# Generated deterministically by seda-macro-lef-normalizer-v1; recipe orfs-ng45-fakeram-metal3-coupledl2-pg-v1.
VERSION 5.8 ;
BUSBITCHARS "[]" ;
DIVIDERCHAR "/" ;

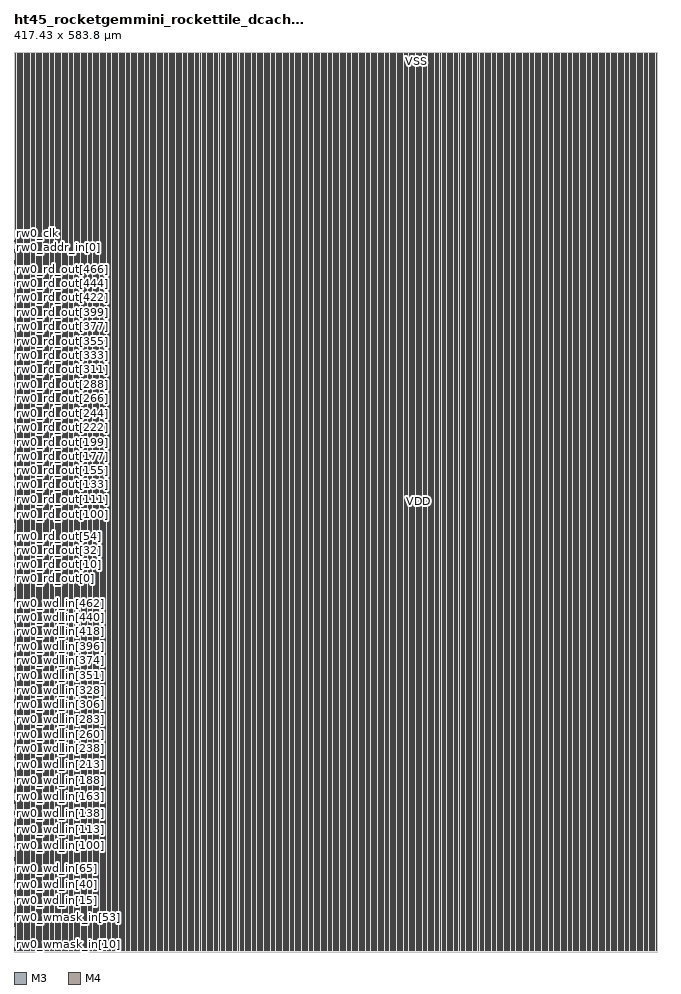
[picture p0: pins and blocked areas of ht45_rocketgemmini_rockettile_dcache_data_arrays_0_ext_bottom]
MACRO ht45_rocketgemmini_rockettile_dcache_data_arrays_0_ext_bottom
  FOREIGN ht45_rocketgemmini_rockettile_dcache_data_arrays_0_ext_bottom 0 0 ;
  CLASS COVER ;
  ORIGIN 0 0 ;
  SIZE 417.43 BY 583.8 ;
  SYMMETRY X Y R90 ;
  PIN rw0_wmask_in[0]
    DIRECTION INPUT ;
    USE SIGNAL ;
    SHAPE ABUTMENT ;
    PORT
      LAYER M3 ;
      RECT 0 0.035 0.07 0.105 ;
    END
  END rw0_wmask_in[0]
  PIN rw0_wmask_in[1]
    DIRECTION INPUT ;
    USE SIGNAL ;
    SHAPE ABUTMENT ;
    PORT
      LAYER M3 ;
      RECT 0 0.455 0.07 0.525 ;
    END
  END rw0_wmask_in[1]
  PIN rw0_wmask_in[2]
    DIRECTION INPUT ;
    USE SIGNAL ;
    SHAPE ABUTMENT ;
    PORT
      LAYER M3 ;
      RECT 0 0.875 0.07 0.945 ;
    END
  END rw0_wmask_in[2]
  PIN rw0_wmask_in[3]
    DIRECTION INPUT ;
    USE SIGNAL ;
    SHAPE ABUTMENT ;
    PORT
      LAYER M3 ;
      RECT 0 1.295 0.07 1.365 ;
    END
  END rw0_wmask_in[3]
  PIN rw0_wmask_in[4]
    DIRECTION INPUT ;
    USE SIGNAL ;
    SHAPE ABUTMENT ;
    PORT
      LAYER M3 ;
      RECT 0 1.715 0.07 1.785 ;
    END
  END rw0_wmask_in[4]
  PIN rw0_wmask_in[5]
    DIRECTION INPUT ;
    USE SIGNAL ;
    SHAPE ABUTMENT ;
    PORT
      LAYER M3 ;
      RECT 0 2.135 0.07 2.205 ;
    END
  END rw0_wmask_in[5]
  PIN rw0_wmask_in[6]
    DIRECTION INPUT ;
    USE SIGNAL ;
    SHAPE ABUTMENT ;
    PORT
      LAYER M3 ;
      RECT 0 2.555 0.07 2.625 ;
    END
  END rw0_wmask_in[6]
  PIN rw0_wmask_in[7]
    DIRECTION INPUT ;
    USE SIGNAL ;
    SHAPE ABUTMENT ;
    PORT
      LAYER M3 ;
      RECT 0 2.975 0.07 3.045 ;
    END
  END rw0_wmask_in[7]
  PIN rw0_wmask_in[8]
    DIRECTION INPUT ;
    USE SIGNAL ;
    SHAPE ABUTMENT ;
    PORT
      LAYER M3 ;
      RECT 0 3.395 0.07 3.465 ;
    END
  END rw0_wmask_in[8]
  PIN rw0_wmask_in[9]
    DIRECTION INPUT ;
    USE SIGNAL ;
    SHAPE ABUTMENT ;
    PORT
      LAYER M3 ;
      RECT 0 3.815 0.07 3.885 ;
    END
  END rw0_wmask_in[9]
  PIN rw0_wmask_in[10]
    DIRECTION INPUT ;
    USE SIGNAL ;
    SHAPE ABUTMENT ;
    PORT
      LAYER M3 ;
      RECT 0 4.235 0.07 4.305 ;
    END
  END rw0_wmask_in[10]
  PIN rw0_wmask_in[11]
    DIRECTION INPUT ;
    USE SIGNAL ;
    SHAPE ABUTMENT ;
    PORT
      LAYER M3 ;
      RECT 0 4.655 0.07 4.725 ;
    END
  END rw0_wmask_in[11]
  PIN rw0_wmask_in[12]
    DIRECTION INPUT ;
    USE SIGNAL ;
    SHAPE ABUTMENT ;
    PORT
      LAYER M3 ;
      RECT 0 5.075 0.07 5.145 ;
    END
  END rw0_wmask_in[12]
  PIN rw0_wmask_in[13]
    DIRECTION INPUT ;
    USE SIGNAL ;
    SHAPE ABUTMENT ;
    PORT
      LAYER M3 ;
      RECT 0 5.495 0.07 5.565 ;
    END
  END rw0_wmask_in[13]
  PIN rw0_wmask_in[14]
    DIRECTION INPUT ;
    USE SIGNAL ;
    SHAPE ABUTMENT ;
    PORT
      LAYER M3 ;
      RECT 0 5.915 0.07 5.985 ;
    END
  END rw0_wmask_in[14]
  PIN rw0_wmask_in[15]
    DIRECTION INPUT ;
    USE SIGNAL ;
    SHAPE ABUTMENT ;
    PORT
      LAYER M3 ;
      RECT 0 6.335 0.07 6.405 ;
    END
  END rw0_wmask_in[15]
  PIN rw0_wmask_in[16]
    DIRECTION INPUT ;
    USE SIGNAL ;
    SHAPE ABUTMENT ;
    PORT
      LAYER M3 ;
      RECT 0 6.755 0.07 6.825 ;
    END
  END rw0_wmask_in[16]
  PIN rw0_wmask_in[17]
    DIRECTION INPUT ;
    USE SIGNAL ;
    SHAPE ABUTMENT ;
    PORT
      LAYER M3 ;
      RECT 0 7.175 0.07 7.245 ;
    END
  END rw0_wmask_in[17]
  PIN rw0_wmask_in[18]
    DIRECTION INPUT ;
    USE SIGNAL ;
    SHAPE ABUTMENT ;
    PORT
      LAYER M3 ;
      RECT 0 7.595 0.07 7.665 ;
    END
  END rw0_wmask_in[18]
  PIN rw0_wmask_in[19]
    DIRECTION INPUT ;
    USE SIGNAL ;
    SHAPE ABUTMENT ;
    PORT
      LAYER M3 ;
      RECT 0 8.015 0.07 8.085 ;
    END
  END rw0_wmask_in[19]
  PIN rw0_wmask_in[20]
    DIRECTION INPUT ;
    USE SIGNAL ;
    SHAPE ABUTMENT ;
    PORT
      LAYER M3 ;
      RECT 0 8.435 0.07 8.505 ;
    END
  END rw0_wmask_in[20]
  PIN rw0_wmask_in[21]
    DIRECTION INPUT ;
    USE SIGNAL ;
    SHAPE ABUTMENT ;
    PORT
      LAYER M3 ;
      RECT 0 8.855 0.07 8.925 ;
    END
  END rw0_wmask_in[21]
  PIN rw0_wmask_in[22]
    DIRECTION INPUT ;
    USE SIGNAL ;
    SHAPE ABUTMENT ;
    PORT
      LAYER M3 ;
      RECT 0 9.275 0.07 9.345 ;
    END
  END rw0_wmask_in[22]
  PIN rw0_wmask_in[23]
    DIRECTION INPUT ;
    USE SIGNAL ;
    SHAPE ABUTMENT ;
    PORT
      LAYER M3 ;
      RECT 0 9.695 0.07 9.765 ;
    END
  END rw0_wmask_in[23]
  PIN rw0_wmask_in[24]
    DIRECTION INPUT ;
    USE SIGNAL ;
    SHAPE ABUTMENT ;
    PORT
      LAYER M3 ;
      RECT 0 10.115 0.07 10.185 ;
    END
  END rw0_wmask_in[24]
  PIN rw0_wmask_in[25]
    DIRECTION INPUT ;
    USE SIGNAL ;
    SHAPE ABUTMENT ;
    PORT
      LAYER M3 ;
      RECT 0 10.535 0.07 10.605 ;
    END
  END rw0_wmask_in[25]
  PIN rw0_wmask_in[26]
    DIRECTION INPUT ;
    USE SIGNAL ;
    SHAPE ABUTMENT ;
    PORT
      LAYER M3 ;
      RECT 0 10.955 0.07 11.025 ;
    END
  END rw0_wmask_in[26]
  PIN rw0_wmask_in[27]
    DIRECTION INPUT ;
    USE SIGNAL ;
    SHAPE ABUTMENT ;
    PORT
      LAYER M3 ;
      RECT 0 11.375 0.07 11.445 ;
    END
  END rw0_wmask_in[27]
  PIN rw0_wmask_in[28]
    DIRECTION INPUT ;
    USE SIGNAL ;
    SHAPE ABUTMENT ;
    PORT
      LAYER M3 ;
      RECT 0 11.795 0.07 11.865 ;
    END
  END rw0_wmask_in[28]
  PIN rw0_wmask_in[29]
    DIRECTION INPUT ;
    USE SIGNAL ;
    SHAPE ABUTMENT ;
    PORT
      LAYER M3 ;
      RECT 0 12.215 0.07 12.285 ;
    END
  END rw0_wmask_in[29]
  PIN rw0_wmask_in[30]
    DIRECTION INPUT ;
    USE SIGNAL ;
    SHAPE ABUTMENT ;
    PORT
      LAYER M3 ;
      RECT 0 12.635 0.07 12.705 ;
    END
  END rw0_wmask_in[30]
  PIN rw0_wmask_in[31]
    DIRECTION INPUT ;
    USE SIGNAL ;
    SHAPE ABUTMENT ;
    PORT
      LAYER M3 ;
      RECT 0 13.055 0.07 13.125 ;
    END
  END rw0_wmask_in[31]
  PIN rw0_wmask_in[32]
    DIRECTION INPUT ;
    USE SIGNAL ;
    SHAPE ABUTMENT ;
    PORT
      LAYER M3 ;
      RECT 0 13.475 0.07 13.545 ;
    END
  END rw0_wmask_in[32]
  PIN rw0_wmask_in[33]
    DIRECTION INPUT ;
    USE SIGNAL ;
    SHAPE ABUTMENT ;
    PORT
      LAYER M3 ;
      RECT 0 13.895 0.07 13.965 ;
    END
  END rw0_wmask_in[33]
  PIN rw0_wmask_in[34]
    DIRECTION INPUT ;
    USE SIGNAL ;
    SHAPE ABUTMENT ;
    PORT
      LAYER M3 ;
      RECT 0 14.315 0.07 14.385 ;
    END
  END rw0_wmask_in[34]
  PIN rw0_wmask_in[35]
    DIRECTION INPUT ;
    USE SIGNAL ;
    SHAPE ABUTMENT ;
    PORT
      LAYER M3 ;
      RECT 0 14.735 0.07 14.805 ;
    END
  END rw0_wmask_in[35]
  PIN rw0_wmask_in[36]
    DIRECTION INPUT ;
    USE SIGNAL ;
    SHAPE ABUTMENT ;
    PORT
      LAYER M3 ;
      RECT 0 15.155 0.07 15.225 ;
    END
  END rw0_wmask_in[36]
  PIN rw0_wmask_in[37]
    DIRECTION INPUT ;
    USE SIGNAL ;
    SHAPE ABUTMENT ;
    PORT
      LAYER M3 ;
      RECT 0 15.575 0.07 15.645 ;
    END
  END rw0_wmask_in[37]
  PIN rw0_wmask_in[38]
    DIRECTION INPUT ;
    USE SIGNAL ;
    SHAPE ABUTMENT ;
    PORT
      LAYER M3 ;
      RECT 0 15.995 0.07 16.065 ;
    END
  END rw0_wmask_in[38]
  PIN rw0_wmask_in[39]
    DIRECTION INPUT ;
    USE SIGNAL ;
    SHAPE ABUTMENT ;
    PORT
      LAYER M3 ;
      RECT 0 16.415 0.07 16.485 ;
    END
  END rw0_wmask_in[39]
  PIN rw0_wmask_in[40]
    DIRECTION INPUT ;
    USE SIGNAL ;
    SHAPE ABUTMENT ;
    PORT
      LAYER M3 ;
      RECT 0 16.835 0.07 16.905 ;
    END
  END rw0_wmask_in[40]
  PIN rw0_wmask_in[41]
    DIRECTION INPUT ;
    USE SIGNAL ;
    SHAPE ABUTMENT ;
    PORT
      LAYER M3 ;
      RECT 0 17.255 0.07 17.325 ;
    END
  END rw0_wmask_in[41]
  PIN rw0_wmask_in[42]
    DIRECTION INPUT ;
    USE SIGNAL ;
    SHAPE ABUTMENT ;
    PORT
      LAYER M3 ;
      RECT 0 17.675 0.07 17.745 ;
    END
  END rw0_wmask_in[42]
  PIN rw0_wmask_in[43]
    DIRECTION INPUT ;
    USE SIGNAL ;
    SHAPE ABUTMENT ;
    PORT
      LAYER M3 ;
      RECT 0 18.095 0.07 18.165 ;
    END
  END rw0_wmask_in[43]
  PIN rw0_wmask_in[44]
    DIRECTION INPUT ;
    USE SIGNAL ;
    SHAPE ABUTMENT ;
    PORT
      LAYER M3 ;
      RECT 0 18.515 0.07 18.585 ;
    END
  END rw0_wmask_in[44]
  PIN rw0_wmask_in[45]
    DIRECTION INPUT ;
    USE SIGNAL ;
    SHAPE ABUTMENT ;
    PORT
      LAYER M3 ;
      RECT 0 18.935 0.07 19.005 ;
    END
  END rw0_wmask_in[45]
  PIN rw0_wmask_in[46]
    DIRECTION INPUT ;
    USE SIGNAL ;
    SHAPE ABUTMENT ;
    PORT
      LAYER M3 ;
      RECT 0 19.355 0.07 19.425 ;
    END
  END rw0_wmask_in[46]
  PIN rw0_wmask_in[47]
    DIRECTION INPUT ;
    USE SIGNAL ;
    SHAPE ABUTMENT ;
    PORT
      LAYER M3 ;
      RECT 0 19.775 0.07 19.845 ;
    END
  END rw0_wmask_in[47]
  PIN rw0_wmask_in[48]
    DIRECTION INPUT ;
    USE SIGNAL ;
    SHAPE ABUTMENT ;
    PORT
      LAYER M3 ;
      RECT 0 20.195 0.07 20.265 ;
    END
  END rw0_wmask_in[48]
  PIN rw0_wmask_in[49]
    DIRECTION INPUT ;
    USE SIGNAL ;
    SHAPE ABUTMENT ;
    PORT
      LAYER M3 ;
      RECT 0 20.615 0.07 20.685 ;
    END
  END rw0_wmask_in[49]
  PIN rw0_wmask_in[50]
    DIRECTION INPUT ;
    USE SIGNAL ;
    SHAPE ABUTMENT ;
    PORT
      LAYER M3 ;
      RECT 0 21.035 0.07 21.105 ;
    END
  END rw0_wmask_in[50]
  PIN rw0_wmask_in[51]
    DIRECTION INPUT ;
    USE SIGNAL ;
    SHAPE ABUTMENT ;
    PORT
      LAYER M3 ;
      RECT 0 21.455 0.07 21.525 ;
    END
  END rw0_wmask_in[51]
  PIN rw0_wmask_in[52]
    DIRECTION INPUT ;
    USE SIGNAL ;
    SHAPE ABUTMENT ;
    PORT
      LAYER M3 ;
      RECT 0 21.875 0.07 21.945 ;
    END
  END rw0_wmask_in[52]
  PIN rw0_wmask_in[53]
    DIRECTION INPUT ;
    USE SIGNAL ;
    SHAPE ABUTMENT ;
    PORT
      LAYER M3 ;
      RECT 0 22.295 0.07 22.365 ;
    END
  END rw0_wmask_in[53]
  PIN rw0_wmask_in[54]
    DIRECTION INPUT ;
    USE SIGNAL ;
    SHAPE ABUTMENT ;
    PORT
      LAYER M3 ;
      RECT 0 22.715 0.07 22.785 ;
    END
  END rw0_wmask_in[54]
  PIN rw0_wmask_in[55]
    DIRECTION INPUT ;
    USE SIGNAL ;
    SHAPE ABUTMENT ;
    PORT
      LAYER M3 ;
      RECT 0 23.135 0.07 23.205 ;
    END
  END rw0_wmask_in[55]
  PIN rw0_wmask_in[56]
    DIRECTION INPUT ;
    USE SIGNAL ;
    SHAPE ABUTMENT ;
    PORT
      LAYER M3 ;
      RECT 0 23.555 0.07 23.625 ;
    END
  END rw0_wmask_in[56]
  PIN rw0_wmask_in[57]
    DIRECTION INPUT ;
    USE SIGNAL ;
    SHAPE ABUTMENT ;
    PORT
      LAYER M3 ;
      RECT 0 23.975 0.07 24.045 ;
    END
  END rw0_wmask_in[57]
  PIN rw0_wmask_in[58]
    DIRECTION INPUT ;
    USE SIGNAL ;
    SHAPE ABUTMENT ;
    PORT
      LAYER M3 ;
      RECT 0 24.395 0.07 24.465 ;
    END
  END rw0_wmask_in[58]
  PIN rw0_wmask_in[59]
    DIRECTION INPUT ;
    USE SIGNAL ;
    SHAPE ABUTMENT ;
    PORT
      LAYER M3 ;
      RECT 0 24.815 0.07 24.885 ;
    END
  END rw0_wmask_in[59]
  PIN rw0_wmask_in[60]
    DIRECTION INPUT ;
    USE SIGNAL ;
    SHAPE ABUTMENT ;
    PORT
      LAYER M3 ;
      RECT 0 25.235 0.07 25.305 ;
    END
  END rw0_wmask_in[60]
  PIN rw0_wmask_in[61]
    DIRECTION INPUT ;
    USE SIGNAL ;
    SHAPE ABUTMENT ;
    PORT
      LAYER M3 ;
      RECT 0 25.655 0.07 25.725 ;
    END
  END rw0_wmask_in[61]
  PIN rw0_wmask_in[62]
    DIRECTION INPUT ;
    USE SIGNAL ;
    SHAPE ABUTMENT ;
    PORT
      LAYER M3 ;
      RECT 0 26.075 0.07 26.145 ;
    END
  END rw0_wmask_in[62]
  PIN rw0_wmask_in[63]
    DIRECTION INPUT ;
    USE SIGNAL ;
    SHAPE ABUTMENT ;
    PORT
      LAYER M3 ;
      RECT 0 26.495 0.07 26.565 ;
    END
  END rw0_wmask_in[63]
  PIN rw0_wd_in[0]
    DIRECTION INPUT ;
    USE SIGNAL ;
    SHAPE ABUTMENT ;
    PORT
      LAYER M3 ;
      RECT 0 26.915 0.07 26.985 ;
    END
  END rw0_wd_in[0]
  PIN rw0_wd_in[1]
    DIRECTION INPUT ;
    USE SIGNAL ;
    SHAPE ABUTMENT ;
    PORT
      LAYER M3 ;
      RECT 0 27.335 0.07 27.405 ;
    END
  END rw0_wd_in[1]
  PIN rw0_wd_in[2]
    DIRECTION INPUT ;
    USE SIGNAL ;
    SHAPE ABUTMENT ;
    PORT
      LAYER M3 ;
      RECT 0 27.755 0.07 27.825 ;
    END
  END rw0_wd_in[2]
  PIN rw0_wd_in[3]
    DIRECTION INPUT ;
    USE SIGNAL ;
    SHAPE ABUTMENT ;
    PORT
      LAYER M3 ;
      RECT 0 28.175 0.07 28.245 ;
    END
  END rw0_wd_in[3]
  PIN rw0_wd_in[4]
    DIRECTION INPUT ;
    USE SIGNAL ;
    SHAPE ABUTMENT ;
    PORT
      LAYER M3 ;
      RECT 0 28.595 0.07 28.665 ;
    END
  END rw0_wd_in[4]
  PIN rw0_wd_in[5]
    DIRECTION INPUT ;
    USE SIGNAL ;
    SHAPE ABUTMENT ;
    PORT
      LAYER M3 ;
      RECT 0 29.015 0.07 29.085 ;
    END
  END rw0_wd_in[5]
  PIN rw0_wd_in[6]
    DIRECTION INPUT ;
    USE SIGNAL ;
    SHAPE ABUTMENT ;
    PORT
      LAYER M3 ;
      RECT 0 29.435 0.07 29.505 ;
    END
  END rw0_wd_in[6]
  PIN rw0_wd_in[7]
    DIRECTION INPUT ;
    USE SIGNAL ;
    SHAPE ABUTMENT ;
    PORT
      LAYER M3 ;
      RECT 0 29.855 0.07 29.925 ;
    END
  END rw0_wd_in[7]
  PIN rw0_wd_in[8]
    DIRECTION INPUT ;
    USE SIGNAL ;
    SHAPE ABUTMENT ;
    PORT
      LAYER M3 ;
      RECT 0 30.275 0.07 30.345 ;
    END
  END rw0_wd_in[8]
  PIN rw0_wd_in[9]
    DIRECTION INPUT ;
    USE SIGNAL ;
    SHAPE ABUTMENT ;
    PORT
      LAYER M3 ;
      RECT 0 30.695 0.07 30.765 ;
    END
  END rw0_wd_in[9]
  PIN rw0_wd_in[10]
    DIRECTION INPUT ;
    USE SIGNAL ;
    SHAPE ABUTMENT ;
    PORT
      LAYER M3 ;
      RECT 0 31.115 0.07 31.185 ;
    END
  END rw0_wd_in[10]
  PIN rw0_wd_in[11]
    DIRECTION INPUT ;
    USE SIGNAL ;
    SHAPE ABUTMENT ;
    PORT
      LAYER M3 ;
      RECT 0 31.535 0.07 31.605 ;
    END
  END rw0_wd_in[11]
  PIN rw0_wd_in[12]
    DIRECTION INPUT ;
    USE SIGNAL ;
    SHAPE ABUTMENT ;
    PORT
      LAYER M3 ;
      RECT 0 31.955 0.07 32.025 ;
    END
  END rw0_wd_in[12]
  PIN rw0_wd_in[13]
    DIRECTION INPUT ;
    USE SIGNAL ;
    SHAPE ABUTMENT ;
    PORT
      LAYER M3 ;
      RECT 0 32.375 0.07 32.445 ;
    END
  END rw0_wd_in[13]
  PIN rw0_wd_in[14]
    DIRECTION INPUT ;
    USE SIGNAL ;
    SHAPE ABUTMENT ;
    PORT
      LAYER M3 ;
      RECT 0 32.795 0.07 32.865 ;
    END
  END rw0_wd_in[14]
  PIN rw0_wd_in[15]
    DIRECTION INPUT ;
    USE SIGNAL ;
    SHAPE ABUTMENT ;
    PORT
      LAYER M3 ;
      RECT 0 33.215 0.07 33.285 ;
    END
  END rw0_wd_in[15]
  PIN rw0_wd_in[16]
    DIRECTION INPUT ;
    USE SIGNAL ;
    SHAPE ABUTMENT ;
    PORT
      LAYER M3 ;
      RECT 0 33.635 0.07 33.705 ;
    END
  END rw0_wd_in[16]
  PIN rw0_wd_in[17]
    DIRECTION INPUT ;
    USE SIGNAL ;
    SHAPE ABUTMENT ;
    PORT
      LAYER M3 ;
      RECT 0 34.055 0.07 34.125 ;
    END
  END rw0_wd_in[17]
  PIN rw0_wd_in[18]
    DIRECTION INPUT ;
    USE SIGNAL ;
    SHAPE ABUTMENT ;
    PORT
      LAYER M3 ;
      RECT 0 34.475 0.07 34.545 ;
    END
  END rw0_wd_in[18]
  PIN rw0_wd_in[19]
    DIRECTION INPUT ;
    USE SIGNAL ;
    SHAPE ABUTMENT ;
    PORT
      LAYER M3 ;
      RECT 0 34.895 0.07 34.965 ;
    END
  END rw0_wd_in[19]
  PIN rw0_wd_in[20]
    DIRECTION INPUT ;
    USE SIGNAL ;
    SHAPE ABUTMENT ;
    PORT
      LAYER M3 ;
      RECT 0 35.315 0.07 35.385 ;
    END
  END rw0_wd_in[20]
  PIN rw0_wd_in[21]
    DIRECTION INPUT ;
    USE SIGNAL ;
    SHAPE ABUTMENT ;
    PORT
      LAYER M3 ;
      RECT 0 35.735 0.07 35.805 ;
    END
  END rw0_wd_in[21]
  PIN rw0_wd_in[22]
    DIRECTION INPUT ;
    USE SIGNAL ;
    SHAPE ABUTMENT ;
    PORT
      LAYER M3 ;
      RECT 0 36.155 0.07 36.225 ;
    END
  END rw0_wd_in[22]
  PIN rw0_wd_in[23]
    DIRECTION INPUT ;
    USE SIGNAL ;
    SHAPE ABUTMENT ;
    PORT
      LAYER M3 ;
      RECT 0 36.575 0.07 36.645 ;
    END
  END rw0_wd_in[23]
  PIN rw0_wd_in[24]
    DIRECTION INPUT ;
    USE SIGNAL ;
    SHAPE ABUTMENT ;
    PORT
      LAYER M3 ;
      RECT 0 36.995 0.07 37.065 ;
    END
  END rw0_wd_in[24]
  PIN rw0_wd_in[25]
    DIRECTION INPUT ;
    USE SIGNAL ;
    SHAPE ABUTMENT ;
    PORT
      LAYER M3 ;
      RECT 0 37.415 0.07 37.485 ;
    END
  END rw0_wd_in[25]
  PIN rw0_wd_in[26]
    DIRECTION INPUT ;
    USE SIGNAL ;
    SHAPE ABUTMENT ;
    PORT
      LAYER M3 ;
      RECT 0 37.835 0.07 37.905 ;
    END
  END rw0_wd_in[26]
  PIN rw0_wd_in[27]
    DIRECTION INPUT ;
    USE SIGNAL ;
    SHAPE ABUTMENT ;
    PORT
      LAYER M3 ;
      RECT 0 38.255 0.07 38.325 ;
    END
  END rw0_wd_in[27]
  PIN rw0_wd_in[28]
    DIRECTION INPUT ;
    USE SIGNAL ;
    SHAPE ABUTMENT ;
    PORT
      LAYER M3 ;
      RECT 0 38.675 0.07 38.745 ;
    END
  END rw0_wd_in[28]
  PIN rw0_wd_in[29]
    DIRECTION INPUT ;
    USE SIGNAL ;
    SHAPE ABUTMENT ;
    PORT
      LAYER M3 ;
      RECT 0 39.095 0.07 39.165 ;
    END
  END rw0_wd_in[29]
  PIN rw0_wd_in[30]
    DIRECTION INPUT ;
    USE SIGNAL ;
    SHAPE ABUTMENT ;
    PORT
      LAYER M3 ;
      RECT 0 39.515 0.07 39.585 ;
    END
  END rw0_wd_in[30]
  PIN rw0_wd_in[31]
    DIRECTION INPUT ;
    USE SIGNAL ;
    SHAPE ABUTMENT ;
    PORT
      LAYER M3 ;
      RECT 0 39.935 0.07 40.005 ;
    END
  END rw0_wd_in[31]
  PIN rw0_wd_in[32]
    DIRECTION INPUT ;
    USE SIGNAL ;
    SHAPE ABUTMENT ;
    PORT
      LAYER M3 ;
      RECT 0 40.355 0.07 40.425 ;
    END
  END rw0_wd_in[32]
  PIN rw0_wd_in[33]
    DIRECTION INPUT ;
    USE SIGNAL ;
    SHAPE ABUTMENT ;
    PORT
      LAYER M3 ;
      RECT 0 40.775 0.07 40.845 ;
    END
  END rw0_wd_in[33]
  PIN rw0_wd_in[34]
    DIRECTION INPUT ;
    USE SIGNAL ;
    SHAPE ABUTMENT ;
    PORT
      LAYER M3 ;
      RECT 0 41.195 0.07 41.265 ;
    END
  END rw0_wd_in[34]
  PIN rw0_wd_in[35]
    DIRECTION INPUT ;
    USE SIGNAL ;
    SHAPE ABUTMENT ;
    PORT
      LAYER M3 ;
      RECT 0 41.615 0.07 41.685 ;
    END
  END rw0_wd_in[35]
  PIN rw0_wd_in[36]
    DIRECTION INPUT ;
    USE SIGNAL ;
    SHAPE ABUTMENT ;
    PORT
      LAYER M3 ;
      RECT 0 42.035 0.07 42.105 ;
    END
  END rw0_wd_in[36]
  PIN rw0_wd_in[37]
    DIRECTION INPUT ;
    USE SIGNAL ;
    SHAPE ABUTMENT ;
    PORT
      LAYER M3 ;
      RECT 0 42.455 0.07 42.525 ;
    END
  END rw0_wd_in[37]
  PIN rw0_wd_in[38]
    DIRECTION INPUT ;
    USE SIGNAL ;
    SHAPE ABUTMENT ;
    PORT
      LAYER M3 ;
      RECT 0 42.875 0.07 42.945 ;
    END
  END rw0_wd_in[38]
  PIN rw0_wd_in[39]
    DIRECTION INPUT ;
    USE SIGNAL ;
    SHAPE ABUTMENT ;
    PORT
      LAYER M3 ;
      RECT 0 43.295 0.07 43.365 ;
    END
  END rw0_wd_in[39]
  PIN rw0_wd_in[40]
    DIRECTION INPUT ;
    USE SIGNAL ;
    SHAPE ABUTMENT ;
    PORT
      LAYER M3 ;
      RECT 0 43.715 0.07 43.785 ;
    END
  END rw0_wd_in[40]
  PIN rw0_wd_in[41]
    DIRECTION INPUT ;
    USE SIGNAL ;
    SHAPE ABUTMENT ;
    PORT
      LAYER M3 ;
      RECT 0 44.135 0.07 44.205 ;
    END
  END rw0_wd_in[41]
  PIN rw0_wd_in[42]
    DIRECTION INPUT ;
    USE SIGNAL ;
    SHAPE ABUTMENT ;
    PORT
      LAYER M3 ;
      RECT 0 44.555 0.07 44.625 ;
    END
  END rw0_wd_in[42]
  PIN rw0_wd_in[43]
    DIRECTION INPUT ;
    USE SIGNAL ;
    SHAPE ABUTMENT ;
    PORT
      LAYER M3 ;
      RECT 0 44.975 0.07 45.045 ;
    END
  END rw0_wd_in[43]
  PIN rw0_wd_in[44]
    DIRECTION INPUT ;
    USE SIGNAL ;
    SHAPE ABUTMENT ;
    PORT
      LAYER M3 ;
      RECT 0 45.395 0.07 45.465 ;
    END
  END rw0_wd_in[44]
  PIN rw0_wd_in[45]
    DIRECTION INPUT ;
    USE SIGNAL ;
    SHAPE ABUTMENT ;
    PORT
      LAYER M3 ;
      RECT 0 45.815 0.07 45.885 ;
    END
  END rw0_wd_in[45]
  PIN rw0_wd_in[46]
    DIRECTION INPUT ;
    USE SIGNAL ;
    SHAPE ABUTMENT ;
    PORT
      LAYER M3 ;
      RECT 0 46.235 0.07 46.305 ;
    END
  END rw0_wd_in[46]
  PIN rw0_wd_in[47]
    DIRECTION INPUT ;
    USE SIGNAL ;
    SHAPE ABUTMENT ;
    PORT
      LAYER M3 ;
      RECT 0 46.655 0.07 46.725 ;
    END
  END rw0_wd_in[47]
  PIN rw0_wd_in[48]
    DIRECTION INPUT ;
    USE SIGNAL ;
    SHAPE ABUTMENT ;
    PORT
      LAYER M3 ;
      RECT 0 47.075 0.07 47.145 ;
    END
  END rw0_wd_in[48]
  PIN rw0_wd_in[49]
    DIRECTION INPUT ;
    USE SIGNAL ;
    SHAPE ABUTMENT ;
    PORT
      LAYER M3 ;
      RECT 0 47.495 0.07 47.565 ;
    END
  END rw0_wd_in[49]
  PIN rw0_wd_in[50]
    DIRECTION INPUT ;
    USE SIGNAL ;
    SHAPE ABUTMENT ;
    PORT
      LAYER M3 ;
      RECT 0 47.915 0.07 47.985 ;
    END
  END rw0_wd_in[50]
  PIN rw0_wd_in[51]
    DIRECTION INPUT ;
    USE SIGNAL ;
    SHAPE ABUTMENT ;
    PORT
      LAYER M3 ;
      RECT 0 48.335 0.07 48.405 ;
    END
  END rw0_wd_in[51]
  PIN rw0_wd_in[52]
    DIRECTION INPUT ;
    USE SIGNAL ;
    SHAPE ABUTMENT ;
    PORT
      LAYER M3 ;
      RECT 0 48.755 0.07 48.825 ;
    END
  END rw0_wd_in[52]
  PIN rw0_wd_in[53]
    DIRECTION INPUT ;
    USE SIGNAL ;
    SHAPE ABUTMENT ;
    PORT
      LAYER M3 ;
      RECT 0 49.175 0.07 49.245 ;
    END
  END rw0_wd_in[53]
  PIN rw0_wd_in[54]
    DIRECTION INPUT ;
    USE SIGNAL ;
    SHAPE ABUTMENT ;
    PORT
      LAYER M3 ;
      RECT 0 49.595 0.07 49.665 ;
    END
  END rw0_wd_in[54]
  PIN rw0_wd_in[55]
    DIRECTION INPUT ;
    USE SIGNAL ;
    SHAPE ABUTMENT ;
    PORT
      LAYER M3 ;
      RECT 0 50.015 0.07 50.085 ;
    END
  END rw0_wd_in[55]
  PIN rw0_wd_in[56]
    DIRECTION INPUT ;
    USE SIGNAL ;
    SHAPE ABUTMENT ;
    PORT
      LAYER M3 ;
      RECT 0 50.435 0.07 50.505 ;
    END
  END rw0_wd_in[56]
  PIN rw0_wd_in[57]
    DIRECTION INPUT ;
    USE SIGNAL ;
    SHAPE ABUTMENT ;
    PORT
      LAYER M3 ;
      RECT 0 50.855 0.07 50.925 ;
    END
  END rw0_wd_in[57]
  PIN rw0_wd_in[58]
    DIRECTION INPUT ;
    USE SIGNAL ;
    SHAPE ABUTMENT ;
    PORT
      LAYER M3 ;
      RECT 0 51.275 0.07 51.345 ;
    END
  END rw0_wd_in[58]
  PIN rw0_wd_in[59]
    DIRECTION INPUT ;
    USE SIGNAL ;
    SHAPE ABUTMENT ;
    PORT
      LAYER M3 ;
      RECT 0 51.695 0.07 51.765 ;
    END
  END rw0_wd_in[59]
  PIN rw0_wd_in[60]
    DIRECTION INPUT ;
    USE SIGNAL ;
    SHAPE ABUTMENT ;
    PORT
      LAYER M3 ;
      RECT 0 52.115 0.07 52.185 ;
    END
  END rw0_wd_in[60]
  PIN rw0_wd_in[61]
    DIRECTION INPUT ;
    USE SIGNAL ;
    SHAPE ABUTMENT ;
    PORT
      LAYER M3 ;
      RECT 0 52.535 0.07 52.605 ;
    END
  END rw0_wd_in[61]
  PIN rw0_wd_in[62]
    DIRECTION INPUT ;
    USE SIGNAL ;
    SHAPE ABUTMENT ;
    PORT
      LAYER M3 ;
      RECT 0 52.955 0.07 53.025 ;
    END
  END rw0_wd_in[62]
  PIN rw0_wd_in[63]
    DIRECTION INPUT ;
    USE SIGNAL ;
    SHAPE ABUTMENT ;
    PORT
      LAYER M3 ;
      RECT 0 53.375 0.07 53.445 ;
    END
  END rw0_wd_in[63]
  PIN rw0_wd_in[64]
    DIRECTION INPUT ;
    USE SIGNAL ;
    SHAPE ABUTMENT ;
    PORT
      LAYER M3 ;
      RECT 0 53.795 0.07 53.865 ;
    END
  END rw0_wd_in[64]
  PIN rw0_wd_in[65]
    DIRECTION INPUT ;
    USE SIGNAL ;
    SHAPE ABUTMENT ;
    PORT
      LAYER M3 ;
      RECT 0 54.215 0.07 54.285 ;
    END
  END rw0_wd_in[65]
  PIN rw0_wd_in[66]
    DIRECTION INPUT ;
    USE SIGNAL ;
    SHAPE ABUTMENT ;
    PORT
      LAYER M3 ;
      RECT 0 54.635 0.07 54.705 ;
    END
  END rw0_wd_in[66]
  PIN rw0_wd_in[67]
    DIRECTION INPUT ;
    USE SIGNAL ;
    SHAPE ABUTMENT ;
    PORT
      LAYER M3 ;
      RECT 0 55.055 0.07 55.125 ;
    END
  END rw0_wd_in[67]
  PIN rw0_wd_in[68]
    DIRECTION INPUT ;
    USE SIGNAL ;
    SHAPE ABUTMENT ;
    PORT
      LAYER M3 ;
      RECT 0 55.475 0.07 55.545 ;
    END
  END rw0_wd_in[68]
  PIN rw0_wd_in[69]
    DIRECTION INPUT ;
    USE SIGNAL ;
    SHAPE ABUTMENT ;
    PORT
      LAYER M3 ;
      RECT 0 55.895 0.07 55.965 ;
    END
  END rw0_wd_in[69]
  PIN rw0_wd_in[70]
    DIRECTION INPUT ;
    USE SIGNAL ;
    SHAPE ABUTMENT ;
    PORT
      LAYER M3 ;
      RECT 0 56.315 0.07 56.385 ;
    END
  END rw0_wd_in[70]
  PIN rw0_wd_in[71]
    DIRECTION INPUT ;
    USE SIGNAL ;
    SHAPE ABUTMENT ;
    PORT
      LAYER M3 ;
      RECT 0 56.735 0.07 56.805 ;
    END
  END rw0_wd_in[71]
  PIN rw0_wd_in[72]
    DIRECTION INPUT ;
    USE SIGNAL ;
    SHAPE ABUTMENT ;
    PORT
      LAYER M3 ;
      RECT 0 57.155 0.07 57.225 ;
    END
  END rw0_wd_in[72]
  PIN rw0_wd_in[73]
    DIRECTION INPUT ;
    USE SIGNAL ;
    SHAPE ABUTMENT ;
    PORT
      LAYER M3 ;
      RECT 0 57.575 0.07 57.645 ;
    END
  END rw0_wd_in[73]
  PIN rw0_wd_in[74]
    DIRECTION INPUT ;
    USE SIGNAL ;
    SHAPE ABUTMENT ;
    PORT
      LAYER M3 ;
      RECT 0 57.995 0.07 58.065 ;
    END
  END rw0_wd_in[74]
  PIN rw0_wd_in[75]
    DIRECTION INPUT ;
    USE SIGNAL ;
    SHAPE ABUTMENT ;
    PORT
      LAYER M3 ;
      RECT 0 58.415 0.07 58.485 ;
    END
  END rw0_wd_in[75]
  PIN rw0_wd_in[76]
    DIRECTION INPUT ;
    USE SIGNAL ;
    SHAPE ABUTMENT ;
    PORT
      LAYER M3 ;
      RECT 0 58.835 0.07 58.905 ;
    END
  END rw0_wd_in[76]
  PIN rw0_wd_in[77]
    DIRECTION INPUT ;
    USE SIGNAL ;
    SHAPE ABUTMENT ;
    PORT
      LAYER M3 ;
      RECT 0 59.255 0.07 59.325 ;
    END
  END rw0_wd_in[77]
  PIN rw0_wd_in[78]
    DIRECTION INPUT ;
    USE SIGNAL ;
    SHAPE ABUTMENT ;
    PORT
      LAYER M3 ;
      RECT 0 59.675 0.07 59.745 ;
    END
  END rw0_wd_in[78]
  PIN rw0_wd_in[79]
    DIRECTION INPUT ;
    USE SIGNAL ;
    SHAPE ABUTMENT ;
    PORT
      LAYER M3 ;
      RECT 0 60.095 0.07 60.165 ;
    END
  END rw0_wd_in[79]
  PIN rw0_wd_in[80]
    DIRECTION INPUT ;
    USE SIGNAL ;
    SHAPE ABUTMENT ;
    PORT
      LAYER M3 ;
      RECT 0 60.515 0.07 60.585 ;
    END
  END rw0_wd_in[80]
  PIN rw0_wd_in[81]
    DIRECTION INPUT ;
    USE SIGNAL ;
    SHAPE ABUTMENT ;
    PORT
      LAYER M3 ;
      RECT 0 60.935 0.07 61.005 ;
    END
  END rw0_wd_in[81]
  PIN rw0_wd_in[82]
    DIRECTION INPUT ;
    USE SIGNAL ;
    SHAPE ABUTMENT ;
    PORT
      LAYER M3 ;
      RECT 0 61.355 0.07 61.425 ;
    END
  END rw0_wd_in[82]
  PIN rw0_wd_in[83]
    DIRECTION INPUT ;
    USE SIGNAL ;
    SHAPE ABUTMENT ;
    PORT
      LAYER M3 ;
      RECT 0 61.775 0.07 61.845 ;
    END
  END rw0_wd_in[83]
  PIN rw0_wd_in[84]
    DIRECTION INPUT ;
    USE SIGNAL ;
    SHAPE ABUTMENT ;
    PORT
      LAYER M3 ;
      RECT 0 62.195 0.07 62.265 ;
    END
  END rw0_wd_in[84]
  PIN rw0_wd_in[85]
    DIRECTION INPUT ;
    USE SIGNAL ;
    SHAPE ABUTMENT ;
    PORT
      LAYER M3 ;
      RECT 0 62.615 0.07 62.685 ;
    END
  END rw0_wd_in[85]
  PIN rw0_wd_in[86]
    DIRECTION INPUT ;
    USE SIGNAL ;
    SHAPE ABUTMENT ;
    PORT
      LAYER M3 ;
      RECT 0 63.035 0.07 63.105 ;
    END
  END rw0_wd_in[86]
  PIN rw0_wd_in[87]
    DIRECTION INPUT ;
    USE SIGNAL ;
    SHAPE ABUTMENT ;
    PORT
      LAYER M3 ;
      RECT 0 63.455 0.07 63.525 ;
    END
  END rw0_wd_in[87]
  PIN rw0_wd_in[88]
    DIRECTION INPUT ;
    USE SIGNAL ;
    SHAPE ABUTMENT ;
    PORT
      LAYER M3 ;
      RECT 0 63.875 0.07 63.945 ;
    END
  END rw0_wd_in[88]
  PIN rw0_wd_in[89]
    DIRECTION INPUT ;
    USE SIGNAL ;
    SHAPE ABUTMENT ;
    PORT
      LAYER M3 ;
      RECT 0 64.295 0.07 64.365 ;
    END
  END rw0_wd_in[89]
  PIN rw0_wd_in[90]
    DIRECTION INPUT ;
    USE SIGNAL ;
    SHAPE ABUTMENT ;
    PORT
      LAYER M3 ;
      RECT 0 64.715 0.07 64.785 ;
    END
  END rw0_wd_in[90]
  PIN rw0_wd_in[91]
    DIRECTION INPUT ;
    USE SIGNAL ;
    SHAPE ABUTMENT ;
    PORT
      LAYER M3 ;
      RECT 0 65.135 0.07 65.205 ;
    END
  END rw0_wd_in[91]
  PIN rw0_wd_in[92]
    DIRECTION INPUT ;
    USE SIGNAL ;
    SHAPE ABUTMENT ;
    PORT
      LAYER M3 ;
      RECT 0 65.555 0.07 65.625 ;
    END
  END rw0_wd_in[92]
  PIN rw0_wd_in[93]
    DIRECTION INPUT ;
    USE SIGNAL ;
    SHAPE ABUTMENT ;
    PORT
      LAYER M3 ;
      RECT 0 65.975 0.07 66.045 ;
    END
  END rw0_wd_in[93]
  PIN rw0_wd_in[94]
    DIRECTION INPUT ;
    USE SIGNAL ;
    SHAPE ABUTMENT ;
    PORT
      LAYER M3 ;
      RECT 0 66.395 0.07 66.465 ;
    END
  END rw0_wd_in[94]
  PIN rw0_wd_in[95]
    DIRECTION INPUT ;
    USE SIGNAL ;
    SHAPE ABUTMENT ;
    PORT
      LAYER M3 ;
      RECT 0 66.815 0.07 66.885 ;
    END
  END rw0_wd_in[95]
  PIN rw0_wd_in[96]
    DIRECTION INPUT ;
    USE SIGNAL ;
    SHAPE ABUTMENT ;
    PORT
      LAYER M3 ;
      RECT 0 67.235 0.07 67.305 ;
    END
  END rw0_wd_in[96]
  PIN rw0_wd_in[97]
    DIRECTION INPUT ;
    USE SIGNAL ;
    SHAPE ABUTMENT ;
    PORT
      LAYER M3 ;
      RECT 0 67.655 0.07 67.725 ;
    END
  END rw0_wd_in[97]
  PIN rw0_wd_in[98]
    DIRECTION INPUT ;
    USE SIGNAL ;
    SHAPE ABUTMENT ;
    PORT
      LAYER M3 ;
      RECT 0 68.075 0.07 68.145 ;
    END
  END rw0_wd_in[98]
  PIN rw0_wd_in[99]
    DIRECTION INPUT ;
    USE SIGNAL ;
    SHAPE ABUTMENT ;
    PORT
      LAYER M3 ;
      RECT 0 68.495 0.07 68.565 ;
    END
  END rw0_wd_in[99]
  PIN rw0_wd_in[100]
    DIRECTION INPUT ;
    USE SIGNAL ;
    SHAPE ABUTMENT ;
    PORT
      LAYER M3 ;
      RECT 0 68.915 0.07 68.985 ;
    END
  END rw0_wd_in[100]
  PIN rw0_wd_in[101]
    DIRECTION INPUT ;
    USE SIGNAL ;
    SHAPE ABUTMENT ;
    PORT
      LAYER M3 ;
      RECT 0 69.335 0.07 69.405 ;
    END
  END rw0_wd_in[101]
  PIN rw0_wd_in[102]
    DIRECTION INPUT ;
    USE SIGNAL ;
    SHAPE ABUTMENT ;
    PORT
      LAYER M3 ;
      RECT 0 69.755 0.07 69.825 ;
    END
  END rw0_wd_in[102]
  PIN rw0_wd_in[103]
    DIRECTION INPUT ;
    USE SIGNAL ;
    SHAPE ABUTMENT ;
    PORT
      LAYER M3 ;
      RECT 0 70.175 0.07 70.245 ;
    END
  END rw0_wd_in[103]
  PIN rw0_wd_in[104]
    DIRECTION INPUT ;
    USE SIGNAL ;
    SHAPE ABUTMENT ;
    PORT
      LAYER M3 ;
      RECT 0 70.595 0.07 70.665 ;
    END
  END rw0_wd_in[104]
  PIN rw0_wd_in[105]
    DIRECTION INPUT ;
    USE SIGNAL ;
    SHAPE ABUTMENT ;
    PORT
      LAYER M3 ;
      RECT 0 71.015 0.07 71.085 ;
    END
  END rw0_wd_in[105]
  PIN rw0_wd_in[106]
    DIRECTION INPUT ;
    USE SIGNAL ;
    SHAPE ABUTMENT ;
    PORT
      LAYER M3 ;
      RECT 0 71.435 0.07 71.505 ;
    END
  END rw0_wd_in[106]
  PIN rw0_wd_in[107]
    DIRECTION INPUT ;
    USE SIGNAL ;
    SHAPE ABUTMENT ;
    PORT
      LAYER M3 ;
      RECT 0 71.855 0.07 71.925 ;
    END
  END rw0_wd_in[107]
  PIN rw0_wd_in[108]
    DIRECTION INPUT ;
    USE SIGNAL ;
    SHAPE ABUTMENT ;
    PORT
      LAYER M3 ;
      RECT 0 72.275 0.07 72.345 ;
    END
  END rw0_wd_in[108]
  PIN rw0_wd_in[109]
    DIRECTION INPUT ;
    USE SIGNAL ;
    SHAPE ABUTMENT ;
    PORT
      LAYER M3 ;
      RECT 0 72.695 0.07 72.765 ;
    END
  END rw0_wd_in[109]
  PIN rw0_wd_in[110]
    DIRECTION INPUT ;
    USE SIGNAL ;
    SHAPE ABUTMENT ;
    PORT
      LAYER M3 ;
      RECT 0 73.115 0.07 73.185 ;
    END
  END rw0_wd_in[110]
  PIN rw0_wd_in[111]
    DIRECTION INPUT ;
    USE SIGNAL ;
    SHAPE ABUTMENT ;
    PORT
      LAYER M3 ;
      RECT 0 73.535 0.07 73.605 ;
    END
  END rw0_wd_in[111]
  PIN rw0_wd_in[112]
    DIRECTION INPUT ;
    USE SIGNAL ;
    SHAPE ABUTMENT ;
    PORT
      LAYER M3 ;
      RECT 0 73.955 0.07 74.025 ;
    END
  END rw0_wd_in[112]
  PIN rw0_wd_in[113]
    DIRECTION INPUT ;
    USE SIGNAL ;
    SHAPE ABUTMENT ;
    PORT
      LAYER M3 ;
      RECT 0 74.375 0.07 74.445 ;
    END
  END rw0_wd_in[113]
  PIN rw0_wd_in[114]
    DIRECTION INPUT ;
    USE SIGNAL ;
    SHAPE ABUTMENT ;
    PORT
      LAYER M3 ;
      RECT 0 74.795 0.07 74.865 ;
    END
  END rw0_wd_in[114]
  PIN rw0_wd_in[115]
    DIRECTION INPUT ;
    USE SIGNAL ;
    SHAPE ABUTMENT ;
    PORT
      LAYER M3 ;
      RECT 0 75.215 0.07 75.285 ;
    END
  END rw0_wd_in[115]
  PIN rw0_wd_in[116]
    DIRECTION INPUT ;
    USE SIGNAL ;
    SHAPE ABUTMENT ;
    PORT
      LAYER M3 ;
      RECT 0 75.635 0.07 75.705 ;
    END
  END rw0_wd_in[116]
  PIN rw0_wd_in[117]
    DIRECTION INPUT ;
    USE SIGNAL ;
    SHAPE ABUTMENT ;
    PORT
      LAYER M3 ;
      RECT 0 76.055 0.07 76.125 ;
    END
  END rw0_wd_in[117]
  PIN rw0_wd_in[118]
    DIRECTION INPUT ;
    USE SIGNAL ;
    SHAPE ABUTMENT ;
    PORT
      LAYER M3 ;
      RECT 0 76.475 0.07 76.545 ;
    END
  END rw0_wd_in[118]
  PIN rw0_wd_in[119]
    DIRECTION INPUT ;
    USE SIGNAL ;
    SHAPE ABUTMENT ;
    PORT
      LAYER M3 ;
      RECT 0 76.895 0.07 76.965 ;
    END
  END rw0_wd_in[119]
  PIN rw0_wd_in[120]
    DIRECTION INPUT ;
    USE SIGNAL ;
    SHAPE ABUTMENT ;
    PORT
      LAYER M3 ;
      RECT 0 77.315 0.07 77.385 ;
    END
  END rw0_wd_in[120]
  PIN rw0_wd_in[121]
    DIRECTION INPUT ;
    USE SIGNAL ;
    SHAPE ABUTMENT ;
    PORT
      LAYER M3 ;
      RECT 0 77.735 0.07 77.805 ;
    END
  END rw0_wd_in[121]
  PIN rw0_wd_in[122]
    DIRECTION INPUT ;
    USE SIGNAL ;
    SHAPE ABUTMENT ;
    PORT
      LAYER M3 ;
      RECT 0 78.155 0.07 78.225 ;
    END
  END rw0_wd_in[122]
  PIN rw0_wd_in[123]
    DIRECTION INPUT ;
    USE SIGNAL ;
    SHAPE ABUTMENT ;
    PORT
      LAYER M3 ;
      RECT 0 78.575 0.07 78.645 ;
    END
  END rw0_wd_in[123]
  PIN rw0_wd_in[124]
    DIRECTION INPUT ;
    USE SIGNAL ;
    SHAPE ABUTMENT ;
    PORT
      LAYER M3 ;
      RECT 0 78.995 0.07 79.065 ;
    END
  END rw0_wd_in[124]
  PIN rw0_wd_in[125]
    DIRECTION INPUT ;
    USE SIGNAL ;
    SHAPE ABUTMENT ;
    PORT
      LAYER M3 ;
      RECT 0 79.415 0.07 79.485 ;
    END
  END rw0_wd_in[125]
  PIN rw0_wd_in[126]
    DIRECTION INPUT ;
    USE SIGNAL ;
    SHAPE ABUTMENT ;
    PORT
      LAYER M3 ;
      RECT 0 79.835 0.07 79.905 ;
    END
  END rw0_wd_in[126]
  PIN rw0_wd_in[127]
    DIRECTION INPUT ;
    USE SIGNAL ;
    SHAPE ABUTMENT ;
    PORT
      LAYER M3 ;
      RECT 0 80.255 0.07 80.325 ;
    END
  END rw0_wd_in[127]
  PIN rw0_wd_in[128]
    DIRECTION INPUT ;
    USE SIGNAL ;
    SHAPE ABUTMENT ;
    PORT
      LAYER M3 ;
      RECT 0 80.675 0.07 80.745 ;
    END
  END rw0_wd_in[128]
  PIN rw0_wd_in[129]
    DIRECTION INPUT ;
    USE SIGNAL ;
    SHAPE ABUTMENT ;
    PORT
      LAYER M3 ;
      RECT 0 81.095 0.07 81.165 ;
    END
  END rw0_wd_in[129]
  PIN rw0_wd_in[130]
    DIRECTION INPUT ;
    USE SIGNAL ;
    SHAPE ABUTMENT ;
    PORT
      LAYER M3 ;
      RECT 0 81.515 0.07 81.585 ;
    END
  END rw0_wd_in[130]
  PIN rw0_wd_in[131]
    DIRECTION INPUT ;
    USE SIGNAL ;
    SHAPE ABUTMENT ;
    PORT
      LAYER M3 ;
      RECT 0 81.935 0.07 82.005 ;
    END
  END rw0_wd_in[131]
  PIN rw0_wd_in[132]
    DIRECTION INPUT ;
    USE SIGNAL ;
    SHAPE ABUTMENT ;
    PORT
      LAYER M3 ;
      RECT 0 82.355 0.07 82.425 ;
    END
  END rw0_wd_in[132]
  PIN rw0_wd_in[133]
    DIRECTION INPUT ;
    USE SIGNAL ;
    SHAPE ABUTMENT ;
    PORT
      LAYER M3 ;
      RECT 0 82.775 0.07 82.845 ;
    END
  END rw0_wd_in[133]
  PIN rw0_wd_in[134]
    DIRECTION INPUT ;
    USE SIGNAL ;
    SHAPE ABUTMENT ;
    PORT
      LAYER M3 ;
      RECT 0 83.195 0.07 83.265 ;
    END
  END rw0_wd_in[134]
  PIN rw0_wd_in[135]
    DIRECTION INPUT ;
    USE SIGNAL ;
    SHAPE ABUTMENT ;
    PORT
      LAYER M3 ;
      RECT 0 83.615 0.07 83.685 ;
    END
  END rw0_wd_in[135]
  PIN rw0_wd_in[136]
    DIRECTION INPUT ;
    USE SIGNAL ;
    SHAPE ABUTMENT ;
    PORT
      LAYER M3 ;
      RECT 0 84.035 0.07 84.105 ;
    END
  END rw0_wd_in[136]
  PIN rw0_wd_in[137]
    DIRECTION INPUT ;
    USE SIGNAL ;
    SHAPE ABUTMENT ;
    PORT
      LAYER M3 ;
      RECT 0 84.455 0.07 84.525 ;
    END
  END rw0_wd_in[137]
  PIN rw0_wd_in[138]
    DIRECTION INPUT ;
    USE SIGNAL ;
    SHAPE ABUTMENT ;
    PORT
      LAYER M3 ;
      RECT 0 84.875 0.07 84.945 ;
    END
  END rw0_wd_in[138]
  PIN rw0_wd_in[139]
    DIRECTION INPUT ;
    USE SIGNAL ;
    SHAPE ABUTMENT ;
    PORT
      LAYER M3 ;
      RECT 0 85.295 0.07 85.365 ;
    END
  END rw0_wd_in[139]
  PIN rw0_wd_in[140]
    DIRECTION INPUT ;
    USE SIGNAL ;
    SHAPE ABUTMENT ;
    PORT
      LAYER M3 ;
      RECT 0 85.715 0.07 85.785 ;
    END
  END rw0_wd_in[140]
  PIN rw0_wd_in[141]
    DIRECTION INPUT ;
    USE SIGNAL ;
    SHAPE ABUTMENT ;
    PORT
      LAYER M3 ;
      RECT 0 86.135 0.07 86.205 ;
    END
  END rw0_wd_in[141]
  PIN rw0_wd_in[142]
    DIRECTION INPUT ;
    USE SIGNAL ;
    SHAPE ABUTMENT ;
    PORT
      LAYER M3 ;
      RECT 0 86.555 0.07 86.625 ;
    END
  END rw0_wd_in[142]
  PIN rw0_wd_in[143]
    DIRECTION INPUT ;
    USE SIGNAL ;
    SHAPE ABUTMENT ;
    PORT
      LAYER M3 ;
      RECT 0 86.975 0.07 87.045 ;
    END
  END rw0_wd_in[143]
  PIN rw0_wd_in[144]
    DIRECTION INPUT ;
    USE SIGNAL ;
    SHAPE ABUTMENT ;
    PORT
      LAYER M3 ;
      RECT 0 87.395 0.07 87.465 ;
    END
  END rw0_wd_in[144]
  PIN rw0_wd_in[145]
    DIRECTION INPUT ;
    USE SIGNAL ;
    SHAPE ABUTMENT ;
    PORT
      LAYER M3 ;
      RECT 0 87.815 0.07 87.885 ;
    END
  END rw0_wd_in[145]
  PIN rw0_wd_in[146]
    DIRECTION INPUT ;
    USE SIGNAL ;
    SHAPE ABUTMENT ;
    PORT
      LAYER M3 ;
      RECT 0 88.235 0.07 88.305 ;
    END
  END rw0_wd_in[146]
  PIN rw0_wd_in[147]
    DIRECTION INPUT ;
    USE SIGNAL ;
    SHAPE ABUTMENT ;
    PORT
      LAYER M3 ;
      RECT 0 88.655 0.07 88.725 ;
    END
  END rw0_wd_in[147]
  PIN rw0_wd_in[148]
    DIRECTION INPUT ;
    USE SIGNAL ;
    SHAPE ABUTMENT ;
    PORT
      LAYER M3 ;
      RECT 0 89.075 0.07 89.145 ;
    END
  END rw0_wd_in[148]
  PIN rw0_wd_in[149]
    DIRECTION INPUT ;
    USE SIGNAL ;
    SHAPE ABUTMENT ;
    PORT
      LAYER M3 ;
      RECT 0 89.495 0.07 89.565 ;
    END
  END rw0_wd_in[149]
  PIN rw0_wd_in[150]
    DIRECTION INPUT ;
    USE SIGNAL ;
    SHAPE ABUTMENT ;
    PORT
      LAYER M3 ;
      RECT 0 89.915 0.07 89.985 ;
    END
  END rw0_wd_in[150]
  PIN rw0_wd_in[151]
    DIRECTION INPUT ;
    USE SIGNAL ;
    SHAPE ABUTMENT ;
    PORT
      LAYER M3 ;
      RECT 0 90.335 0.07 90.405 ;
    END
  END rw0_wd_in[151]
  PIN rw0_wd_in[152]
    DIRECTION INPUT ;
    USE SIGNAL ;
    SHAPE ABUTMENT ;
    PORT
      LAYER M3 ;
      RECT 0 90.755 0.07 90.825 ;
    END
  END rw0_wd_in[152]
  PIN rw0_wd_in[153]
    DIRECTION INPUT ;
    USE SIGNAL ;
    SHAPE ABUTMENT ;
    PORT
      LAYER M3 ;
      RECT 0 91.175 0.07 91.245 ;
    END
  END rw0_wd_in[153]
  PIN rw0_wd_in[154]
    DIRECTION INPUT ;
    USE SIGNAL ;
    SHAPE ABUTMENT ;
    PORT
      LAYER M3 ;
      RECT 0 91.595 0.07 91.665 ;
    END
  END rw0_wd_in[154]
  PIN rw0_wd_in[155]
    DIRECTION INPUT ;
    USE SIGNAL ;
    SHAPE ABUTMENT ;
    PORT
      LAYER M3 ;
      RECT 0 92.015 0.07 92.085 ;
    END
  END rw0_wd_in[155]
  PIN rw0_wd_in[156]
    DIRECTION INPUT ;
    USE SIGNAL ;
    SHAPE ABUTMENT ;
    PORT
      LAYER M3 ;
      RECT 0 92.435 0.07 92.505 ;
    END
  END rw0_wd_in[156]
  PIN rw0_wd_in[157]
    DIRECTION INPUT ;
    USE SIGNAL ;
    SHAPE ABUTMENT ;
    PORT
      LAYER M3 ;
      RECT 0 92.855 0.07 92.925 ;
    END
  END rw0_wd_in[157]
  PIN rw0_wd_in[158]
    DIRECTION INPUT ;
    USE SIGNAL ;
    SHAPE ABUTMENT ;
    PORT
      LAYER M3 ;
      RECT 0 93.275 0.07 93.345 ;
    END
  END rw0_wd_in[158]
  PIN rw0_wd_in[159]
    DIRECTION INPUT ;
    USE SIGNAL ;
    SHAPE ABUTMENT ;
    PORT
      LAYER M3 ;
      RECT 0 93.695 0.07 93.765 ;
    END
  END rw0_wd_in[159]
  PIN rw0_wd_in[160]
    DIRECTION INPUT ;
    USE SIGNAL ;
    SHAPE ABUTMENT ;
    PORT
      LAYER M3 ;
      RECT 0 94.115 0.07 94.185 ;
    END
  END rw0_wd_in[160]
  PIN rw0_wd_in[161]
    DIRECTION INPUT ;
    USE SIGNAL ;
    SHAPE ABUTMENT ;
    PORT
      LAYER M3 ;
      RECT 0 94.535 0.07 94.605 ;
    END
  END rw0_wd_in[161]
  PIN rw0_wd_in[162]
    DIRECTION INPUT ;
    USE SIGNAL ;
    SHAPE ABUTMENT ;
    PORT
      LAYER M3 ;
      RECT 0 94.955 0.07 95.025 ;
    END
  END rw0_wd_in[162]
  PIN rw0_wd_in[163]
    DIRECTION INPUT ;
    USE SIGNAL ;
    SHAPE ABUTMENT ;
    PORT
      LAYER M3 ;
      RECT 0 95.375 0.07 95.445 ;
    END
  END rw0_wd_in[163]
  PIN rw0_wd_in[164]
    DIRECTION INPUT ;
    USE SIGNAL ;
    SHAPE ABUTMENT ;
    PORT
      LAYER M3 ;
      RECT 0 95.795 0.07 95.865 ;
    END
  END rw0_wd_in[164]
  PIN rw0_wd_in[165]
    DIRECTION INPUT ;
    USE SIGNAL ;
    SHAPE ABUTMENT ;
    PORT
      LAYER M3 ;
      RECT 0 96.215 0.07 96.285 ;
    END
  END rw0_wd_in[165]
  PIN rw0_wd_in[166]
    DIRECTION INPUT ;
    USE SIGNAL ;
    SHAPE ABUTMENT ;
    PORT
      LAYER M3 ;
      RECT 0 96.635 0.07 96.705 ;
    END
  END rw0_wd_in[166]
  PIN rw0_wd_in[167]
    DIRECTION INPUT ;
    USE SIGNAL ;
    SHAPE ABUTMENT ;
    PORT
      LAYER M3 ;
      RECT 0 97.055 0.07 97.125 ;
    END
  END rw0_wd_in[167]
  PIN rw0_wd_in[168]
    DIRECTION INPUT ;
    USE SIGNAL ;
    SHAPE ABUTMENT ;
    PORT
      LAYER M3 ;
      RECT 0 97.475 0.07 97.545 ;
    END
  END rw0_wd_in[168]
  PIN rw0_wd_in[169]
    DIRECTION INPUT ;
    USE SIGNAL ;
    SHAPE ABUTMENT ;
    PORT
      LAYER M3 ;
      RECT 0 97.895 0.07 97.965 ;
    END
  END rw0_wd_in[169]
  PIN rw0_wd_in[170]
    DIRECTION INPUT ;
    USE SIGNAL ;
    SHAPE ABUTMENT ;
    PORT
      LAYER M3 ;
      RECT 0 98.315 0.07 98.385 ;
    END
  END rw0_wd_in[170]
  PIN rw0_wd_in[171]
    DIRECTION INPUT ;
    USE SIGNAL ;
    SHAPE ABUTMENT ;
    PORT
      LAYER M3 ;
      RECT 0 98.735 0.07 98.805 ;
    END
  END rw0_wd_in[171]
  PIN rw0_wd_in[172]
    DIRECTION INPUT ;
    USE SIGNAL ;
    SHAPE ABUTMENT ;
    PORT
      LAYER M3 ;
      RECT 0 99.155 0.07 99.225 ;
    END
  END rw0_wd_in[172]
  PIN rw0_wd_in[173]
    DIRECTION INPUT ;
    USE SIGNAL ;
    SHAPE ABUTMENT ;
    PORT
      LAYER M3 ;
      RECT 0 99.575 0.07 99.645 ;
    END
  END rw0_wd_in[173]
  PIN rw0_wd_in[174]
    DIRECTION INPUT ;
    USE SIGNAL ;
    SHAPE ABUTMENT ;
    PORT
      LAYER M3 ;
      RECT 0 99.995 0.07 100.065 ;
    END
  END rw0_wd_in[174]
  PIN rw0_wd_in[175]
    DIRECTION INPUT ;
    USE SIGNAL ;
    SHAPE ABUTMENT ;
    PORT
      LAYER M3 ;
      RECT 0 100.415 0.07 100.485 ;
    END
  END rw0_wd_in[175]
  PIN rw0_wd_in[176]
    DIRECTION INPUT ;
    USE SIGNAL ;
    SHAPE ABUTMENT ;
    PORT
      LAYER M3 ;
      RECT 0 100.835 0.07 100.905 ;
    END
  END rw0_wd_in[176]
  PIN rw0_wd_in[177]
    DIRECTION INPUT ;
    USE SIGNAL ;
    SHAPE ABUTMENT ;
    PORT
      LAYER M3 ;
      RECT 0 101.255 0.07 101.325 ;
    END
  END rw0_wd_in[177]
  PIN rw0_wd_in[178]
    DIRECTION INPUT ;
    USE SIGNAL ;
    SHAPE ABUTMENT ;
    PORT
      LAYER M3 ;
      RECT 0 101.675 0.07 101.745 ;
    END
  END rw0_wd_in[178]
  PIN rw0_wd_in[179]
    DIRECTION INPUT ;
    USE SIGNAL ;
    SHAPE ABUTMENT ;
    PORT
      LAYER M3 ;
      RECT 0 102.095 0.07 102.165 ;
    END
  END rw0_wd_in[179]
  PIN rw0_wd_in[180]
    DIRECTION INPUT ;
    USE SIGNAL ;
    SHAPE ABUTMENT ;
    PORT
      LAYER M3 ;
      RECT 0 102.515 0.07 102.585 ;
    END
  END rw0_wd_in[180]
  PIN rw0_wd_in[181]
    DIRECTION INPUT ;
    USE SIGNAL ;
    SHAPE ABUTMENT ;
    PORT
      LAYER M3 ;
      RECT 0 102.935 0.07 103.005 ;
    END
  END rw0_wd_in[181]
  PIN rw0_wd_in[182]
    DIRECTION INPUT ;
    USE SIGNAL ;
    SHAPE ABUTMENT ;
    PORT
      LAYER M3 ;
      RECT 0 103.355 0.07 103.425 ;
    END
  END rw0_wd_in[182]
  PIN rw0_wd_in[183]
    DIRECTION INPUT ;
    USE SIGNAL ;
    SHAPE ABUTMENT ;
    PORT
      LAYER M3 ;
      RECT 0 103.775 0.07 103.845 ;
    END
  END rw0_wd_in[183]
  PIN rw0_wd_in[184]
    DIRECTION INPUT ;
    USE SIGNAL ;
    SHAPE ABUTMENT ;
    PORT
      LAYER M3 ;
      RECT 0 104.195 0.07 104.265 ;
    END
  END rw0_wd_in[184]
  PIN rw0_wd_in[185]
    DIRECTION INPUT ;
    USE SIGNAL ;
    SHAPE ABUTMENT ;
    PORT
      LAYER M3 ;
      RECT 0 104.615 0.07 104.685 ;
    END
  END rw0_wd_in[185]
  PIN rw0_wd_in[186]
    DIRECTION INPUT ;
    USE SIGNAL ;
    SHAPE ABUTMENT ;
    PORT
      LAYER M3 ;
      RECT 0 105.035 0.07 105.105 ;
    END
  END rw0_wd_in[186]
  PIN rw0_wd_in[187]
    DIRECTION INPUT ;
    USE SIGNAL ;
    SHAPE ABUTMENT ;
    PORT
      LAYER M3 ;
      RECT 0 105.455 0.07 105.525 ;
    END
  END rw0_wd_in[187]
  PIN rw0_wd_in[188]
    DIRECTION INPUT ;
    USE SIGNAL ;
    SHAPE ABUTMENT ;
    PORT
      LAYER M3 ;
      RECT 0 105.875 0.07 105.945 ;
    END
  END rw0_wd_in[188]
  PIN rw0_wd_in[189]
    DIRECTION INPUT ;
    USE SIGNAL ;
    SHAPE ABUTMENT ;
    PORT
      LAYER M3 ;
      RECT 0 106.295 0.07 106.365 ;
    END
  END rw0_wd_in[189]
  PIN rw0_wd_in[190]
    DIRECTION INPUT ;
    USE SIGNAL ;
    SHAPE ABUTMENT ;
    PORT
      LAYER M3 ;
      RECT 0 106.715 0.07 106.785 ;
    END
  END rw0_wd_in[190]
  PIN rw0_wd_in[191]
    DIRECTION INPUT ;
    USE SIGNAL ;
    SHAPE ABUTMENT ;
    PORT
      LAYER M3 ;
      RECT 0 107.135 0.07 107.205 ;
    END
  END rw0_wd_in[191]
  PIN rw0_wd_in[192]
    DIRECTION INPUT ;
    USE SIGNAL ;
    SHAPE ABUTMENT ;
    PORT
      LAYER M3 ;
      RECT 0 107.555 0.07 107.625 ;
    END
  END rw0_wd_in[192]
  PIN rw0_wd_in[193]
    DIRECTION INPUT ;
    USE SIGNAL ;
    SHAPE ABUTMENT ;
    PORT
      LAYER M3 ;
      RECT 0 107.975 0.07 108.045 ;
    END
  END rw0_wd_in[193]
  PIN rw0_wd_in[194]
    DIRECTION INPUT ;
    USE SIGNAL ;
    SHAPE ABUTMENT ;
    PORT
      LAYER M3 ;
      RECT 0 108.395 0.07 108.465 ;
    END
  END rw0_wd_in[194]
  PIN rw0_wd_in[195]
    DIRECTION INPUT ;
    USE SIGNAL ;
    SHAPE ABUTMENT ;
    PORT
      LAYER M3 ;
      RECT 0 108.815 0.07 108.885 ;
    END
  END rw0_wd_in[195]
  PIN rw0_wd_in[196]
    DIRECTION INPUT ;
    USE SIGNAL ;
    SHAPE ABUTMENT ;
    PORT
      LAYER M3 ;
      RECT 0 109.235 0.07 109.305 ;
    END
  END rw0_wd_in[196]
  PIN rw0_wd_in[197]
    DIRECTION INPUT ;
    USE SIGNAL ;
    SHAPE ABUTMENT ;
    PORT
      LAYER M3 ;
      RECT 0 109.655 0.07 109.725 ;
    END
  END rw0_wd_in[197]
  PIN rw0_wd_in[198]
    DIRECTION INPUT ;
    USE SIGNAL ;
    SHAPE ABUTMENT ;
    PORT
      LAYER M3 ;
      RECT 0 110.075 0.07 110.145 ;
    END
  END rw0_wd_in[198]
  PIN rw0_wd_in[199]
    DIRECTION INPUT ;
    USE SIGNAL ;
    SHAPE ABUTMENT ;
    PORT
      LAYER M3 ;
      RECT 0 110.495 0.07 110.565 ;
    END
  END rw0_wd_in[199]
  PIN rw0_wd_in[200]
    DIRECTION INPUT ;
    USE SIGNAL ;
    SHAPE ABUTMENT ;
    PORT
      LAYER M3 ;
      RECT 0 110.915 0.07 110.985 ;
    END
  END rw0_wd_in[200]
  PIN rw0_wd_in[201]
    DIRECTION INPUT ;
    USE SIGNAL ;
    SHAPE ABUTMENT ;
    PORT
      LAYER M3 ;
      RECT 0 111.335 0.07 111.405 ;
    END
  END rw0_wd_in[201]
  PIN rw0_wd_in[202]
    DIRECTION INPUT ;
    USE SIGNAL ;
    SHAPE ABUTMENT ;
    PORT
      LAYER M3 ;
      RECT 0 111.755 0.07 111.825 ;
    END
  END rw0_wd_in[202]
  PIN rw0_wd_in[203]
    DIRECTION INPUT ;
    USE SIGNAL ;
    SHAPE ABUTMENT ;
    PORT
      LAYER M3 ;
      RECT 0 112.175 0.07 112.245 ;
    END
  END rw0_wd_in[203]
  PIN rw0_wd_in[204]
    DIRECTION INPUT ;
    USE SIGNAL ;
    SHAPE ABUTMENT ;
    PORT
      LAYER M3 ;
      RECT 0 112.595 0.07 112.665 ;
    END
  END rw0_wd_in[204]
  PIN rw0_wd_in[205]
    DIRECTION INPUT ;
    USE SIGNAL ;
    SHAPE ABUTMENT ;
    PORT
      LAYER M3 ;
      RECT 0 113.015 0.07 113.085 ;
    END
  END rw0_wd_in[205]
  PIN rw0_wd_in[206]
    DIRECTION INPUT ;
    USE SIGNAL ;
    SHAPE ABUTMENT ;
    PORT
      LAYER M3 ;
      RECT 0 113.435 0.07 113.505 ;
    END
  END rw0_wd_in[206]
  PIN rw0_wd_in[207]
    DIRECTION INPUT ;
    USE SIGNAL ;
    SHAPE ABUTMENT ;
    PORT
      LAYER M3 ;
      RECT 0 113.855 0.07 113.925 ;
    END
  END rw0_wd_in[207]
  PIN rw0_wd_in[208]
    DIRECTION INPUT ;
    USE SIGNAL ;
    SHAPE ABUTMENT ;
    PORT
      LAYER M3 ;
      RECT 0 114.275 0.07 114.345 ;
    END
  END rw0_wd_in[208]
  PIN rw0_wd_in[209]
    DIRECTION INPUT ;
    USE SIGNAL ;
    SHAPE ABUTMENT ;
    PORT
      LAYER M3 ;
      RECT 0 114.695 0.07 114.765 ;
    END
  END rw0_wd_in[209]
  PIN rw0_wd_in[210]
    DIRECTION INPUT ;
    USE SIGNAL ;
    SHAPE ABUTMENT ;
    PORT
      LAYER M3 ;
      RECT 0 115.115 0.07 115.185 ;
    END
  END rw0_wd_in[210]
  PIN rw0_wd_in[211]
    DIRECTION INPUT ;
    USE SIGNAL ;
    SHAPE ABUTMENT ;
    PORT
      LAYER M3 ;
      RECT 0 115.535 0.07 115.605 ;
    END
  END rw0_wd_in[211]
  PIN rw0_wd_in[212]
    DIRECTION INPUT ;
    USE SIGNAL ;
    SHAPE ABUTMENT ;
    PORT
      LAYER M3 ;
      RECT 0 115.955 0.07 116.025 ;
    END
  END rw0_wd_in[212]
  PIN rw0_wd_in[213]
    DIRECTION INPUT ;
    USE SIGNAL ;
    SHAPE ABUTMENT ;
    PORT
      LAYER M3 ;
      RECT 0 116.375 0.07 116.445 ;
    END
  END rw0_wd_in[213]
  PIN rw0_wd_in[214]
    DIRECTION INPUT ;
    USE SIGNAL ;
    SHAPE ABUTMENT ;
    PORT
      LAYER M3 ;
      RECT 0 116.795 0.07 116.865 ;
    END
  END rw0_wd_in[214]
  PIN rw0_wd_in[215]
    DIRECTION INPUT ;
    USE SIGNAL ;
    SHAPE ABUTMENT ;
    PORT
      LAYER M3 ;
      RECT 0 117.215 0.07 117.285 ;
    END
  END rw0_wd_in[215]
  PIN rw0_wd_in[216]
    DIRECTION INPUT ;
    USE SIGNAL ;
    SHAPE ABUTMENT ;
    PORT
      LAYER M3 ;
      RECT 0 117.635 0.07 117.705 ;
    END
  END rw0_wd_in[216]
  PIN rw0_wd_in[217]
    DIRECTION INPUT ;
    USE SIGNAL ;
    SHAPE ABUTMENT ;
    PORT
      LAYER M3 ;
      RECT 0 118.055 0.07 118.125 ;
    END
  END rw0_wd_in[217]
  PIN rw0_wd_in[218]
    DIRECTION INPUT ;
    USE SIGNAL ;
    SHAPE ABUTMENT ;
    PORT
      LAYER M3 ;
      RECT 0 118.475 0.07 118.545 ;
    END
  END rw0_wd_in[218]
  PIN rw0_wd_in[219]
    DIRECTION INPUT ;
    USE SIGNAL ;
    SHAPE ABUTMENT ;
    PORT
      LAYER M3 ;
      RECT 0 118.895 0.07 118.965 ;
    END
  END rw0_wd_in[219]
  PIN rw0_wd_in[220]
    DIRECTION INPUT ;
    USE SIGNAL ;
    SHAPE ABUTMENT ;
    PORT
      LAYER M3 ;
      RECT 0 119.315 0.07 119.385 ;
    END
  END rw0_wd_in[220]
  PIN rw0_wd_in[221]
    DIRECTION INPUT ;
    USE SIGNAL ;
    SHAPE ABUTMENT ;
    PORT
      LAYER M3 ;
      RECT 0 119.735 0.07 119.805 ;
    END
  END rw0_wd_in[221]
  PIN rw0_wd_in[222]
    DIRECTION INPUT ;
    USE SIGNAL ;
    SHAPE ABUTMENT ;
    PORT
      LAYER M3 ;
      RECT 0 120.155 0.07 120.225 ;
    END
  END rw0_wd_in[222]
  PIN rw0_wd_in[223]
    DIRECTION INPUT ;
    USE SIGNAL ;
    SHAPE ABUTMENT ;
    PORT
      LAYER M3 ;
      RECT 0 120.575 0.07 120.645 ;
    END
  END rw0_wd_in[223]
  PIN rw0_wd_in[224]
    DIRECTION INPUT ;
    USE SIGNAL ;
    SHAPE ABUTMENT ;
    PORT
      LAYER M3 ;
      RECT 0 120.995 0.07 121.065 ;
    END
  END rw0_wd_in[224]
  PIN rw0_wd_in[225]
    DIRECTION INPUT ;
    USE SIGNAL ;
    SHAPE ABUTMENT ;
    PORT
      LAYER M3 ;
      RECT 0 121.415 0.07 121.485 ;
    END
  END rw0_wd_in[225]
  PIN rw0_wd_in[226]
    DIRECTION INPUT ;
    USE SIGNAL ;
    SHAPE ABUTMENT ;
    PORT
      LAYER M3 ;
      RECT 0 121.835 0.07 121.905 ;
    END
  END rw0_wd_in[226]
  PIN rw0_wd_in[227]
    DIRECTION INPUT ;
    USE SIGNAL ;
    SHAPE ABUTMENT ;
    PORT
      LAYER M3 ;
      RECT 0 122.255 0.07 122.325 ;
    END
  END rw0_wd_in[227]
  PIN rw0_wd_in[228]
    DIRECTION INPUT ;
    USE SIGNAL ;
    SHAPE ABUTMENT ;
    PORT
      LAYER M3 ;
      RECT 0 122.675 0.07 122.745 ;
    END
  END rw0_wd_in[228]
  PIN rw0_wd_in[229]
    DIRECTION INPUT ;
    USE SIGNAL ;
    SHAPE ABUTMENT ;
    PORT
      LAYER M3 ;
      RECT 0 123.095 0.07 123.165 ;
    END
  END rw0_wd_in[229]
  PIN rw0_wd_in[230]
    DIRECTION INPUT ;
    USE SIGNAL ;
    SHAPE ABUTMENT ;
    PORT
      LAYER M3 ;
      RECT 0 123.515 0.07 123.585 ;
    END
  END rw0_wd_in[230]
  PIN rw0_wd_in[231]
    DIRECTION INPUT ;
    USE SIGNAL ;
    SHAPE ABUTMENT ;
    PORT
      LAYER M3 ;
      RECT 0 123.935 0.07 124.005 ;
    END
  END rw0_wd_in[231]
  PIN rw0_wd_in[232]
    DIRECTION INPUT ;
    USE SIGNAL ;
    SHAPE ABUTMENT ;
    PORT
      LAYER M3 ;
      RECT 0 124.355 0.07 124.425 ;
    END
  END rw0_wd_in[232]
  PIN rw0_wd_in[233]
    DIRECTION INPUT ;
    USE SIGNAL ;
    SHAPE ABUTMENT ;
    PORT
      LAYER M3 ;
      RECT 0 124.775 0.07 124.845 ;
    END
  END rw0_wd_in[233]
  PIN rw0_wd_in[234]
    DIRECTION INPUT ;
    USE SIGNAL ;
    SHAPE ABUTMENT ;
    PORT
      LAYER M3 ;
      RECT 0 125.195 0.07 125.265 ;
    END
  END rw0_wd_in[234]
  PIN rw0_wd_in[235]
    DIRECTION INPUT ;
    USE SIGNAL ;
    SHAPE ABUTMENT ;
    PORT
      LAYER M3 ;
      RECT 0 125.615 0.07 125.685 ;
    END
  END rw0_wd_in[235]
  PIN rw0_wd_in[236]
    DIRECTION INPUT ;
    USE SIGNAL ;
    SHAPE ABUTMENT ;
    PORT
      LAYER M3 ;
      RECT 0 126.035 0.07 126.105 ;
    END
  END rw0_wd_in[236]
  PIN rw0_wd_in[237]
    DIRECTION INPUT ;
    USE SIGNAL ;
    SHAPE ABUTMENT ;
    PORT
      LAYER M3 ;
      RECT 0 126.455 0.07 126.525 ;
    END
  END rw0_wd_in[237]
  PIN rw0_wd_in[238]
    DIRECTION INPUT ;
    USE SIGNAL ;
    SHAPE ABUTMENT ;
    PORT
      LAYER M3 ;
      RECT 0 126.875 0.07 126.945 ;
    END
  END rw0_wd_in[238]
  PIN rw0_wd_in[239]
    DIRECTION INPUT ;
    USE SIGNAL ;
    SHAPE ABUTMENT ;
    PORT
      LAYER M3 ;
      RECT 0 127.295 0.07 127.365 ;
    END
  END rw0_wd_in[239]
  PIN rw0_wd_in[240]
    DIRECTION INPUT ;
    USE SIGNAL ;
    SHAPE ABUTMENT ;
    PORT
      LAYER M3 ;
      RECT 0 127.715 0.07 127.785 ;
    END
  END rw0_wd_in[240]
  PIN rw0_wd_in[241]
    DIRECTION INPUT ;
    USE SIGNAL ;
    SHAPE ABUTMENT ;
    PORT
      LAYER M3 ;
      RECT 0 128.135 0.07 128.205 ;
    END
  END rw0_wd_in[241]
  PIN rw0_wd_in[242]
    DIRECTION INPUT ;
    USE SIGNAL ;
    SHAPE ABUTMENT ;
    PORT
      LAYER M3 ;
      RECT 0 128.555 0.07 128.625 ;
    END
  END rw0_wd_in[242]
  PIN rw0_wd_in[243]
    DIRECTION INPUT ;
    USE SIGNAL ;
    SHAPE ABUTMENT ;
    PORT
      LAYER M3 ;
      RECT 0 128.975 0.07 129.045 ;
    END
  END rw0_wd_in[243]
  PIN rw0_wd_in[244]
    DIRECTION INPUT ;
    USE SIGNAL ;
    SHAPE ABUTMENT ;
    PORT
      LAYER M3 ;
      RECT 0 129.395 0.07 129.465 ;
    END
  END rw0_wd_in[244]
  PIN rw0_wd_in[245]
    DIRECTION INPUT ;
    USE SIGNAL ;
    SHAPE ABUTMENT ;
    PORT
      LAYER M3 ;
      RECT 0 129.815 0.07 129.885 ;
    END
  END rw0_wd_in[245]
  PIN rw0_wd_in[246]
    DIRECTION INPUT ;
    USE SIGNAL ;
    SHAPE ABUTMENT ;
    PORT
      LAYER M3 ;
      RECT 0 130.235 0.07 130.305 ;
    END
  END rw0_wd_in[246]
  PIN rw0_wd_in[247]
    DIRECTION INPUT ;
    USE SIGNAL ;
    SHAPE ABUTMENT ;
    PORT
      LAYER M3 ;
      RECT 0 130.655 0.07 130.725 ;
    END
  END rw0_wd_in[247]
  PIN rw0_wd_in[248]
    DIRECTION INPUT ;
    USE SIGNAL ;
    SHAPE ABUTMENT ;
    PORT
      LAYER M3 ;
      RECT 0 131.075 0.07 131.145 ;
    END
  END rw0_wd_in[248]
  PIN rw0_wd_in[249]
    DIRECTION INPUT ;
    USE SIGNAL ;
    SHAPE ABUTMENT ;
    PORT
      LAYER M3 ;
      RECT 0 131.495 0.07 131.565 ;
    END
  END rw0_wd_in[249]
  PIN rw0_wd_in[250]
    DIRECTION INPUT ;
    USE SIGNAL ;
    SHAPE ABUTMENT ;
    PORT
      LAYER M3 ;
      RECT 0 131.915 0.07 131.985 ;
    END
  END rw0_wd_in[250]
  PIN rw0_wd_in[251]
    DIRECTION INPUT ;
    USE SIGNAL ;
    SHAPE ABUTMENT ;
    PORT
      LAYER M3 ;
      RECT 0 132.335 0.07 132.405 ;
    END
  END rw0_wd_in[251]
  PIN rw0_wd_in[252]
    DIRECTION INPUT ;
    USE SIGNAL ;
    SHAPE ABUTMENT ;
    PORT
      LAYER M3 ;
      RECT 0 132.755 0.07 132.825 ;
    END
  END rw0_wd_in[252]
  PIN rw0_wd_in[253]
    DIRECTION INPUT ;
    USE SIGNAL ;
    SHAPE ABUTMENT ;
    PORT
      LAYER M3 ;
      RECT 0 133.175 0.07 133.245 ;
    END
  END rw0_wd_in[253]
  PIN rw0_wd_in[254]
    DIRECTION INPUT ;
    USE SIGNAL ;
    SHAPE ABUTMENT ;
    PORT
      LAYER M3 ;
      RECT 0 133.595 0.07 133.665 ;
    END
  END rw0_wd_in[254]
  PIN rw0_wd_in[255]
    DIRECTION INPUT ;
    USE SIGNAL ;
    SHAPE ABUTMENT ;
    PORT
      LAYER M3 ;
      RECT 0 134.015 0.07 134.085 ;
    END
  END rw0_wd_in[255]
  PIN rw0_wd_in[256]
    DIRECTION INPUT ;
    USE SIGNAL ;
    SHAPE ABUTMENT ;
    PORT
      LAYER M3 ;
      RECT 0 134.435 0.07 134.505 ;
    END
  END rw0_wd_in[256]
  PIN rw0_wd_in[257]
    DIRECTION INPUT ;
    USE SIGNAL ;
    SHAPE ABUTMENT ;
    PORT
      LAYER M3 ;
      RECT 0 134.855 0.07 134.925 ;
    END
  END rw0_wd_in[257]
  PIN rw0_wd_in[258]
    DIRECTION INPUT ;
    USE SIGNAL ;
    SHAPE ABUTMENT ;
    PORT
      LAYER M3 ;
      RECT 0 135.275 0.07 135.345 ;
    END
  END rw0_wd_in[258]
  PIN rw0_wd_in[259]
    DIRECTION INPUT ;
    USE SIGNAL ;
    SHAPE ABUTMENT ;
    PORT
      LAYER M3 ;
      RECT 0 135.695 0.07 135.765 ;
    END
  END rw0_wd_in[259]
  PIN rw0_wd_in[260]
    DIRECTION INPUT ;
    USE SIGNAL ;
    SHAPE ABUTMENT ;
    PORT
      LAYER M3 ;
      RECT 0 136.115 0.07 136.185 ;
    END
  END rw0_wd_in[260]
  PIN rw0_wd_in[261]
    DIRECTION INPUT ;
    USE SIGNAL ;
    SHAPE ABUTMENT ;
    PORT
      LAYER M3 ;
      RECT 0 136.535 0.07 136.605 ;
    END
  END rw0_wd_in[261]
  PIN rw0_wd_in[262]
    DIRECTION INPUT ;
    USE SIGNAL ;
    SHAPE ABUTMENT ;
    PORT
      LAYER M3 ;
      RECT 0 136.955 0.07 137.025 ;
    END
  END rw0_wd_in[262]
  PIN rw0_wd_in[263]
    DIRECTION INPUT ;
    USE SIGNAL ;
    SHAPE ABUTMENT ;
    PORT
      LAYER M3 ;
      RECT 0 137.375 0.07 137.445 ;
    END
  END rw0_wd_in[263]
  PIN rw0_wd_in[264]
    DIRECTION INPUT ;
    USE SIGNAL ;
    SHAPE ABUTMENT ;
    PORT
      LAYER M3 ;
      RECT 0 137.795 0.07 137.865 ;
    END
  END rw0_wd_in[264]
  PIN rw0_wd_in[265]
    DIRECTION INPUT ;
    USE SIGNAL ;
    SHAPE ABUTMENT ;
    PORT
      LAYER M3 ;
      RECT 0 138.215 0.07 138.285 ;
    END
  END rw0_wd_in[265]
  PIN rw0_wd_in[266]
    DIRECTION INPUT ;
    USE SIGNAL ;
    SHAPE ABUTMENT ;
    PORT
      LAYER M3 ;
      RECT 0 138.635 0.07 138.705 ;
    END
  END rw0_wd_in[266]
  PIN rw0_wd_in[267]
    DIRECTION INPUT ;
    USE SIGNAL ;
    SHAPE ABUTMENT ;
    PORT
      LAYER M3 ;
      RECT 0 139.055 0.07 139.125 ;
    END
  END rw0_wd_in[267]
  PIN rw0_wd_in[268]
    DIRECTION INPUT ;
    USE SIGNAL ;
    SHAPE ABUTMENT ;
    PORT
      LAYER M3 ;
      RECT 0 139.475 0.07 139.545 ;
    END
  END rw0_wd_in[268]
  PIN rw0_wd_in[269]
    DIRECTION INPUT ;
    USE SIGNAL ;
    SHAPE ABUTMENT ;
    PORT
      LAYER M3 ;
      RECT 0 139.895 0.07 139.965 ;
    END
  END rw0_wd_in[269]
  PIN rw0_wd_in[270]
    DIRECTION INPUT ;
    USE SIGNAL ;
    SHAPE ABUTMENT ;
    PORT
      LAYER M3 ;
      RECT 0 140.315 0.07 140.385 ;
    END
  END rw0_wd_in[270]
  PIN rw0_wd_in[271]
    DIRECTION INPUT ;
    USE SIGNAL ;
    SHAPE ABUTMENT ;
    PORT
      LAYER M3 ;
      RECT 0 140.735 0.07 140.805 ;
    END
  END rw0_wd_in[271]
  PIN rw0_wd_in[272]
    DIRECTION INPUT ;
    USE SIGNAL ;
    SHAPE ABUTMENT ;
    PORT
      LAYER M3 ;
      RECT 0 141.155 0.07 141.225 ;
    END
  END rw0_wd_in[272]
  PIN rw0_wd_in[273]
    DIRECTION INPUT ;
    USE SIGNAL ;
    SHAPE ABUTMENT ;
    PORT
      LAYER M3 ;
      RECT 0 141.575 0.07 141.645 ;
    END
  END rw0_wd_in[273]
  PIN rw0_wd_in[274]
    DIRECTION INPUT ;
    USE SIGNAL ;
    SHAPE ABUTMENT ;
    PORT
      LAYER M3 ;
      RECT 0 141.995 0.07 142.065 ;
    END
  END rw0_wd_in[274]
  PIN rw0_wd_in[275]
    DIRECTION INPUT ;
    USE SIGNAL ;
    SHAPE ABUTMENT ;
    PORT
      LAYER M3 ;
      RECT 0 142.415 0.07 142.485 ;
    END
  END rw0_wd_in[275]
  PIN rw0_wd_in[276]
    DIRECTION INPUT ;
    USE SIGNAL ;
    SHAPE ABUTMENT ;
    PORT
      LAYER M3 ;
      RECT 0 142.835 0.07 142.905 ;
    END
  END rw0_wd_in[276]
  PIN rw0_wd_in[277]
    DIRECTION INPUT ;
    USE SIGNAL ;
    SHAPE ABUTMENT ;
    PORT
      LAYER M3 ;
      RECT 0 143.255 0.07 143.325 ;
    END
  END rw0_wd_in[277]
  PIN rw0_wd_in[278]
    DIRECTION INPUT ;
    USE SIGNAL ;
    SHAPE ABUTMENT ;
    PORT
      LAYER M3 ;
      RECT 0 143.675 0.07 143.745 ;
    END
  END rw0_wd_in[278]
  PIN rw0_wd_in[279]
    DIRECTION INPUT ;
    USE SIGNAL ;
    SHAPE ABUTMENT ;
    PORT
      LAYER M3 ;
      RECT 0 144.095 0.07 144.165 ;
    END
  END rw0_wd_in[279]
  PIN rw0_wd_in[280]
    DIRECTION INPUT ;
    USE SIGNAL ;
    SHAPE ABUTMENT ;
    PORT
      LAYER M3 ;
      RECT 0 144.515 0.07 144.585 ;
    END
  END rw0_wd_in[280]
  PIN rw0_wd_in[281]
    DIRECTION INPUT ;
    USE SIGNAL ;
    SHAPE ABUTMENT ;
    PORT
      LAYER M3 ;
      RECT 0 144.935 0.07 145.005 ;
    END
  END rw0_wd_in[281]
  PIN rw0_wd_in[282]
    DIRECTION INPUT ;
    USE SIGNAL ;
    SHAPE ABUTMENT ;
    PORT
      LAYER M3 ;
      RECT 0 145.355 0.07 145.425 ;
    END
  END rw0_wd_in[282]
  PIN rw0_wd_in[283]
    DIRECTION INPUT ;
    USE SIGNAL ;
    SHAPE ABUTMENT ;
    PORT
      LAYER M3 ;
      RECT 0 145.775 0.07 145.845 ;
    END
  END rw0_wd_in[283]
  PIN rw0_wd_in[284]
    DIRECTION INPUT ;
    USE SIGNAL ;
    SHAPE ABUTMENT ;
    PORT
      LAYER M3 ;
      RECT 0 146.195 0.07 146.265 ;
    END
  END rw0_wd_in[284]
  PIN rw0_wd_in[285]
    DIRECTION INPUT ;
    USE SIGNAL ;
    SHAPE ABUTMENT ;
    PORT
      LAYER M3 ;
      RECT 0 146.615 0.07 146.685 ;
    END
  END rw0_wd_in[285]
  PIN rw0_wd_in[286]
    DIRECTION INPUT ;
    USE SIGNAL ;
    SHAPE ABUTMENT ;
    PORT
      LAYER M3 ;
      RECT 0 147.035 0.07 147.105 ;
    END
  END rw0_wd_in[286]
  PIN rw0_wd_in[287]
    DIRECTION INPUT ;
    USE SIGNAL ;
    SHAPE ABUTMENT ;
    PORT
      LAYER M3 ;
      RECT 0 147.455 0.07 147.525 ;
    END
  END rw0_wd_in[287]
  PIN rw0_wd_in[288]
    DIRECTION INPUT ;
    USE SIGNAL ;
    SHAPE ABUTMENT ;
    PORT
      LAYER M3 ;
      RECT 0 147.875 0.07 147.945 ;
    END
  END rw0_wd_in[288]
  PIN rw0_wd_in[289]
    DIRECTION INPUT ;
    USE SIGNAL ;
    SHAPE ABUTMENT ;
    PORT
      LAYER M3 ;
      RECT 0 148.295 0.07 148.365 ;
    END
  END rw0_wd_in[289]
  PIN rw0_wd_in[290]
    DIRECTION INPUT ;
    USE SIGNAL ;
    SHAPE ABUTMENT ;
    PORT
      LAYER M3 ;
      RECT 0 148.715 0.07 148.785 ;
    END
  END rw0_wd_in[290]
  PIN rw0_wd_in[291]
    DIRECTION INPUT ;
    USE SIGNAL ;
    SHAPE ABUTMENT ;
    PORT
      LAYER M3 ;
      RECT 0 149.135 0.07 149.205 ;
    END
  END rw0_wd_in[291]
  PIN rw0_wd_in[292]
    DIRECTION INPUT ;
    USE SIGNAL ;
    SHAPE ABUTMENT ;
    PORT
      LAYER M3 ;
      RECT 0 149.555 0.07 149.625 ;
    END
  END rw0_wd_in[292]
  PIN rw0_wd_in[293]
    DIRECTION INPUT ;
    USE SIGNAL ;
    SHAPE ABUTMENT ;
    PORT
      LAYER M3 ;
      RECT 0 149.975 0.07 150.045 ;
    END
  END rw0_wd_in[293]
  PIN rw0_wd_in[294]
    DIRECTION INPUT ;
    USE SIGNAL ;
    SHAPE ABUTMENT ;
    PORT
      LAYER M3 ;
      RECT 0 150.395 0.07 150.465 ;
    END
  END rw0_wd_in[294]
  PIN rw0_wd_in[295]
    DIRECTION INPUT ;
    USE SIGNAL ;
    SHAPE ABUTMENT ;
    PORT
      LAYER M3 ;
      RECT 0 150.815 0.07 150.885 ;
    END
  END rw0_wd_in[295]
  PIN rw0_wd_in[296]
    DIRECTION INPUT ;
    USE SIGNAL ;
    SHAPE ABUTMENT ;
    PORT
      LAYER M3 ;
      RECT 0 151.235 0.07 151.305 ;
    END
  END rw0_wd_in[296]
  PIN rw0_wd_in[297]
    DIRECTION INPUT ;
    USE SIGNAL ;
    SHAPE ABUTMENT ;
    PORT
      LAYER M3 ;
      RECT 0 151.655 0.07 151.725 ;
    END
  END rw0_wd_in[297]
  PIN rw0_wd_in[298]
    DIRECTION INPUT ;
    USE SIGNAL ;
    SHAPE ABUTMENT ;
    PORT
      LAYER M3 ;
      RECT 0 152.075 0.07 152.145 ;
    END
  END rw0_wd_in[298]
  PIN rw0_wd_in[299]
    DIRECTION INPUT ;
    USE SIGNAL ;
    SHAPE ABUTMENT ;
    PORT
      LAYER M3 ;
      RECT 0 152.495 0.07 152.565 ;
    END
  END rw0_wd_in[299]
  PIN rw0_wd_in[300]
    DIRECTION INPUT ;
    USE SIGNAL ;
    SHAPE ABUTMENT ;
    PORT
      LAYER M3 ;
      RECT 0 152.915 0.07 152.985 ;
    END
  END rw0_wd_in[300]
  PIN rw0_wd_in[301]
    DIRECTION INPUT ;
    USE SIGNAL ;
    SHAPE ABUTMENT ;
    PORT
      LAYER M3 ;
      RECT 0 153.335 0.07 153.405 ;
    END
  END rw0_wd_in[301]
  PIN rw0_wd_in[302]
    DIRECTION INPUT ;
    USE SIGNAL ;
    SHAPE ABUTMENT ;
    PORT
      LAYER M3 ;
      RECT 0 153.755 0.07 153.825 ;
    END
  END rw0_wd_in[302]
  PIN rw0_wd_in[303]
    DIRECTION INPUT ;
    USE SIGNAL ;
    SHAPE ABUTMENT ;
    PORT
      LAYER M3 ;
      RECT 0 154.175 0.07 154.245 ;
    END
  END rw0_wd_in[303]
  PIN rw0_wd_in[304]
    DIRECTION INPUT ;
    USE SIGNAL ;
    SHAPE ABUTMENT ;
    PORT
      LAYER M3 ;
      RECT 0 154.595 0.07 154.665 ;
    END
  END rw0_wd_in[304]
  PIN rw0_wd_in[305]
    DIRECTION INPUT ;
    USE SIGNAL ;
    SHAPE ABUTMENT ;
    PORT
      LAYER M3 ;
      RECT 0 155.015 0.07 155.085 ;
    END
  END rw0_wd_in[305]
  PIN rw0_wd_in[306]
    DIRECTION INPUT ;
    USE SIGNAL ;
    SHAPE ABUTMENT ;
    PORT
      LAYER M3 ;
      RECT 0 155.435 0.07 155.505 ;
    END
  END rw0_wd_in[306]
  PIN rw0_wd_in[307]
    DIRECTION INPUT ;
    USE SIGNAL ;
    SHAPE ABUTMENT ;
    PORT
      LAYER M3 ;
      RECT 0 155.855 0.07 155.925 ;
    END
  END rw0_wd_in[307]
  PIN rw0_wd_in[308]
    DIRECTION INPUT ;
    USE SIGNAL ;
    SHAPE ABUTMENT ;
    PORT
      LAYER M3 ;
      RECT 0 156.275 0.07 156.345 ;
    END
  END rw0_wd_in[308]
  PIN rw0_wd_in[309]
    DIRECTION INPUT ;
    USE SIGNAL ;
    SHAPE ABUTMENT ;
    PORT
      LAYER M3 ;
      RECT 0 156.695 0.07 156.765 ;
    END
  END rw0_wd_in[309]
  PIN rw0_wd_in[310]
    DIRECTION INPUT ;
    USE SIGNAL ;
    SHAPE ABUTMENT ;
    PORT
      LAYER M3 ;
      RECT 0 157.115 0.07 157.185 ;
    END
  END rw0_wd_in[310]
  PIN rw0_wd_in[311]
    DIRECTION INPUT ;
    USE SIGNAL ;
    SHAPE ABUTMENT ;
    PORT
      LAYER M3 ;
      RECT 0 157.535 0.07 157.605 ;
    END
  END rw0_wd_in[311]
  PIN rw0_wd_in[312]
    DIRECTION INPUT ;
    USE SIGNAL ;
    SHAPE ABUTMENT ;
    PORT
      LAYER M3 ;
      RECT 0 157.955 0.07 158.025 ;
    END
  END rw0_wd_in[312]
  PIN rw0_wd_in[313]
    DIRECTION INPUT ;
    USE SIGNAL ;
    SHAPE ABUTMENT ;
    PORT
      LAYER M3 ;
      RECT 0 158.375 0.07 158.445 ;
    END
  END rw0_wd_in[313]
  PIN rw0_wd_in[314]
    DIRECTION INPUT ;
    USE SIGNAL ;
    SHAPE ABUTMENT ;
    PORT
      LAYER M3 ;
      RECT 0 158.795 0.07 158.865 ;
    END
  END rw0_wd_in[314]
  PIN rw0_wd_in[315]
    DIRECTION INPUT ;
    USE SIGNAL ;
    SHAPE ABUTMENT ;
    PORT
      LAYER M3 ;
      RECT 0 159.215 0.07 159.285 ;
    END
  END rw0_wd_in[315]
  PIN rw0_wd_in[316]
    DIRECTION INPUT ;
    USE SIGNAL ;
    SHAPE ABUTMENT ;
    PORT
      LAYER M3 ;
      RECT 0 159.635 0.07 159.705 ;
    END
  END rw0_wd_in[316]
  PIN rw0_wd_in[317]
    DIRECTION INPUT ;
    USE SIGNAL ;
    SHAPE ABUTMENT ;
    PORT
      LAYER M3 ;
      RECT 0 160.055 0.07 160.125 ;
    END
  END rw0_wd_in[317]
  PIN rw0_wd_in[318]
    DIRECTION INPUT ;
    USE SIGNAL ;
    SHAPE ABUTMENT ;
    PORT
      LAYER M3 ;
      RECT 0 160.475 0.07 160.545 ;
    END
  END rw0_wd_in[318]
  PIN rw0_wd_in[319]
    DIRECTION INPUT ;
    USE SIGNAL ;
    SHAPE ABUTMENT ;
    PORT
      LAYER M3 ;
      RECT 0 160.895 0.07 160.965 ;
    END
  END rw0_wd_in[319]
  PIN rw0_wd_in[320]
    DIRECTION INPUT ;
    USE SIGNAL ;
    SHAPE ABUTMENT ;
    PORT
      LAYER M3 ;
      RECT 0 161.315 0.07 161.385 ;
    END
  END rw0_wd_in[320]
  PIN rw0_wd_in[321]
    DIRECTION INPUT ;
    USE SIGNAL ;
    SHAPE ABUTMENT ;
    PORT
      LAYER M3 ;
      RECT 0 161.735 0.07 161.805 ;
    END
  END rw0_wd_in[321]
  PIN rw0_wd_in[322]
    DIRECTION INPUT ;
    USE SIGNAL ;
    SHAPE ABUTMENT ;
    PORT
      LAYER M3 ;
      RECT 0 162.155 0.07 162.225 ;
    END
  END rw0_wd_in[322]
  PIN rw0_wd_in[323]
    DIRECTION INPUT ;
    USE SIGNAL ;
    SHAPE ABUTMENT ;
    PORT
      LAYER M3 ;
      RECT 0 162.575 0.07 162.645 ;
    END
  END rw0_wd_in[323]
  PIN rw0_wd_in[324]
    DIRECTION INPUT ;
    USE SIGNAL ;
    SHAPE ABUTMENT ;
    PORT
      LAYER M3 ;
      RECT 0 162.995 0.07 163.065 ;
    END
  END rw0_wd_in[324]
  PIN rw0_wd_in[325]
    DIRECTION INPUT ;
    USE SIGNAL ;
    SHAPE ABUTMENT ;
    PORT
      LAYER M3 ;
      RECT 0 163.415 0.07 163.485 ;
    END
  END rw0_wd_in[325]
  PIN rw0_wd_in[326]
    DIRECTION INPUT ;
    USE SIGNAL ;
    SHAPE ABUTMENT ;
    PORT
      LAYER M3 ;
      RECT 0 163.835 0.07 163.905 ;
    END
  END rw0_wd_in[326]
  PIN rw0_wd_in[327]
    DIRECTION INPUT ;
    USE SIGNAL ;
    SHAPE ABUTMENT ;
    PORT
      LAYER M3 ;
      RECT 0 164.255 0.07 164.325 ;
    END
  END rw0_wd_in[327]
  PIN rw0_wd_in[328]
    DIRECTION INPUT ;
    USE SIGNAL ;
    SHAPE ABUTMENT ;
    PORT
      LAYER M3 ;
      RECT 0 164.675 0.07 164.745 ;
    END
  END rw0_wd_in[328]
  PIN rw0_wd_in[329]
    DIRECTION INPUT ;
    USE SIGNAL ;
    SHAPE ABUTMENT ;
    PORT
      LAYER M3 ;
      RECT 0 165.095 0.07 165.165 ;
    END
  END rw0_wd_in[329]
  PIN rw0_wd_in[330]
    DIRECTION INPUT ;
    USE SIGNAL ;
    SHAPE ABUTMENT ;
    PORT
      LAYER M3 ;
      RECT 0 165.515 0.07 165.585 ;
    END
  END rw0_wd_in[330]
  PIN rw0_wd_in[331]
    DIRECTION INPUT ;
    USE SIGNAL ;
    SHAPE ABUTMENT ;
    PORT
      LAYER M3 ;
      RECT 0 165.935 0.07 166.005 ;
    END
  END rw0_wd_in[331]
  PIN rw0_wd_in[332]
    DIRECTION INPUT ;
    USE SIGNAL ;
    SHAPE ABUTMENT ;
    PORT
      LAYER M3 ;
      RECT 0 166.355 0.07 166.425 ;
    END
  END rw0_wd_in[332]
  PIN rw0_wd_in[333]
    DIRECTION INPUT ;
    USE SIGNAL ;
    SHAPE ABUTMENT ;
    PORT
      LAYER M3 ;
      RECT 0 166.775 0.07 166.845 ;
    END
  END rw0_wd_in[333]
  PIN rw0_wd_in[334]
    DIRECTION INPUT ;
    USE SIGNAL ;
    SHAPE ABUTMENT ;
    PORT
      LAYER M3 ;
      RECT 0 167.195 0.07 167.265 ;
    END
  END rw0_wd_in[334]
  PIN rw0_wd_in[335]
    DIRECTION INPUT ;
    USE SIGNAL ;
    SHAPE ABUTMENT ;
    PORT
      LAYER M3 ;
      RECT 0 167.615 0.07 167.685 ;
    END
  END rw0_wd_in[335]
  PIN rw0_wd_in[336]
    DIRECTION INPUT ;
    USE SIGNAL ;
    SHAPE ABUTMENT ;
    PORT
      LAYER M3 ;
      RECT 0 168.035 0.07 168.105 ;
    END
  END rw0_wd_in[336]
  PIN rw0_wd_in[337]
    DIRECTION INPUT ;
    USE SIGNAL ;
    SHAPE ABUTMENT ;
    PORT
      LAYER M3 ;
      RECT 0 168.455 0.07 168.525 ;
    END
  END rw0_wd_in[337]
  PIN rw0_wd_in[338]
    DIRECTION INPUT ;
    USE SIGNAL ;
    SHAPE ABUTMENT ;
    PORT
      LAYER M3 ;
      RECT 0 168.875 0.07 168.945 ;
    END
  END rw0_wd_in[338]
  PIN rw0_wd_in[339]
    DIRECTION INPUT ;
    USE SIGNAL ;
    SHAPE ABUTMENT ;
    PORT
      LAYER M3 ;
      RECT 0 169.295 0.07 169.365 ;
    END
  END rw0_wd_in[339]
  PIN rw0_wd_in[340]
    DIRECTION INPUT ;
    USE SIGNAL ;
    SHAPE ABUTMENT ;
    PORT
      LAYER M3 ;
      RECT 0 169.715 0.07 169.785 ;
    END
  END rw0_wd_in[340]
  PIN rw0_wd_in[341]
    DIRECTION INPUT ;
    USE SIGNAL ;
    SHAPE ABUTMENT ;
    PORT
      LAYER M3 ;
      RECT 0 170.135 0.07 170.205 ;
    END
  END rw0_wd_in[341]
  PIN rw0_wd_in[342]
    DIRECTION INPUT ;
    USE SIGNAL ;
    SHAPE ABUTMENT ;
    PORT
      LAYER M3 ;
      RECT 0 170.555 0.07 170.625 ;
    END
  END rw0_wd_in[342]
  PIN rw0_wd_in[343]
    DIRECTION INPUT ;
    USE SIGNAL ;
    SHAPE ABUTMENT ;
    PORT
      LAYER M3 ;
      RECT 0 170.975 0.07 171.045 ;
    END
  END rw0_wd_in[343]
  PIN rw0_wd_in[344]
    DIRECTION INPUT ;
    USE SIGNAL ;
    SHAPE ABUTMENT ;
    PORT
      LAYER M3 ;
      RECT 0 171.395 0.07 171.465 ;
    END
  END rw0_wd_in[344]
  PIN rw0_wd_in[345]
    DIRECTION INPUT ;
    USE SIGNAL ;
    SHAPE ABUTMENT ;
    PORT
      LAYER M3 ;
      RECT 0 171.815 0.07 171.885 ;
    END
  END rw0_wd_in[345]
  PIN rw0_wd_in[346]
    DIRECTION INPUT ;
    USE SIGNAL ;
    SHAPE ABUTMENT ;
    PORT
      LAYER M3 ;
      RECT 0 172.235 0.07 172.305 ;
    END
  END rw0_wd_in[346]
  PIN rw0_wd_in[347]
    DIRECTION INPUT ;
    USE SIGNAL ;
    SHAPE ABUTMENT ;
    PORT
      LAYER M3 ;
      RECT 0 172.655 0.07 172.725 ;
    END
  END rw0_wd_in[347]
  PIN rw0_wd_in[348]
    DIRECTION INPUT ;
    USE SIGNAL ;
    SHAPE ABUTMENT ;
    PORT
      LAYER M3 ;
      RECT 0 173.075 0.07 173.145 ;
    END
  END rw0_wd_in[348]
  PIN rw0_wd_in[349]
    DIRECTION INPUT ;
    USE SIGNAL ;
    SHAPE ABUTMENT ;
    PORT
      LAYER M3 ;
      RECT 0 173.495 0.07 173.565 ;
    END
  END rw0_wd_in[349]
  PIN rw0_wd_in[350]
    DIRECTION INPUT ;
    USE SIGNAL ;
    SHAPE ABUTMENT ;
    PORT
      LAYER M3 ;
      RECT 0 173.915 0.07 173.985 ;
    END
  END rw0_wd_in[350]
  PIN rw0_wd_in[351]
    DIRECTION INPUT ;
    USE SIGNAL ;
    SHAPE ABUTMENT ;
    PORT
      LAYER M3 ;
      RECT 0 174.335 0.07 174.405 ;
    END
  END rw0_wd_in[351]
  PIN rw0_wd_in[352]
    DIRECTION INPUT ;
    USE SIGNAL ;
    SHAPE ABUTMENT ;
    PORT
      LAYER M3 ;
      RECT 0 174.755 0.07 174.825 ;
    END
  END rw0_wd_in[352]
  PIN rw0_wd_in[353]
    DIRECTION INPUT ;
    USE SIGNAL ;
    SHAPE ABUTMENT ;
    PORT
      LAYER M3 ;
      RECT 0 175.175 0.07 175.245 ;
    END
  END rw0_wd_in[353]
  PIN rw0_wd_in[354]
    DIRECTION INPUT ;
    USE SIGNAL ;
    SHAPE ABUTMENT ;
    PORT
      LAYER M3 ;
      RECT 0 175.595 0.07 175.665 ;
    END
  END rw0_wd_in[354]
  PIN rw0_wd_in[355]
    DIRECTION INPUT ;
    USE SIGNAL ;
    SHAPE ABUTMENT ;
    PORT
      LAYER M3 ;
      RECT 0 176.015 0.07 176.085 ;
    END
  END rw0_wd_in[355]
  PIN rw0_wd_in[356]
    DIRECTION INPUT ;
    USE SIGNAL ;
    SHAPE ABUTMENT ;
    PORT
      LAYER M3 ;
      RECT 0 176.435 0.07 176.505 ;
    END
  END rw0_wd_in[356]
  PIN rw0_wd_in[357]
    DIRECTION INPUT ;
    USE SIGNAL ;
    SHAPE ABUTMENT ;
    PORT
      LAYER M3 ;
      RECT 0 176.855 0.07 176.925 ;
    END
  END rw0_wd_in[357]
  PIN rw0_wd_in[358]
    DIRECTION INPUT ;
    USE SIGNAL ;
    SHAPE ABUTMENT ;
    PORT
      LAYER M3 ;
      RECT 0 177.275 0.07 177.345 ;
    END
  END rw0_wd_in[358]
  PIN rw0_wd_in[359]
    DIRECTION INPUT ;
    USE SIGNAL ;
    SHAPE ABUTMENT ;
    PORT
      LAYER M3 ;
      RECT 0 177.695 0.07 177.765 ;
    END
  END rw0_wd_in[359]
  PIN rw0_wd_in[360]
    DIRECTION INPUT ;
    USE SIGNAL ;
    SHAPE ABUTMENT ;
    PORT
      LAYER M3 ;
      RECT 0 178.115 0.07 178.185 ;
    END
  END rw0_wd_in[360]
  PIN rw0_wd_in[361]
    DIRECTION INPUT ;
    USE SIGNAL ;
    SHAPE ABUTMENT ;
    PORT
      LAYER M3 ;
      RECT 0 178.535 0.07 178.605 ;
    END
  END rw0_wd_in[361]
  PIN rw0_wd_in[362]
    DIRECTION INPUT ;
    USE SIGNAL ;
    SHAPE ABUTMENT ;
    PORT
      LAYER M3 ;
      RECT 0 178.955 0.07 179.025 ;
    END
  END rw0_wd_in[362]
  PIN rw0_wd_in[363]
    DIRECTION INPUT ;
    USE SIGNAL ;
    SHAPE ABUTMENT ;
    PORT
      LAYER M3 ;
      RECT 0 179.375 0.07 179.445 ;
    END
  END rw0_wd_in[363]
  PIN rw0_wd_in[364]
    DIRECTION INPUT ;
    USE SIGNAL ;
    SHAPE ABUTMENT ;
    PORT
      LAYER M3 ;
      RECT 0 179.795 0.07 179.865 ;
    END
  END rw0_wd_in[364]
  PIN rw0_wd_in[365]
    DIRECTION INPUT ;
    USE SIGNAL ;
    SHAPE ABUTMENT ;
    PORT
      LAYER M3 ;
      RECT 0 180.215 0.07 180.285 ;
    END
  END rw0_wd_in[365]
  PIN rw0_wd_in[366]
    DIRECTION INPUT ;
    USE SIGNAL ;
    SHAPE ABUTMENT ;
    PORT
      LAYER M3 ;
      RECT 0 180.635 0.07 180.705 ;
    END
  END rw0_wd_in[366]
  PIN rw0_wd_in[367]
    DIRECTION INPUT ;
    USE SIGNAL ;
    SHAPE ABUTMENT ;
    PORT
      LAYER M3 ;
      RECT 0 181.055 0.07 181.125 ;
    END
  END rw0_wd_in[367]
  PIN rw0_wd_in[368]
    DIRECTION INPUT ;
    USE SIGNAL ;
    SHAPE ABUTMENT ;
    PORT
      LAYER M3 ;
      RECT 0 181.475 0.07 181.545 ;
    END
  END rw0_wd_in[368]
  PIN rw0_wd_in[369]
    DIRECTION INPUT ;
    USE SIGNAL ;
    SHAPE ABUTMENT ;
    PORT
      LAYER M3 ;
      RECT 0 181.895 0.07 181.965 ;
    END
  END rw0_wd_in[369]
  PIN rw0_wd_in[370]
    DIRECTION INPUT ;
    USE SIGNAL ;
    SHAPE ABUTMENT ;
    PORT
      LAYER M3 ;
      RECT 0 182.315 0.07 182.385 ;
    END
  END rw0_wd_in[370]
  PIN rw0_wd_in[371]
    DIRECTION INPUT ;
    USE SIGNAL ;
    SHAPE ABUTMENT ;
    PORT
      LAYER M3 ;
      RECT 0 182.735 0.07 182.805 ;
    END
  END rw0_wd_in[371]
  PIN rw0_wd_in[372]
    DIRECTION INPUT ;
    USE SIGNAL ;
    SHAPE ABUTMENT ;
    PORT
      LAYER M3 ;
      RECT 0 183.155 0.07 183.225 ;
    END
  END rw0_wd_in[372]
  PIN rw0_wd_in[373]
    DIRECTION INPUT ;
    USE SIGNAL ;
    SHAPE ABUTMENT ;
    PORT
      LAYER M3 ;
      RECT 0 183.575 0.07 183.645 ;
    END
  END rw0_wd_in[373]
  PIN rw0_wd_in[374]
    DIRECTION INPUT ;
    USE SIGNAL ;
    SHAPE ABUTMENT ;
    PORT
      LAYER M3 ;
      RECT 0 183.995 0.07 184.065 ;
    END
  END rw0_wd_in[374]
  PIN rw0_wd_in[375]
    DIRECTION INPUT ;
    USE SIGNAL ;
    SHAPE ABUTMENT ;
    PORT
      LAYER M3 ;
      RECT 0 184.415 0.07 184.485 ;
    END
  END rw0_wd_in[375]
  PIN rw0_wd_in[376]
    DIRECTION INPUT ;
    USE SIGNAL ;
    SHAPE ABUTMENT ;
    PORT
      LAYER M3 ;
      RECT 0 184.835 0.07 184.905 ;
    END
  END rw0_wd_in[376]
  PIN rw0_wd_in[377]
    DIRECTION INPUT ;
    USE SIGNAL ;
    SHAPE ABUTMENT ;
    PORT
      LAYER M3 ;
      RECT 0 185.255 0.07 185.325 ;
    END
  END rw0_wd_in[377]
  PIN rw0_wd_in[378]
    DIRECTION INPUT ;
    USE SIGNAL ;
    SHAPE ABUTMENT ;
    PORT
      LAYER M3 ;
      RECT 0 185.675 0.07 185.745 ;
    END
  END rw0_wd_in[378]
  PIN rw0_wd_in[379]
    DIRECTION INPUT ;
    USE SIGNAL ;
    SHAPE ABUTMENT ;
    PORT
      LAYER M3 ;
      RECT 0 186.095 0.07 186.165 ;
    END
  END rw0_wd_in[379]
  PIN rw0_wd_in[380]
    DIRECTION INPUT ;
    USE SIGNAL ;
    SHAPE ABUTMENT ;
    PORT
      LAYER M3 ;
      RECT 0 186.515 0.07 186.585 ;
    END
  END rw0_wd_in[380]
  PIN rw0_wd_in[381]
    DIRECTION INPUT ;
    USE SIGNAL ;
    SHAPE ABUTMENT ;
    PORT
      LAYER M3 ;
      RECT 0 186.935 0.07 187.005 ;
    END
  END rw0_wd_in[381]
  PIN rw0_wd_in[382]
    DIRECTION INPUT ;
    USE SIGNAL ;
    SHAPE ABUTMENT ;
    PORT
      LAYER M3 ;
      RECT 0 187.355 0.07 187.425 ;
    END
  END rw0_wd_in[382]
  PIN rw0_wd_in[383]
    DIRECTION INPUT ;
    USE SIGNAL ;
    SHAPE ABUTMENT ;
    PORT
      LAYER M3 ;
      RECT 0 187.775 0.07 187.845 ;
    END
  END rw0_wd_in[383]
  PIN rw0_wd_in[384]
    DIRECTION INPUT ;
    USE SIGNAL ;
    SHAPE ABUTMENT ;
    PORT
      LAYER M3 ;
      RECT 0 188.195 0.07 188.265 ;
    END
  END rw0_wd_in[384]
  PIN rw0_wd_in[385]
    DIRECTION INPUT ;
    USE SIGNAL ;
    SHAPE ABUTMENT ;
    PORT
      LAYER M3 ;
      RECT 0 188.615 0.07 188.685 ;
    END
  END rw0_wd_in[385]
  PIN rw0_wd_in[386]
    DIRECTION INPUT ;
    USE SIGNAL ;
    SHAPE ABUTMENT ;
    PORT
      LAYER M3 ;
      RECT 0 189.035 0.07 189.105 ;
    END
  END rw0_wd_in[386]
  PIN rw0_wd_in[387]
    DIRECTION INPUT ;
    USE SIGNAL ;
    SHAPE ABUTMENT ;
    PORT
      LAYER M3 ;
      RECT 0 189.455 0.07 189.525 ;
    END
  END rw0_wd_in[387]
  PIN rw0_wd_in[388]
    DIRECTION INPUT ;
    USE SIGNAL ;
    SHAPE ABUTMENT ;
    PORT
      LAYER M3 ;
      RECT 0 189.875 0.07 189.945 ;
    END
  END rw0_wd_in[388]
  PIN rw0_wd_in[389]
    DIRECTION INPUT ;
    USE SIGNAL ;
    SHAPE ABUTMENT ;
    PORT
      LAYER M3 ;
      RECT 0 190.295 0.07 190.365 ;
    END
  END rw0_wd_in[389]
  PIN rw0_wd_in[390]
    DIRECTION INPUT ;
    USE SIGNAL ;
    SHAPE ABUTMENT ;
    PORT
      LAYER M3 ;
      RECT 0 190.715 0.07 190.785 ;
    END
  END rw0_wd_in[390]
  PIN rw0_wd_in[391]
    DIRECTION INPUT ;
    USE SIGNAL ;
    SHAPE ABUTMENT ;
    PORT
      LAYER M3 ;
      RECT 0 191.135 0.07 191.205 ;
    END
  END rw0_wd_in[391]
  PIN rw0_wd_in[392]
    DIRECTION INPUT ;
    USE SIGNAL ;
    SHAPE ABUTMENT ;
    PORT
      LAYER M3 ;
      RECT 0 191.555 0.07 191.625 ;
    END
  END rw0_wd_in[392]
  PIN rw0_wd_in[393]
    DIRECTION INPUT ;
    USE SIGNAL ;
    SHAPE ABUTMENT ;
    PORT
      LAYER M3 ;
      RECT 0 191.975 0.07 192.045 ;
    END
  END rw0_wd_in[393]
  PIN rw0_wd_in[394]
    DIRECTION INPUT ;
    USE SIGNAL ;
    SHAPE ABUTMENT ;
    PORT
      LAYER M3 ;
      RECT 0 192.395 0.07 192.465 ;
    END
  END rw0_wd_in[394]
  PIN rw0_wd_in[395]
    DIRECTION INPUT ;
    USE SIGNAL ;
    SHAPE ABUTMENT ;
    PORT
      LAYER M3 ;
      RECT 0 192.815 0.07 192.885 ;
    END
  END rw0_wd_in[395]
  PIN rw0_wd_in[396]
    DIRECTION INPUT ;
    USE SIGNAL ;
    SHAPE ABUTMENT ;
    PORT
      LAYER M3 ;
      RECT 0 193.235 0.07 193.305 ;
    END
  END rw0_wd_in[396]
  PIN rw0_wd_in[397]
    DIRECTION INPUT ;
    USE SIGNAL ;
    SHAPE ABUTMENT ;
    PORT
      LAYER M3 ;
      RECT 0 193.655 0.07 193.725 ;
    END
  END rw0_wd_in[397]
  PIN rw0_wd_in[398]
    DIRECTION INPUT ;
    USE SIGNAL ;
    SHAPE ABUTMENT ;
    PORT
      LAYER M3 ;
      RECT 0 194.075 0.07 194.145 ;
    END
  END rw0_wd_in[398]
  PIN rw0_wd_in[399]
    DIRECTION INPUT ;
    USE SIGNAL ;
    SHAPE ABUTMENT ;
    PORT
      LAYER M3 ;
      RECT 0 194.495 0.07 194.565 ;
    END
  END rw0_wd_in[399]
  PIN rw0_wd_in[400]
    DIRECTION INPUT ;
    USE SIGNAL ;
    SHAPE ABUTMENT ;
    PORT
      LAYER M3 ;
      RECT 0 194.915 0.07 194.985 ;
    END
  END rw0_wd_in[400]
  PIN rw0_wd_in[401]
    DIRECTION INPUT ;
    USE SIGNAL ;
    SHAPE ABUTMENT ;
    PORT
      LAYER M3 ;
      RECT 0 195.335 0.07 195.405 ;
    END
  END rw0_wd_in[401]
  PIN rw0_wd_in[402]
    DIRECTION INPUT ;
    USE SIGNAL ;
    SHAPE ABUTMENT ;
    PORT
      LAYER M3 ;
      RECT 0 195.755 0.07 195.825 ;
    END
  END rw0_wd_in[402]
  PIN rw0_wd_in[403]
    DIRECTION INPUT ;
    USE SIGNAL ;
    SHAPE ABUTMENT ;
    PORT
      LAYER M3 ;
      RECT 0 196.175 0.07 196.245 ;
    END
  END rw0_wd_in[403]
  PIN rw0_wd_in[404]
    DIRECTION INPUT ;
    USE SIGNAL ;
    SHAPE ABUTMENT ;
    PORT
      LAYER M3 ;
      RECT 0 196.595 0.07 196.665 ;
    END
  END rw0_wd_in[404]
  PIN rw0_wd_in[405]
    DIRECTION INPUT ;
    USE SIGNAL ;
    SHAPE ABUTMENT ;
    PORT
      LAYER M3 ;
      RECT 0 197.015 0.07 197.085 ;
    END
  END rw0_wd_in[405]
  PIN rw0_wd_in[406]
    DIRECTION INPUT ;
    USE SIGNAL ;
    SHAPE ABUTMENT ;
    PORT
      LAYER M3 ;
      RECT 0 197.435 0.07 197.505 ;
    END
  END rw0_wd_in[406]
  PIN rw0_wd_in[407]
    DIRECTION INPUT ;
    USE SIGNAL ;
    SHAPE ABUTMENT ;
    PORT
      LAYER M3 ;
      RECT 0 197.855 0.07 197.925 ;
    END
  END rw0_wd_in[407]
  PIN rw0_wd_in[408]
    DIRECTION INPUT ;
    USE SIGNAL ;
    SHAPE ABUTMENT ;
    PORT
      LAYER M3 ;
      RECT 0 198.275 0.07 198.345 ;
    END
  END rw0_wd_in[408]
  PIN rw0_wd_in[409]
    DIRECTION INPUT ;
    USE SIGNAL ;
    SHAPE ABUTMENT ;
    PORT
      LAYER M3 ;
      RECT 0 198.695 0.07 198.765 ;
    END
  END rw0_wd_in[409]
  PIN rw0_wd_in[410]
    DIRECTION INPUT ;
    USE SIGNAL ;
    SHAPE ABUTMENT ;
    PORT
      LAYER M3 ;
      RECT 0 199.115 0.07 199.185 ;
    END
  END rw0_wd_in[410]
  PIN rw0_wd_in[411]
    DIRECTION INPUT ;
    USE SIGNAL ;
    SHAPE ABUTMENT ;
    PORT
      LAYER M3 ;
      RECT 0 199.535 0.07 199.605 ;
    END
  END rw0_wd_in[411]
  PIN rw0_wd_in[412]
    DIRECTION INPUT ;
    USE SIGNAL ;
    SHAPE ABUTMENT ;
    PORT
      LAYER M3 ;
      RECT 0 199.955 0.07 200.025 ;
    END
  END rw0_wd_in[412]
  PIN rw0_wd_in[413]
    DIRECTION INPUT ;
    USE SIGNAL ;
    SHAPE ABUTMENT ;
    PORT
      LAYER M3 ;
      RECT 0 200.375 0.07 200.445 ;
    END
  END rw0_wd_in[413]
  PIN rw0_wd_in[414]
    DIRECTION INPUT ;
    USE SIGNAL ;
    SHAPE ABUTMENT ;
    PORT
      LAYER M3 ;
      RECT 0 200.795 0.07 200.865 ;
    END
  END rw0_wd_in[414]
  PIN rw0_wd_in[415]
    DIRECTION INPUT ;
    USE SIGNAL ;
    SHAPE ABUTMENT ;
    PORT
      LAYER M3 ;
      RECT 0 201.215 0.07 201.285 ;
    END
  END rw0_wd_in[415]
  PIN rw0_wd_in[416]
    DIRECTION INPUT ;
    USE SIGNAL ;
    SHAPE ABUTMENT ;
    PORT
      LAYER M3 ;
      RECT 0 201.635 0.07 201.705 ;
    END
  END rw0_wd_in[416]
  PIN rw0_wd_in[417]
    DIRECTION INPUT ;
    USE SIGNAL ;
    SHAPE ABUTMENT ;
    PORT
      LAYER M3 ;
      RECT 0 202.055 0.07 202.125 ;
    END
  END rw0_wd_in[417]
  PIN rw0_wd_in[418]
    DIRECTION INPUT ;
    USE SIGNAL ;
    SHAPE ABUTMENT ;
    PORT
      LAYER M3 ;
      RECT 0 202.475 0.07 202.545 ;
    END
  END rw0_wd_in[418]
  PIN rw0_wd_in[419]
    DIRECTION INPUT ;
    USE SIGNAL ;
    SHAPE ABUTMENT ;
    PORT
      LAYER M3 ;
      RECT 0 202.895 0.07 202.965 ;
    END
  END rw0_wd_in[419]
  PIN rw0_wd_in[420]
    DIRECTION INPUT ;
    USE SIGNAL ;
    SHAPE ABUTMENT ;
    PORT
      LAYER M3 ;
      RECT 0 203.315 0.07 203.385 ;
    END
  END rw0_wd_in[420]
  PIN rw0_wd_in[421]
    DIRECTION INPUT ;
    USE SIGNAL ;
    SHAPE ABUTMENT ;
    PORT
      LAYER M3 ;
      RECT 0 203.735 0.07 203.805 ;
    END
  END rw0_wd_in[421]
  PIN rw0_wd_in[422]
    DIRECTION INPUT ;
    USE SIGNAL ;
    SHAPE ABUTMENT ;
    PORT
      LAYER M3 ;
      RECT 0 204.155 0.07 204.225 ;
    END
  END rw0_wd_in[422]
  PIN rw0_wd_in[423]
    DIRECTION INPUT ;
    USE SIGNAL ;
    SHAPE ABUTMENT ;
    PORT
      LAYER M3 ;
      RECT 0 204.575 0.07 204.645 ;
    END
  END rw0_wd_in[423]
  PIN rw0_wd_in[424]
    DIRECTION INPUT ;
    USE SIGNAL ;
    SHAPE ABUTMENT ;
    PORT
      LAYER M3 ;
      RECT 0 204.995 0.07 205.065 ;
    END
  END rw0_wd_in[424]
  PIN rw0_wd_in[425]
    DIRECTION INPUT ;
    USE SIGNAL ;
    SHAPE ABUTMENT ;
    PORT
      LAYER M3 ;
      RECT 0 205.415 0.07 205.485 ;
    END
  END rw0_wd_in[425]
  PIN rw0_wd_in[426]
    DIRECTION INPUT ;
    USE SIGNAL ;
    SHAPE ABUTMENT ;
    PORT
      LAYER M3 ;
      RECT 0 205.835 0.07 205.905 ;
    END
  END rw0_wd_in[426]
  PIN rw0_wd_in[427]
    DIRECTION INPUT ;
    USE SIGNAL ;
    SHAPE ABUTMENT ;
    PORT
      LAYER M3 ;
      RECT 0 206.255 0.07 206.325 ;
    END
  END rw0_wd_in[427]
  PIN rw0_wd_in[428]
    DIRECTION INPUT ;
    USE SIGNAL ;
    SHAPE ABUTMENT ;
    PORT
      LAYER M3 ;
      RECT 0 206.675 0.07 206.745 ;
    END
  END rw0_wd_in[428]
  PIN rw0_wd_in[429]
    DIRECTION INPUT ;
    USE SIGNAL ;
    SHAPE ABUTMENT ;
    PORT
      LAYER M3 ;
      RECT 0 207.095 0.07 207.165 ;
    END
  END rw0_wd_in[429]
  PIN rw0_wd_in[430]
    DIRECTION INPUT ;
    USE SIGNAL ;
    SHAPE ABUTMENT ;
    PORT
      LAYER M3 ;
      RECT 0 207.515 0.07 207.585 ;
    END
  END rw0_wd_in[430]
  PIN rw0_wd_in[431]
    DIRECTION INPUT ;
    USE SIGNAL ;
    SHAPE ABUTMENT ;
    PORT
      LAYER M3 ;
      RECT 0 207.935 0.07 208.005 ;
    END
  END rw0_wd_in[431]
  PIN rw0_wd_in[432]
    DIRECTION INPUT ;
    USE SIGNAL ;
    SHAPE ABUTMENT ;
    PORT
      LAYER M3 ;
      RECT 0 208.355 0.07 208.425 ;
    END
  END rw0_wd_in[432]
  PIN rw0_wd_in[433]
    DIRECTION INPUT ;
    USE SIGNAL ;
    SHAPE ABUTMENT ;
    PORT
      LAYER M3 ;
      RECT 0 208.775 0.07 208.845 ;
    END
  END rw0_wd_in[433]
  PIN rw0_wd_in[434]
    DIRECTION INPUT ;
    USE SIGNAL ;
    SHAPE ABUTMENT ;
    PORT
      LAYER M3 ;
      RECT 0 209.195 0.07 209.265 ;
    END
  END rw0_wd_in[434]
  PIN rw0_wd_in[435]
    DIRECTION INPUT ;
    USE SIGNAL ;
    SHAPE ABUTMENT ;
    PORT
      LAYER M3 ;
      RECT 0 209.615 0.07 209.685 ;
    END
  END rw0_wd_in[435]
  PIN rw0_wd_in[436]
    DIRECTION INPUT ;
    USE SIGNAL ;
    SHAPE ABUTMENT ;
    PORT
      LAYER M3 ;
      RECT 0 210.035 0.07 210.105 ;
    END
  END rw0_wd_in[436]
  PIN rw0_wd_in[437]
    DIRECTION INPUT ;
    USE SIGNAL ;
    SHAPE ABUTMENT ;
    PORT
      LAYER M3 ;
      RECT 0 210.455 0.07 210.525 ;
    END
  END rw0_wd_in[437]
  PIN rw0_wd_in[438]
    DIRECTION INPUT ;
    USE SIGNAL ;
    SHAPE ABUTMENT ;
    PORT
      LAYER M3 ;
      RECT 0 210.875 0.07 210.945 ;
    END
  END rw0_wd_in[438]
  PIN rw0_wd_in[439]
    DIRECTION INPUT ;
    USE SIGNAL ;
    SHAPE ABUTMENT ;
    PORT
      LAYER M3 ;
      RECT 0 211.295 0.07 211.365 ;
    END
  END rw0_wd_in[439]
  PIN rw0_wd_in[440]
    DIRECTION INPUT ;
    USE SIGNAL ;
    SHAPE ABUTMENT ;
    PORT
      LAYER M3 ;
      RECT 0 211.715 0.07 211.785 ;
    END
  END rw0_wd_in[440]
  PIN rw0_wd_in[441]
    DIRECTION INPUT ;
    USE SIGNAL ;
    SHAPE ABUTMENT ;
    PORT
      LAYER M3 ;
      RECT 0 212.135 0.07 212.205 ;
    END
  END rw0_wd_in[441]
  PIN rw0_wd_in[442]
    DIRECTION INPUT ;
    USE SIGNAL ;
    SHAPE ABUTMENT ;
    PORT
      LAYER M3 ;
      RECT 0 212.555 0.07 212.625 ;
    END
  END rw0_wd_in[442]
  PIN rw0_wd_in[443]
    DIRECTION INPUT ;
    USE SIGNAL ;
    SHAPE ABUTMENT ;
    PORT
      LAYER M3 ;
      RECT 0 212.975 0.07 213.045 ;
    END
  END rw0_wd_in[443]
  PIN rw0_wd_in[444]
    DIRECTION INPUT ;
    USE SIGNAL ;
    SHAPE ABUTMENT ;
    PORT
      LAYER M3 ;
      RECT 0 213.395 0.07 213.465 ;
    END
  END rw0_wd_in[444]
  PIN rw0_wd_in[445]
    DIRECTION INPUT ;
    USE SIGNAL ;
    SHAPE ABUTMENT ;
    PORT
      LAYER M3 ;
      RECT 0 213.815 0.07 213.885 ;
    END
  END rw0_wd_in[445]
  PIN rw0_wd_in[446]
    DIRECTION INPUT ;
    USE SIGNAL ;
    SHAPE ABUTMENT ;
    PORT
      LAYER M3 ;
      RECT 0 214.235 0.07 214.305 ;
    END
  END rw0_wd_in[446]
  PIN rw0_wd_in[447]
    DIRECTION INPUT ;
    USE SIGNAL ;
    SHAPE ABUTMENT ;
    PORT
      LAYER M3 ;
      RECT 0 214.655 0.07 214.725 ;
    END
  END rw0_wd_in[447]
  PIN rw0_wd_in[448]
    DIRECTION INPUT ;
    USE SIGNAL ;
    SHAPE ABUTMENT ;
    PORT
      LAYER M3 ;
      RECT 0 215.075 0.07 215.145 ;
    END
  END rw0_wd_in[448]
  PIN rw0_wd_in[449]
    DIRECTION INPUT ;
    USE SIGNAL ;
    SHAPE ABUTMENT ;
    PORT
      LAYER M3 ;
      RECT 0 215.495 0.07 215.565 ;
    END
  END rw0_wd_in[449]
  PIN rw0_wd_in[450]
    DIRECTION INPUT ;
    USE SIGNAL ;
    SHAPE ABUTMENT ;
    PORT
      LAYER M3 ;
      RECT 0 215.915 0.07 215.985 ;
    END
  END rw0_wd_in[450]
  PIN rw0_wd_in[451]
    DIRECTION INPUT ;
    USE SIGNAL ;
    SHAPE ABUTMENT ;
    PORT
      LAYER M3 ;
      RECT 0 216.335 0.07 216.405 ;
    END
  END rw0_wd_in[451]
  PIN rw0_wd_in[452]
    DIRECTION INPUT ;
    USE SIGNAL ;
    SHAPE ABUTMENT ;
    PORT
      LAYER M3 ;
      RECT 0 216.755 0.07 216.825 ;
    END
  END rw0_wd_in[452]
  PIN rw0_wd_in[453]
    DIRECTION INPUT ;
    USE SIGNAL ;
    SHAPE ABUTMENT ;
    PORT
      LAYER M3 ;
      RECT 0 217.175 0.07 217.245 ;
    END
  END rw0_wd_in[453]
  PIN rw0_wd_in[454]
    DIRECTION INPUT ;
    USE SIGNAL ;
    SHAPE ABUTMENT ;
    PORT
      LAYER M3 ;
      RECT 0 217.595 0.07 217.665 ;
    END
  END rw0_wd_in[454]
  PIN rw0_wd_in[455]
    DIRECTION INPUT ;
    USE SIGNAL ;
    SHAPE ABUTMENT ;
    PORT
      LAYER M3 ;
      RECT 0 218.015 0.07 218.085 ;
    END
  END rw0_wd_in[455]
  PIN rw0_wd_in[456]
    DIRECTION INPUT ;
    USE SIGNAL ;
    SHAPE ABUTMENT ;
    PORT
      LAYER M3 ;
      RECT 0 218.435 0.07 218.505 ;
    END
  END rw0_wd_in[456]
  PIN rw0_wd_in[457]
    DIRECTION INPUT ;
    USE SIGNAL ;
    SHAPE ABUTMENT ;
    PORT
      LAYER M3 ;
      RECT 0 218.855 0.07 218.925 ;
    END
  END rw0_wd_in[457]
  PIN rw0_wd_in[458]
    DIRECTION INPUT ;
    USE SIGNAL ;
    SHAPE ABUTMENT ;
    PORT
      LAYER M3 ;
      RECT 0 219.275 0.07 219.345 ;
    END
  END rw0_wd_in[458]
  PIN rw0_wd_in[459]
    DIRECTION INPUT ;
    USE SIGNAL ;
    SHAPE ABUTMENT ;
    PORT
      LAYER M3 ;
      RECT 0 219.695 0.07 219.765 ;
    END
  END rw0_wd_in[459]
  PIN rw0_wd_in[460]
    DIRECTION INPUT ;
    USE SIGNAL ;
    SHAPE ABUTMENT ;
    PORT
      LAYER M3 ;
      RECT 0 220.115 0.07 220.185 ;
    END
  END rw0_wd_in[460]
  PIN rw0_wd_in[461]
    DIRECTION INPUT ;
    USE SIGNAL ;
    SHAPE ABUTMENT ;
    PORT
      LAYER M3 ;
      RECT 0 220.535 0.07 220.605 ;
    END
  END rw0_wd_in[461]
  PIN rw0_wd_in[462]
    DIRECTION INPUT ;
    USE SIGNAL ;
    SHAPE ABUTMENT ;
    PORT
      LAYER M3 ;
      RECT 0 220.955 0.07 221.025 ;
    END
  END rw0_wd_in[462]
  PIN rw0_wd_in[463]
    DIRECTION INPUT ;
    USE SIGNAL ;
    SHAPE ABUTMENT ;
    PORT
      LAYER M3 ;
      RECT 0 221.375 0.07 221.445 ;
    END
  END rw0_wd_in[463]
  PIN rw0_wd_in[464]
    DIRECTION INPUT ;
    USE SIGNAL ;
    SHAPE ABUTMENT ;
    PORT
      LAYER M3 ;
      RECT 0 221.795 0.07 221.865 ;
    END
  END rw0_wd_in[464]
  PIN rw0_wd_in[465]
    DIRECTION INPUT ;
    USE SIGNAL ;
    SHAPE ABUTMENT ;
    PORT
      LAYER M3 ;
      RECT 0 222.215 0.07 222.285 ;
    END
  END rw0_wd_in[465]
  PIN rw0_wd_in[466]
    DIRECTION INPUT ;
    USE SIGNAL ;
    SHAPE ABUTMENT ;
    PORT
      LAYER M3 ;
      RECT 0 222.635 0.07 222.705 ;
    END
  END rw0_wd_in[466]
  PIN rw0_wd_in[467]
    DIRECTION INPUT ;
    USE SIGNAL ;
    SHAPE ABUTMENT ;
    PORT
      LAYER M3 ;
      RECT 0 223.055 0.07 223.125 ;
    END
  END rw0_wd_in[467]
  PIN rw0_wd_in[468]
    DIRECTION INPUT ;
    USE SIGNAL ;
    SHAPE ABUTMENT ;
    PORT
      LAYER M3 ;
      RECT 0 223.475 0.07 223.545 ;
    END
  END rw0_wd_in[468]
  PIN rw0_wd_in[469]
    DIRECTION INPUT ;
    USE SIGNAL ;
    SHAPE ABUTMENT ;
    PORT
      LAYER M3 ;
      RECT 0 223.895 0.07 223.965 ;
    END
  END rw0_wd_in[469]
  PIN rw0_wd_in[470]
    DIRECTION INPUT ;
    USE SIGNAL ;
    SHAPE ABUTMENT ;
    PORT
      LAYER M3 ;
      RECT 0 224.315 0.07 224.385 ;
    END
  END rw0_wd_in[470]
  PIN rw0_wd_in[471]
    DIRECTION INPUT ;
    USE SIGNAL ;
    SHAPE ABUTMENT ;
    PORT
      LAYER M3 ;
      RECT 0 224.735 0.07 224.805 ;
    END
  END rw0_wd_in[471]
  PIN rw0_wd_in[472]
    DIRECTION INPUT ;
    USE SIGNAL ;
    SHAPE ABUTMENT ;
    PORT
      LAYER M3 ;
      RECT 0 225.155 0.07 225.225 ;
    END
  END rw0_wd_in[472]
  PIN rw0_wd_in[473]
    DIRECTION INPUT ;
    USE SIGNAL ;
    SHAPE ABUTMENT ;
    PORT
      LAYER M3 ;
      RECT 0 225.575 0.07 225.645 ;
    END
  END rw0_wd_in[473]
  PIN rw0_wd_in[474]
    DIRECTION INPUT ;
    USE SIGNAL ;
    SHAPE ABUTMENT ;
    PORT
      LAYER M3 ;
      RECT 0 225.995 0.07 226.065 ;
    END
  END rw0_wd_in[474]
  PIN rw0_wd_in[475]
    DIRECTION INPUT ;
    USE SIGNAL ;
    SHAPE ABUTMENT ;
    PORT
      LAYER M3 ;
      RECT 0 226.415 0.07 226.485 ;
    END
  END rw0_wd_in[475]
  PIN rw0_wd_in[476]
    DIRECTION INPUT ;
    USE SIGNAL ;
    SHAPE ABUTMENT ;
    PORT
      LAYER M3 ;
      RECT 0 226.835 0.07 226.905 ;
    END
  END rw0_wd_in[476]
  PIN rw0_wd_in[477]
    DIRECTION INPUT ;
    USE SIGNAL ;
    SHAPE ABUTMENT ;
    PORT
      LAYER M3 ;
      RECT 0 227.255 0.07 227.325 ;
    END
  END rw0_wd_in[477]
  PIN rw0_wd_in[478]
    DIRECTION INPUT ;
    USE SIGNAL ;
    SHAPE ABUTMENT ;
    PORT
      LAYER M3 ;
      RECT 0 227.675 0.07 227.745 ;
    END
  END rw0_wd_in[478]
  PIN rw0_wd_in[479]
    DIRECTION INPUT ;
    USE SIGNAL ;
    SHAPE ABUTMENT ;
    PORT
      LAYER M3 ;
      RECT 0 228.095 0.07 228.165 ;
    END
  END rw0_wd_in[479]
  PIN rw0_wd_in[480]
    DIRECTION INPUT ;
    USE SIGNAL ;
    SHAPE ABUTMENT ;
    PORT
      LAYER M3 ;
      RECT 0 228.515 0.07 228.585 ;
    END
  END rw0_wd_in[480]
  PIN rw0_wd_in[481]
    DIRECTION INPUT ;
    USE SIGNAL ;
    SHAPE ABUTMENT ;
    PORT
      LAYER M3 ;
      RECT 0 228.935 0.07 229.005 ;
    END
  END rw0_wd_in[481]
  PIN rw0_wd_in[482]
    DIRECTION INPUT ;
    USE SIGNAL ;
    SHAPE ABUTMENT ;
    PORT
      LAYER M3 ;
      RECT 0 229.355 0.07 229.425 ;
    END
  END rw0_wd_in[482]
  PIN rw0_wd_in[483]
    DIRECTION INPUT ;
    USE SIGNAL ;
    SHAPE ABUTMENT ;
    PORT
      LAYER M3 ;
      RECT 0 229.775 0.07 229.845 ;
    END
  END rw0_wd_in[483]
  PIN rw0_wd_in[484]
    DIRECTION INPUT ;
    USE SIGNAL ;
    SHAPE ABUTMENT ;
    PORT
      LAYER M3 ;
      RECT 0 230.195 0.07 230.265 ;
    END
  END rw0_wd_in[484]
  PIN rw0_wd_in[485]
    DIRECTION INPUT ;
    USE SIGNAL ;
    SHAPE ABUTMENT ;
    PORT
      LAYER M3 ;
      RECT 0 230.615 0.07 230.685 ;
    END
  END rw0_wd_in[485]
  PIN rw0_wd_in[486]
    DIRECTION INPUT ;
    USE SIGNAL ;
    SHAPE ABUTMENT ;
    PORT
      LAYER M3 ;
      RECT 0 231.035 0.07 231.105 ;
    END
  END rw0_wd_in[486]
  PIN rw0_wd_in[487]
    DIRECTION INPUT ;
    USE SIGNAL ;
    SHAPE ABUTMENT ;
    PORT
      LAYER M3 ;
      RECT 0 231.455 0.07 231.525 ;
    END
  END rw0_wd_in[487]
  PIN rw0_wd_in[488]
    DIRECTION INPUT ;
    USE SIGNAL ;
    SHAPE ABUTMENT ;
    PORT
      LAYER M3 ;
      RECT 0 231.875 0.07 231.945 ;
    END
  END rw0_wd_in[488]
  PIN rw0_wd_in[489]
    DIRECTION INPUT ;
    USE SIGNAL ;
    SHAPE ABUTMENT ;
    PORT
      LAYER M3 ;
      RECT 0 232.295 0.07 232.365 ;
    END
  END rw0_wd_in[489]
  PIN rw0_wd_in[490]
    DIRECTION INPUT ;
    USE SIGNAL ;
    SHAPE ABUTMENT ;
    PORT
      LAYER M3 ;
      RECT 0 232.715 0.07 232.785 ;
    END
  END rw0_wd_in[490]
  PIN rw0_wd_in[491]
    DIRECTION INPUT ;
    USE SIGNAL ;
    SHAPE ABUTMENT ;
    PORT
      LAYER M3 ;
      RECT 0 233.135 0.07 233.205 ;
    END
  END rw0_wd_in[491]
  PIN rw0_wd_in[492]
    DIRECTION INPUT ;
    USE SIGNAL ;
    SHAPE ABUTMENT ;
    PORT
      LAYER M3 ;
      RECT 0 233.555 0.07 233.625 ;
    END
  END rw0_wd_in[492]
  PIN rw0_wd_in[493]
    DIRECTION INPUT ;
    USE SIGNAL ;
    SHAPE ABUTMENT ;
    PORT
      LAYER M3 ;
      RECT 0 233.975 0.07 234.045 ;
    END
  END rw0_wd_in[493]
  PIN rw0_wd_in[494]
    DIRECTION INPUT ;
    USE SIGNAL ;
    SHAPE ABUTMENT ;
    PORT
      LAYER M3 ;
      RECT 0 234.395 0.07 234.465 ;
    END
  END rw0_wd_in[494]
  PIN rw0_wd_in[495]
    DIRECTION INPUT ;
    USE SIGNAL ;
    SHAPE ABUTMENT ;
    PORT
      LAYER M3 ;
      RECT 0 234.815 0.07 234.885 ;
    END
  END rw0_wd_in[495]
  PIN rw0_wd_in[496]
    DIRECTION INPUT ;
    USE SIGNAL ;
    SHAPE ABUTMENT ;
    PORT
      LAYER M3 ;
      RECT 0 235.235 0.07 235.305 ;
    END
  END rw0_wd_in[496]
  PIN rw0_wd_in[497]
    DIRECTION INPUT ;
    USE SIGNAL ;
    SHAPE ABUTMENT ;
    PORT
      LAYER M3 ;
      RECT 0 235.655 0.07 235.725 ;
    END
  END rw0_wd_in[497]
  PIN rw0_wd_in[498]
    DIRECTION INPUT ;
    USE SIGNAL ;
    SHAPE ABUTMENT ;
    PORT
      LAYER M3 ;
      RECT 0 236.075 0.07 236.145 ;
    END
  END rw0_wd_in[498]
  PIN rw0_wd_in[499]
    DIRECTION INPUT ;
    USE SIGNAL ;
    SHAPE ABUTMENT ;
    PORT
      LAYER M3 ;
      RECT 0 236.495 0.07 236.565 ;
    END
  END rw0_wd_in[499]
  PIN rw0_wd_in[500]
    DIRECTION INPUT ;
    USE SIGNAL ;
    SHAPE ABUTMENT ;
    PORT
      LAYER M3 ;
      RECT 0 236.915 0.07 236.985 ;
    END
  END rw0_wd_in[500]
  PIN rw0_wd_in[501]
    DIRECTION INPUT ;
    USE SIGNAL ;
    SHAPE ABUTMENT ;
    PORT
      LAYER M3 ;
      RECT 0 237.335 0.07 237.405 ;
    END
  END rw0_wd_in[501]
  PIN rw0_wd_in[502]
    DIRECTION INPUT ;
    USE SIGNAL ;
    SHAPE ABUTMENT ;
    PORT
      LAYER M3 ;
      RECT 0 237.755 0.07 237.825 ;
    END
  END rw0_wd_in[502]
  PIN rw0_wd_in[503]
    DIRECTION INPUT ;
    USE SIGNAL ;
    SHAPE ABUTMENT ;
    PORT
      LAYER M3 ;
      RECT 0 238.175 0.07 238.245 ;
    END
  END rw0_wd_in[503]
  PIN rw0_wd_in[504]
    DIRECTION INPUT ;
    USE SIGNAL ;
    SHAPE ABUTMENT ;
    PORT
      LAYER M3 ;
      RECT 0 238.595 0.07 238.665 ;
    END
  END rw0_wd_in[504]
  PIN rw0_wd_in[505]
    DIRECTION INPUT ;
    USE SIGNAL ;
    SHAPE ABUTMENT ;
    PORT
      LAYER M3 ;
      RECT 0 239.015 0.07 239.085 ;
    END
  END rw0_wd_in[505]
  PIN rw0_wd_in[506]
    DIRECTION INPUT ;
    USE SIGNAL ;
    SHAPE ABUTMENT ;
    PORT
      LAYER M3 ;
      RECT 0 239.435 0.07 239.505 ;
    END
  END rw0_wd_in[506]
  PIN rw0_wd_in[507]
    DIRECTION INPUT ;
    USE SIGNAL ;
    SHAPE ABUTMENT ;
    PORT
      LAYER M3 ;
      RECT 0 239.855 0.07 239.925 ;
    END
  END rw0_wd_in[507]
  PIN rw0_wd_in[508]
    DIRECTION INPUT ;
    USE SIGNAL ;
    SHAPE ABUTMENT ;
    PORT
      LAYER M3 ;
      RECT 0 240.275 0.07 240.345 ;
    END
  END rw0_wd_in[508]
  PIN rw0_wd_in[509]
    DIRECTION INPUT ;
    USE SIGNAL ;
    SHAPE ABUTMENT ;
    PORT
      LAYER M3 ;
      RECT 0 240.695 0.07 240.765 ;
    END
  END rw0_wd_in[509]
  PIN rw0_wd_in[510]
    DIRECTION INPUT ;
    USE SIGNAL ;
    SHAPE ABUTMENT ;
    PORT
      LAYER M3 ;
      RECT 0 241.115 0.07 241.185 ;
    END
  END rw0_wd_in[510]
  PIN rw0_wd_in[511]
    DIRECTION INPUT ;
    USE SIGNAL ;
    SHAPE ABUTMENT ;
    PORT
      LAYER M3 ;
      RECT 0 241.535 0.07 241.605 ;
    END
  END rw0_wd_in[511]
  PIN rw0_rd_out[0]
    DIRECTION OUTPUT ;
    USE SIGNAL ;
    SHAPE ABUTMENT ;
    PORT
      LAYER M3 ;
      RECT 0 241.955 0.07 242.025 ;
    END
  END rw0_rd_out[0]
  PIN rw0_rd_out[1]
    DIRECTION OUTPUT ;
    USE SIGNAL ;
    SHAPE ABUTMENT ;
    PORT
      LAYER M3 ;
      RECT 0 242.375 0.07 242.445 ;
    END
  END rw0_rd_out[1]
  PIN rw0_rd_out[2]
    DIRECTION OUTPUT ;
    USE SIGNAL ;
    SHAPE ABUTMENT ;
    PORT
      LAYER M3 ;
      RECT 0 242.795 0.07 242.865 ;
    END
  END rw0_rd_out[2]
  PIN rw0_rd_out[3]
    DIRECTION OUTPUT ;
    USE SIGNAL ;
    SHAPE ABUTMENT ;
    PORT
      LAYER M3 ;
      RECT 0 243.215 0.07 243.285 ;
    END
  END rw0_rd_out[3]
  PIN rw0_rd_out[4]
    DIRECTION OUTPUT ;
    USE SIGNAL ;
    SHAPE ABUTMENT ;
    PORT
      LAYER M3 ;
      RECT 0 243.635 0.07 243.705 ;
    END
  END rw0_rd_out[4]
  PIN rw0_rd_out[5]
    DIRECTION OUTPUT ;
    USE SIGNAL ;
    SHAPE ABUTMENT ;
    PORT
      LAYER M3 ;
      RECT 0 244.055 0.07 244.125 ;
    END
  END rw0_rd_out[5]
  PIN rw0_rd_out[6]
    DIRECTION OUTPUT ;
    USE SIGNAL ;
    SHAPE ABUTMENT ;
    PORT
      LAYER M3 ;
      RECT 0 244.475 0.07 244.545 ;
    END
  END rw0_rd_out[6]
  PIN rw0_rd_out[7]
    DIRECTION OUTPUT ;
    USE SIGNAL ;
    SHAPE ABUTMENT ;
    PORT
      LAYER M3 ;
      RECT 0 244.895 0.07 244.965 ;
    END
  END rw0_rd_out[7]
  PIN rw0_rd_out[8]
    DIRECTION OUTPUT ;
    USE SIGNAL ;
    SHAPE ABUTMENT ;
    PORT
      LAYER M3 ;
      RECT 0 245.315 0.07 245.385 ;
    END
  END rw0_rd_out[8]
  PIN rw0_rd_out[9]
    DIRECTION OUTPUT ;
    USE SIGNAL ;
    SHAPE ABUTMENT ;
    PORT
      LAYER M3 ;
      RECT 0 245.735 0.07 245.805 ;
    END
  END rw0_rd_out[9]
  PIN rw0_rd_out[10]
    DIRECTION OUTPUT ;
    USE SIGNAL ;
    SHAPE ABUTMENT ;
    PORT
      LAYER M3 ;
      RECT 0 246.155 0.07 246.225 ;
    END
  END rw0_rd_out[10]
  PIN rw0_rd_out[11]
    DIRECTION OUTPUT ;
    USE SIGNAL ;
    SHAPE ABUTMENT ;
    PORT
      LAYER M3 ;
      RECT 0 246.575 0.07 246.645 ;
    END
  END rw0_rd_out[11]
  PIN rw0_rd_out[12]
    DIRECTION OUTPUT ;
    USE SIGNAL ;
    SHAPE ABUTMENT ;
    PORT
      LAYER M3 ;
      RECT 0 246.995 0.07 247.065 ;
    END
  END rw0_rd_out[12]
  PIN rw0_rd_out[13]
    DIRECTION OUTPUT ;
    USE SIGNAL ;
    SHAPE ABUTMENT ;
    PORT
      LAYER M3 ;
      RECT 0 247.415 0.07 247.485 ;
    END
  END rw0_rd_out[13]
  PIN rw0_rd_out[14]
    DIRECTION OUTPUT ;
    USE SIGNAL ;
    SHAPE ABUTMENT ;
    PORT
      LAYER M3 ;
      RECT 0 247.835 0.07 247.905 ;
    END
  END rw0_rd_out[14]
  PIN rw0_rd_out[15]
    DIRECTION OUTPUT ;
    USE SIGNAL ;
    SHAPE ABUTMENT ;
    PORT
      LAYER M3 ;
      RECT 0 248.255 0.07 248.325 ;
    END
  END rw0_rd_out[15]
  PIN rw0_rd_out[16]
    DIRECTION OUTPUT ;
    USE SIGNAL ;
    SHAPE ABUTMENT ;
    PORT
      LAYER M3 ;
      RECT 0 248.675 0.07 248.745 ;
    END
  END rw0_rd_out[16]
  PIN rw0_rd_out[17]
    DIRECTION OUTPUT ;
    USE SIGNAL ;
    SHAPE ABUTMENT ;
    PORT
      LAYER M3 ;
      RECT 0 249.095 0.07 249.165 ;
    END
  END rw0_rd_out[17]
  PIN rw0_rd_out[18]
    DIRECTION OUTPUT ;
    USE SIGNAL ;
    SHAPE ABUTMENT ;
    PORT
      LAYER M3 ;
      RECT 0 249.515 0.07 249.585 ;
    END
  END rw0_rd_out[18]
  PIN rw0_rd_out[19]
    DIRECTION OUTPUT ;
    USE SIGNAL ;
    SHAPE ABUTMENT ;
    PORT
      LAYER M3 ;
      RECT 0 249.935 0.07 250.005 ;
    END
  END rw0_rd_out[19]
  PIN rw0_rd_out[20]
    DIRECTION OUTPUT ;
    USE SIGNAL ;
    SHAPE ABUTMENT ;
    PORT
      LAYER M3 ;
      RECT 0 250.355 0.07 250.425 ;
    END
  END rw0_rd_out[20]
  PIN rw0_rd_out[21]
    DIRECTION OUTPUT ;
    USE SIGNAL ;
    SHAPE ABUTMENT ;
    PORT
      LAYER M3 ;
      RECT 0 250.775 0.07 250.845 ;
    END
  END rw0_rd_out[21]
  PIN rw0_rd_out[22]
    DIRECTION OUTPUT ;
    USE SIGNAL ;
    SHAPE ABUTMENT ;
    PORT
      LAYER M3 ;
      RECT 0 251.195 0.07 251.265 ;
    END
  END rw0_rd_out[22]
  PIN rw0_rd_out[23]
    DIRECTION OUTPUT ;
    USE SIGNAL ;
    SHAPE ABUTMENT ;
    PORT
      LAYER M3 ;
      RECT 0 251.615 0.07 251.685 ;
    END
  END rw0_rd_out[23]
  PIN rw0_rd_out[24]
    DIRECTION OUTPUT ;
    USE SIGNAL ;
    SHAPE ABUTMENT ;
    PORT
      LAYER M3 ;
      RECT 0 252.035 0.07 252.105 ;
    END
  END rw0_rd_out[24]
  PIN rw0_rd_out[25]
    DIRECTION OUTPUT ;
    USE SIGNAL ;
    SHAPE ABUTMENT ;
    PORT
      LAYER M3 ;
      RECT 0 252.455 0.07 252.525 ;
    END
  END rw0_rd_out[25]
  PIN rw0_rd_out[26]
    DIRECTION OUTPUT ;
    USE SIGNAL ;
    SHAPE ABUTMENT ;
    PORT
      LAYER M3 ;
      RECT 0 252.875 0.07 252.945 ;
    END
  END rw0_rd_out[26]
  PIN rw0_rd_out[27]
    DIRECTION OUTPUT ;
    USE SIGNAL ;
    SHAPE ABUTMENT ;
    PORT
      LAYER M3 ;
      RECT 0 253.295 0.07 253.365 ;
    END
  END rw0_rd_out[27]
  PIN rw0_rd_out[28]
    DIRECTION OUTPUT ;
    USE SIGNAL ;
    SHAPE ABUTMENT ;
    PORT
      LAYER M3 ;
      RECT 0 253.715 0.07 253.785 ;
    END
  END rw0_rd_out[28]
  PIN rw0_rd_out[29]
    DIRECTION OUTPUT ;
    USE SIGNAL ;
    SHAPE ABUTMENT ;
    PORT
      LAYER M3 ;
      RECT 0 254.135 0.07 254.205 ;
    END
  END rw0_rd_out[29]
  PIN rw0_rd_out[30]
    DIRECTION OUTPUT ;
    USE SIGNAL ;
    SHAPE ABUTMENT ;
    PORT
      LAYER M3 ;
      RECT 0 254.555 0.07 254.625 ;
    END
  END rw0_rd_out[30]
  PIN rw0_rd_out[31]
    DIRECTION OUTPUT ;
    USE SIGNAL ;
    SHAPE ABUTMENT ;
    PORT
      LAYER M3 ;
      RECT 0 254.975 0.07 255.045 ;
    END
  END rw0_rd_out[31]
  PIN rw0_rd_out[32]
    DIRECTION OUTPUT ;
    USE SIGNAL ;
    SHAPE ABUTMENT ;
    PORT
      LAYER M3 ;
      RECT 0 255.395 0.07 255.465 ;
    END
  END rw0_rd_out[32]
  PIN rw0_rd_out[33]
    DIRECTION OUTPUT ;
    USE SIGNAL ;
    SHAPE ABUTMENT ;
    PORT
      LAYER M3 ;
      RECT 0 255.815 0.07 255.885 ;
    END
  END rw0_rd_out[33]
  PIN rw0_rd_out[34]
    DIRECTION OUTPUT ;
    USE SIGNAL ;
    SHAPE ABUTMENT ;
    PORT
      LAYER M3 ;
      RECT 0 256.235 0.07 256.305 ;
    END
  END rw0_rd_out[34]
  PIN rw0_rd_out[35]
    DIRECTION OUTPUT ;
    USE SIGNAL ;
    SHAPE ABUTMENT ;
    PORT
      LAYER M3 ;
      RECT 0 256.655 0.07 256.725 ;
    END
  END rw0_rd_out[35]
  PIN rw0_rd_out[36]
    DIRECTION OUTPUT ;
    USE SIGNAL ;
    SHAPE ABUTMENT ;
    PORT
      LAYER M3 ;
      RECT 0 257.075 0.07 257.145 ;
    END
  END rw0_rd_out[36]
  PIN rw0_rd_out[37]
    DIRECTION OUTPUT ;
    USE SIGNAL ;
    SHAPE ABUTMENT ;
    PORT
      LAYER M3 ;
      RECT 0 257.495 0.07 257.565 ;
    END
  END rw0_rd_out[37]
  PIN rw0_rd_out[38]
    DIRECTION OUTPUT ;
    USE SIGNAL ;
    SHAPE ABUTMENT ;
    PORT
      LAYER M3 ;
      RECT 0 257.915 0.07 257.985 ;
    END
  END rw0_rd_out[38]
  PIN rw0_rd_out[39]
    DIRECTION OUTPUT ;
    USE SIGNAL ;
    SHAPE ABUTMENT ;
    PORT
      LAYER M3 ;
      RECT 0 258.335 0.07 258.405 ;
    END
  END rw0_rd_out[39]
  PIN rw0_rd_out[40]
    DIRECTION OUTPUT ;
    USE SIGNAL ;
    SHAPE ABUTMENT ;
    PORT
      LAYER M3 ;
      RECT 0 258.755 0.07 258.825 ;
    END
  END rw0_rd_out[40]
  PIN rw0_rd_out[41]
    DIRECTION OUTPUT ;
    USE SIGNAL ;
    SHAPE ABUTMENT ;
    PORT
      LAYER M3 ;
      RECT 0 259.175 0.07 259.245 ;
    END
  END rw0_rd_out[41]
  PIN rw0_rd_out[42]
    DIRECTION OUTPUT ;
    USE SIGNAL ;
    SHAPE ABUTMENT ;
    PORT
      LAYER M3 ;
      RECT 0 259.595 0.07 259.665 ;
    END
  END rw0_rd_out[42]
  PIN rw0_rd_out[43]
    DIRECTION OUTPUT ;
    USE SIGNAL ;
    SHAPE ABUTMENT ;
    PORT
      LAYER M3 ;
      RECT 0 260.015 0.07 260.085 ;
    END
  END rw0_rd_out[43]
  PIN rw0_rd_out[44]
    DIRECTION OUTPUT ;
    USE SIGNAL ;
    SHAPE ABUTMENT ;
    PORT
      LAYER M3 ;
      RECT 0 260.435 0.07 260.505 ;
    END
  END rw0_rd_out[44]
  PIN rw0_rd_out[45]
    DIRECTION OUTPUT ;
    USE SIGNAL ;
    SHAPE ABUTMENT ;
    PORT
      LAYER M3 ;
      RECT 0 260.855 0.07 260.925 ;
    END
  END rw0_rd_out[45]
  PIN rw0_rd_out[46]
    DIRECTION OUTPUT ;
    USE SIGNAL ;
    SHAPE ABUTMENT ;
    PORT
      LAYER M3 ;
      RECT 0 261.275 0.07 261.345 ;
    END
  END rw0_rd_out[46]
  PIN rw0_rd_out[47]
    DIRECTION OUTPUT ;
    USE SIGNAL ;
    SHAPE ABUTMENT ;
    PORT
      LAYER M3 ;
      RECT 0 261.695 0.07 261.765 ;
    END
  END rw0_rd_out[47]
  PIN rw0_rd_out[48]
    DIRECTION OUTPUT ;
    USE SIGNAL ;
    SHAPE ABUTMENT ;
    PORT
      LAYER M3 ;
      RECT 0 262.115 0.07 262.185 ;
    END
  END rw0_rd_out[48]
  PIN rw0_rd_out[49]
    DIRECTION OUTPUT ;
    USE SIGNAL ;
    SHAPE ABUTMENT ;
    PORT
      LAYER M3 ;
      RECT 0 262.535 0.07 262.605 ;
    END
  END rw0_rd_out[49]
  PIN rw0_rd_out[50]
    DIRECTION OUTPUT ;
    USE SIGNAL ;
    SHAPE ABUTMENT ;
    PORT
      LAYER M3 ;
      RECT 0 262.955 0.07 263.025 ;
    END
  END rw0_rd_out[50]
  PIN rw0_rd_out[51]
    DIRECTION OUTPUT ;
    USE SIGNAL ;
    SHAPE ABUTMENT ;
    PORT
      LAYER M3 ;
      RECT 0 263.375 0.07 263.445 ;
    END
  END rw0_rd_out[51]
  PIN rw0_rd_out[52]
    DIRECTION OUTPUT ;
    USE SIGNAL ;
    SHAPE ABUTMENT ;
    PORT
      LAYER M3 ;
      RECT 0 263.795 0.07 263.865 ;
    END
  END rw0_rd_out[52]
  PIN rw0_rd_out[53]
    DIRECTION OUTPUT ;
    USE SIGNAL ;
    SHAPE ABUTMENT ;
    PORT
      LAYER M3 ;
      RECT 0 264.215 0.07 264.285 ;
    END
  END rw0_rd_out[53]
  PIN rw0_rd_out[54]
    DIRECTION OUTPUT ;
    USE SIGNAL ;
    SHAPE ABUTMENT ;
    PORT
      LAYER M3 ;
      RECT 0 264.635 0.07 264.705 ;
    END
  END rw0_rd_out[54]
  PIN rw0_rd_out[55]
    DIRECTION OUTPUT ;
    USE SIGNAL ;
    SHAPE ABUTMENT ;
    PORT
      LAYER M3 ;
      RECT 0 265.055 0.07 265.125 ;
    END
  END rw0_rd_out[55]
  PIN rw0_rd_out[56]
    DIRECTION OUTPUT ;
    USE SIGNAL ;
    SHAPE ABUTMENT ;
    PORT
      LAYER M3 ;
      RECT 0 265.475 0.07 265.545 ;
    END
  END rw0_rd_out[56]
  PIN rw0_rd_out[57]
    DIRECTION OUTPUT ;
    USE SIGNAL ;
    SHAPE ABUTMENT ;
    PORT
      LAYER M3 ;
      RECT 0 265.895 0.07 265.965 ;
    END
  END rw0_rd_out[57]
  PIN rw0_rd_out[58]
    DIRECTION OUTPUT ;
    USE SIGNAL ;
    SHAPE ABUTMENT ;
    PORT
      LAYER M3 ;
      RECT 0 266.315 0.07 266.385 ;
    END
  END rw0_rd_out[58]
  PIN rw0_rd_out[59]
    DIRECTION OUTPUT ;
    USE SIGNAL ;
    SHAPE ABUTMENT ;
    PORT
      LAYER M3 ;
      RECT 0 266.735 0.07 266.805 ;
    END
  END rw0_rd_out[59]
  PIN rw0_rd_out[60]
    DIRECTION OUTPUT ;
    USE SIGNAL ;
    SHAPE ABUTMENT ;
    PORT
      LAYER M3 ;
      RECT 0 267.155 0.07 267.225 ;
    END
  END rw0_rd_out[60]
  PIN rw0_rd_out[61]
    DIRECTION OUTPUT ;
    USE SIGNAL ;
    SHAPE ABUTMENT ;
    PORT
      LAYER M3 ;
      RECT 0 267.575 0.07 267.645 ;
    END
  END rw0_rd_out[61]
  PIN rw0_rd_out[62]
    DIRECTION OUTPUT ;
    USE SIGNAL ;
    SHAPE ABUTMENT ;
    PORT
      LAYER M3 ;
      RECT 0 267.995 0.07 268.065 ;
    END
  END rw0_rd_out[62]
  PIN rw0_rd_out[63]
    DIRECTION OUTPUT ;
    USE SIGNAL ;
    SHAPE ABUTMENT ;
    PORT
      LAYER M3 ;
      RECT 0 268.415 0.07 268.485 ;
    END
  END rw0_rd_out[63]
  PIN rw0_rd_out[64]
    DIRECTION OUTPUT ;
    USE SIGNAL ;
    SHAPE ABUTMENT ;
    PORT
      LAYER M3 ;
      RECT 0 268.835 0.07 268.905 ;
    END
  END rw0_rd_out[64]
  PIN rw0_rd_out[65]
    DIRECTION OUTPUT ;
    USE SIGNAL ;
    SHAPE ABUTMENT ;
    PORT
      LAYER M3 ;
      RECT 0 269.255 0.07 269.325 ;
    END
  END rw0_rd_out[65]
  PIN rw0_rd_out[66]
    DIRECTION OUTPUT ;
    USE SIGNAL ;
    SHAPE ABUTMENT ;
    PORT
      LAYER M3 ;
      RECT 0 269.675 0.07 269.745 ;
    END
  END rw0_rd_out[66]
  PIN rw0_rd_out[67]
    DIRECTION OUTPUT ;
    USE SIGNAL ;
    SHAPE ABUTMENT ;
    PORT
      LAYER M3 ;
      RECT 0 270.095 0.07 270.165 ;
    END
  END rw0_rd_out[67]
  PIN rw0_rd_out[68]
    DIRECTION OUTPUT ;
    USE SIGNAL ;
    SHAPE ABUTMENT ;
    PORT
      LAYER M3 ;
      RECT 0 270.515 0.07 270.585 ;
    END
  END rw0_rd_out[68]
  PIN rw0_rd_out[69]
    DIRECTION OUTPUT ;
    USE SIGNAL ;
    SHAPE ABUTMENT ;
    PORT
      LAYER M3 ;
      RECT 0 270.935 0.07 271.005 ;
    END
  END rw0_rd_out[69]
  PIN rw0_rd_out[70]
    DIRECTION OUTPUT ;
    USE SIGNAL ;
    SHAPE ABUTMENT ;
    PORT
      LAYER M3 ;
      RECT 0 271.355 0.07 271.425 ;
    END
  END rw0_rd_out[70]
  PIN rw0_rd_out[71]
    DIRECTION OUTPUT ;
    USE SIGNAL ;
    SHAPE ABUTMENT ;
    PORT
      LAYER M3 ;
      RECT 0 271.775 0.07 271.845 ;
    END
  END rw0_rd_out[71]
  PIN rw0_rd_out[72]
    DIRECTION OUTPUT ;
    USE SIGNAL ;
    SHAPE ABUTMENT ;
    PORT
      LAYER M3 ;
      RECT 0 272.195 0.07 272.265 ;
    END
  END rw0_rd_out[72]
  PIN rw0_rd_out[73]
    DIRECTION OUTPUT ;
    USE SIGNAL ;
    SHAPE ABUTMENT ;
    PORT
      LAYER M3 ;
      RECT 0 272.615 0.07 272.685 ;
    END
  END rw0_rd_out[73]
  PIN rw0_rd_out[74]
    DIRECTION OUTPUT ;
    USE SIGNAL ;
    SHAPE ABUTMENT ;
    PORT
      LAYER M3 ;
      RECT 0 273.035 0.07 273.105 ;
    END
  END rw0_rd_out[74]
  PIN rw0_rd_out[75]
    DIRECTION OUTPUT ;
    USE SIGNAL ;
    SHAPE ABUTMENT ;
    PORT
      LAYER M3 ;
      RECT 0 273.455 0.07 273.525 ;
    END
  END rw0_rd_out[75]
  PIN rw0_rd_out[76]
    DIRECTION OUTPUT ;
    USE SIGNAL ;
    SHAPE ABUTMENT ;
    PORT
      LAYER M3 ;
      RECT 0 273.875 0.07 273.945 ;
    END
  END rw0_rd_out[76]
  PIN rw0_rd_out[77]
    DIRECTION OUTPUT ;
    USE SIGNAL ;
    SHAPE ABUTMENT ;
    PORT
      LAYER M3 ;
      RECT 0 274.295 0.07 274.365 ;
    END
  END rw0_rd_out[77]
  PIN rw0_rd_out[78]
    DIRECTION OUTPUT ;
    USE SIGNAL ;
    SHAPE ABUTMENT ;
    PORT
      LAYER M3 ;
      RECT 0 274.715 0.07 274.785 ;
    END
  END rw0_rd_out[78]
  PIN rw0_rd_out[79]
    DIRECTION OUTPUT ;
    USE SIGNAL ;
    SHAPE ABUTMENT ;
    PORT
      LAYER M3 ;
      RECT 0 275.135 0.07 275.205 ;
    END
  END rw0_rd_out[79]
  PIN rw0_rd_out[80]
    DIRECTION OUTPUT ;
    USE SIGNAL ;
    SHAPE ABUTMENT ;
    PORT
      LAYER M3 ;
      RECT 0 275.555 0.07 275.625 ;
    END
  END rw0_rd_out[80]
  PIN rw0_rd_out[81]
    DIRECTION OUTPUT ;
    USE SIGNAL ;
    SHAPE ABUTMENT ;
    PORT
      LAYER M3 ;
      RECT 0 275.975 0.07 276.045 ;
    END
  END rw0_rd_out[81]
  PIN rw0_rd_out[82]
    DIRECTION OUTPUT ;
    USE SIGNAL ;
    SHAPE ABUTMENT ;
    PORT
      LAYER M3 ;
      RECT 0 276.395 0.07 276.465 ;
    END
  END rw0_rd_out[82]
  PIN rw0_rd_out[83]
    DIRECTION OUTPUT ;
    USE SIGNAL ;
    SHAPE ABUTMENT ;
    PORT
      LAYER M3 ;
      RECT 0 276.815 0.07 276.885 ;
    END
  END rw0_rd_out[83]
  PIN rw0_rd_out[84]
    DIRECTION OUTPUT ;
    USE SIGNAL ;
    SHAPE ABUTMENT ;
    PORT
      LAYER M3 ;
      RECT 0 277.235 0.07 277.305 ;
    END
  END rw0_rd_out[84]
  PIN rw0_rd_out[85]
    DIRECTION OUTPUT ;
    USE SIGNAL ;
    SHAPE ABUTMENT ;
    PORT
      LAYER M3 ;
      RECT 0 277.655 0.07 277.725 ;
    END
  END rw0_rd_out[85]
  PIN rw0_rd_out[86]
    DIRECTION OUTPUT ;
    USE SIGNAL ;
    SHAPE ABUTMENT ;
    PORT
      LAYER M3 ;
      RECT 0 278.075 0.07 278.145 ;
    END
  END rw0_rd_out[86]
  PIN rw0_rd_out[87]
    DIRECTION OUTPUT ;
    USE SIGNAL ;
    SHAPE ABUTMENT ;
    PORT
      LAYER M3 ;
      RECT 0 278.495 0.07 278.565 ;
    END
  END rw0_rd_out[87]
  PIN rw0_rd_out[88]
    DIRECTION OUTPUT ;
    USE SIGNAL ;
    SHAPE ABUTMENT ;
    PORT
      LAYER M3 ;
      RECT 0 278.915 0.07 278.985 ;
    END
  END rw0_rd_out[88]
  PIN rw0_rd_out[89]
    DIRECTION OUTPUT ;
    USE SIGNAL ;
    SHAPE ABUTMENT ;
    PORT
      LAYER M3 ;
      RECT 0 279.335 0.07 279.405 ;
    END
  END rw0_rd_out[89]
  PIN rw0_rd_out[90]
    DIRECTION OUTPUT ;
    USE SIGNAL ;
    SHAPE ABUTMENT ;
    PORT
      LAYER M3 ;
      RECT 0 279.755 0.07 279.825 ;
    END
  END rw0_rd_out[90]
  PIN rw0_rd_out[91]
    DIRECTION OUTPUT ;
    USE SIGNAL ;
    SHAPE ABUTMENT ;
    PORT
      LAYER M3 ;
      RECT 0 280.175 0.07 280.245 ;
    END
  END rw0_rd_out[91]
  PIN rw0_rd_out[92]
    DIRECTION OUTPUT ;
    USE SIGNAL ;
    SHAPE ABUTMENT ;
    PORT
      LAYER M3 ;
      RECT 0 280.595 0.07 280.665 ;
    END
  END rw0_rd_out[92]
  PIN rw0_rd_out[93]
    DIRECTION OUTPUT ;
    USE SIGNAL ;
    SHAPE ABUTMENT ;
    PORT
      LAYER M3 ;
      RECT 0 281.015 0.07 281.085 ;
    END
  END rw0_rd_out[93]
  PIN rw0_rd_out[94]
    DIRECTION OUTPUT ;
    USE SIGNAL ;
    SHAPE ABUTMENT ;
    PORT
      LAYER M3 ;
      RECT 0 281.435 0.07 281.505 ;
    END
  END rw0_rd_out[94]
  PIN rw0_rd_out[95]
    DIRECTION OUTPUT ;
    USE SIGNAL ;
    SHAPE ABUTMENT ;
    PORT
      LAYER M3 ;
      RECT 0 281.855 0.07 281.925 ;
    END
  END rw0_rd_out[95]
  PIN rw0_rd_out[96]
    DIRECTION OUTPUT ;
    USE SIGNAL ;
    SHAPE ABUTMENT ;
    PORT
      LAYER M3 ;
      RECT 0 282.275 0.07 282.345 ;
    END
  END rw0_rd_out[96]
  PIN rw0_rd_out[97]
    DIRECTION OUTPUT ;
    USE SIGNAL ;
    SHAPE ABUTMENT ;
    PORT
      LAYER M3 ;
      RECT 0 282.695 0.07 282.765 ;
    END
  END rw0_rd_out[97]
  PIN rw0_rd_out[98]
    DIRECTION OUTPUT ;
    USE SIGNAL ;
    SHAPE ABUTMENT ;
    PORT
      LAYER M3 ;
      RECT 0 283.115 0.07 283.185 ;
    END
  END rw0_rd_out[98]
  PIN rw0_rd_out[99]
    DIRECTION OUTPUT ;
    USE SIGNAL ;
    SHAPE ABUTMENT ;
    PORT
      LAYER M3 ;
      RECT 0 283.535 0.07 283.605 ;
    END
  END rw0_rd_out[99]
  PIN rw0_rd_out[100]
    DIRECTION OUTPUT ;
    USE SIGNAL ;
    SHAPE ABUTMENT ;
    PORT
      LAYER M3 ;
      RECT 0 283.955 0.07 284.025 ;
    END
  END rw0_rd_out[100]
  PIN rw0_rd_out[101]
    DIRECTION OUTPUT ;
    USE SIGNAL ;
    SHAPE ABUTMENT ;
    PORT
      LAYER M3 ;
      RECT 0 284.375 0.07 284.445 ;
    END
  END rw0_rd_out[101]
  PIN rw0_rd_out[102]
    DIRECTION OUTPUT ;
    USE SIGNAL ;
    SHAPE ABUTMENT ;
    PORT
      LAYER M3 ;
      RECT 0 284.795 0.07 284.865 ;
    END
  END rw0_rd_out[102]
  PIN rw0_rd_out[103]
    DIRECTION OUTPUT ;
    USE SIGNAL ;
    SHAPE ABUTMENT ;
    PORT
      LAYER M3 ;
      RECT 0 285.215 0.07 285.285 ;
    END
  END rw0_rd_out[103]
  PIN rw0_rd_out[104]
    DIRECTION OUTPUT ;
    USE SIGNAL ;
    SHAPE ABUTMENT ;
    PORT
      LAYER M3 ;
      RECT 0 285.635 0.07 285.705 ;
    END
  END rw0_rd_out[104]
  PIN rw0_rd_out[105]
    DIRECTION OUTPUT ;
    USE SIGNAL ;
    SHAPE ABUTMENT ;
    PORT
      LAYER M3 ;
      RECT 0 286.055 0.07 286.125 ;
    END
  END rw0_rd_out[105]
  PIN rw0_rd_out[106]
    DIRECTION OUTPUT ;
    USE SIGNAL ;
    SHAPE ABUTMENT ;
    PORT
      LAYER M3 ;
      RECT 0 286.475 0.07 286.545 ;
    END
  END rw0_rd_out[106]
  PIN rw0_rd_out[107]
    DIRECTION OUTPUT ;
    USE SIGNAL ;
    SHAPE ABUTMENT ;
    PORT
      LAYER M3 ;
      RECT 0 286.895 0.07 286.965 ;
    END
  END rw0_rd_out[107]
  PIN rw0_rd_out[108]
    DIRECTION OUTPUT ;
    USE SIGNAL ;
    SHAPE ABUTMENT ;
    PORT
      LAYER M3 ;
      RECT 0 287.315 0.07 287.385 ;
    END
  END rw0_rd_out[108]
  PIN rw0_rd_out[109]
    DIRECTION OUTPUT ;
    USE SIGNAL ;
    SHAPE ABUTMENT ;
    PORT
      LAYER M3 ;
      RECT 0 287.735 0.07 287.805 ;
    END
  END rw0_rd_out[109]
  PIN rw0_rd_out[110]
    DIRECTION OUTPUT ;
    USE SIGNAL ;
    SHAPE ABUTMENT ;
    PORT
      LAYER M3 ;
      RECT 0 288.155 0.07 288.225 ;
    END
  END rw0_rd_out[110]
  PIN rw0_rd_out[111]
    DIRECTION OUTPUT ;
    USE SIGNAL ;
    SHAPE ABUTMENT ;
    PORT
      LAYER M3 ;
      RECT 0 288.575 0.07 288.645 ;
    END
  END rw0_rd_out[111]
  PIN rw0_rd_out[112]
    DIRECTION OUTPUT ;
    USE SIGNAL ;
    SHAPE ABUTMENT ;
    PORT
      LAYER M3 ;
      RECT 0 288.995 0.07 289.065 ;
    END
  END rw0_rd_out[112]
  PIN rw0_rd_out[113]
    DIRECTION OUTPUT ;
    USE SIGNAL ;
    SHAPE ABUTMENT ;
    PORT
      LAYER M3 ;
      RECT 0 289.415 0.07 289.485 ;
    END
  END rw0_rd_out[113]
  PIN rw0_rd_out[114]
    DIRECTION OUTPUT ;
    USE SIGNAL ;
    SHAPE ABUTMENT ;
    PORT
      LAYER M3 ;
      RECT 0 289.835 0.07 289.905 ;
    END
  END rw0_rd_out[114]
  PIN rw0_rd_out[115]
    DIRECTION OUTPUT ;
    USE SIGNAL ;
    SHAPE ABUTMENT ;
    PORT
      LAYER M3 ;
      RECT 0 290.255 0.07 290.325 ;
    END
  END rw0_rd_out[115]
  PIN rw0_rd_out[116]
    DIRECTION OUTPUT ;
    USE SIGNAL ;
    SHAPE ABUTMENT ;
    PORT
      LAYER M3 ;
      RECT 0 290.675 0.07 290.745 ;
    END
  END rw0_rd_out[116]
  PIN rw0_rd_out[117]
    DIRECTION OUTPUT ;
    USE SIGNAL ;
    SHAPE ABUTMENT ;
    PORT
      LAYER M3 ;
      RECT 0 291.095 0.07 291.165 ;
    END
  END rw0_rd_out[117]
  PIN rw0_rd_out[118]
    DIRECTION OUTPUT ;
    USE SIGNAL ;
    SHAPE ABUTMENT ;
    PORT
      LAYER M3 ;
      RECT 0 291.515 0.07 291.585 ;
    END
  END rw0_rd_out[118]
  PIN rw0_rd_out[119]
    DIRECTION OUTPUT ;
    USE SIGNAL ;
    SHAPE ABUTMENT ;
    PORT
      LAYER M3 ;
      RECT 0 291.935 0.07 292.005 ;
    END
  END rw0_rd_out[119]
  PIN rw0_rd_out[120]
    DIRECTION OUTPUT ;
    USE SIGNAL ;
    SHAPE ABUTMENT ;
    PORT
      LAYER M3 ;
      RECT 0 292.355 0.07 292.425 ;
    END
  END rw0_rd_out[120]
  PIN rw0_rd_out[121]
    DIRECTION OUTPUT ;
    USE SIGNAL ;
    SHAPE ABUTMENT ;
    PORT
      LAYER M3 ;
      RECT 0 292.775 0.07 292.845 ;
    END
  END rw0_rd_out[121]
  PIN rw0_rd_out[122]
    DIRECTION OUTPUT ;
    USE SIGNAL ;
    SHAPE ABUTMENT ;
    PORT
      LAYER M3 ;
      RECT 0 293.195 0.07 293.265 ;
    END
  END rw0_rd_out[122]
  PIN rw0_rd_out[123]
    DIRECTION OUTPUT ;
    USE SIGNAL ;
    SHAPE ABUTMENT ;
    PORT
      LAYER M3 ;
      RECT 0 293.615 0.07 293.685 ;
    END
  END rw0_rd_out[123]
  PIN rw0_rd_out[124]
    DIRECTION OUTPUT ;
    USE SIGNAL ;
    SHAPE ABUTMENT ;
    PORT
      LAYER M3 ;
      RECT 0 294.035 0.07 294.105 ;
    END
  END rw0_rd_out[124]
  PIN rw0_rd_out[125]
    DIRECTION OUTPUT ;
    USE SIGNAL ;
    SHAPE ABUTMENT ;
    PORT
      LAYER M3 ;
      RECT 0 294.455 0.07 294.525 ;
    END
  END rw0_rd_out[125]
  PIN rw0_rd_out[126]
    DIRECTION OUTPUT ;
    USE SIGNAL ;
    SHAPE ABUTMENT ;
    PORT
      LAYER M3 ;
      RECT 0 294.875 0.07 294.945 ;
    END
  END rw0_rd_out[126]
  PIN rw0_rd_out[127]
    DIRECTION OUTPUT ;
    USE SIGNAL ;
    SHAPE ABUTMENT ;
    PORT
      LAYER M3 ;
      RECT 0 295.295 0.07 295.365 ;
    END
  END rw0_rd_out[127]
  PIN rw0_rd_out[128]
    DIRECTION OUTPUT ;
    USE SIGNAL ;
    SHAPE ABUTMENT ;
    PORT
      LAYER M3 ;
      RECT 0 295.715 0.07 295.785 ;
    END
  END rw0_rd_out[128]
  PIN rw0_rd_out[129]
    DIRECTION OUTPUT ;
    USE SIGNAL ;
    SHAPE ABUTMENT ;
    PORT
      LAYER M3 ;
      RECT 0 296.135 0.07 296.205 ;
    END
  END rw0_rd_out[129]
  PIN rw0_rd_out[130]
    DIRECTION OUTPUT ;
    USE SIGNAL ;
    SHAPE ABUTMENT ;
    PORT
      LAYER M3 ;
      RECT 0 296.555 0.07 296.625 ;
    END
  END rw0_rd_out[130]
  PIN rw0_rd_out[131]
    DIRECTION OUTPUT ;
    USE SIGNAL ;
    SHAPE ABUTMENT ;
    PORT
      LAYER M3 ;
      RECT 0 296.975 0.07 297.045 ;
    END
  END rw0_rd_out[131]
  PIN rw0_rd_out[132]
    DIRECTION OUTPUT ;
    USE SIGNAL ;
    SHAPE ABUTMENT ;
    PORT
      LAYER M3 ;
      RECT 0 297.395 0.07 297.465 ;
    END
  END rw0_rd_out[132]
  PIN rw0_rd_out[133]
    DIRECTION OUTPUT ;
    USE SIGNAL ;
    SHAPE ABUTMENT ;
    PORT
      LAYER M3 ;
      RECT 0 297.815 0.07 297.885 ;
    END
  END rw0_rd_out[133]
  PIN rw0_rd_out[134]
    DIRECTION OUTPUT ;
    USE SIGNAL ;
    SHAPE ABUTMENT ;
    PORT
      LAYER M3 ;
      RECT 0 298.235 0.07 298.305 ;
    END
  END rw0_rd_out[134]
  PIN rw0_rd_out[135]
    DIRECTION OUTPUT ;
    USE SIGNAL ;
    SHAPE ABUTMENT ;
    PORT
      LAYER M3 ;
      RECT 0 298.655 0.07 298.725 ;
    END
  END rw0_rd_out[135]
  PIN rw0_rd_out[136]
    DIRECTION OUTPUT ;
    USE SIGNAL ;
    SHAPE ABUTMENT ;
    PORT
      LAYER M3 ;
      RECT 0 299.075 0.07 299.145 ;
    END
  END rw0_rd_out[136]
  PIN rw0_rd_out[137]
    DIRECTION OUTPUT ;
    USE SIGNAL ;
    SHAPE ABUTMENT ;
    PORT
      LAYER M3 ;
      RECT 0 299.495 0.07 299.565 ;
    END
  END rw0_rd_out[137]
  PIN rw0_rd_out[138]
    DIRECTION OUTPUT ;
    USE SIGNAL ;
    SHAPE ABUTMENT ;
    PORT
      LAYER M3 ;
      RECT 0 299.915 0.07 299.985 ;
    END
  END rw0_rd_out[138]
  PIN rw0_rd_out[139]
    DIRECTION OUTPUT ;
    USE SIGNAL ;
    SHAPE ABUTMENT ;
    PORT
      LAYER M3 ;
      RECT 0 300.335 0.07 300.405 ;
    END
  END rw0_rd_out[139]
  PIN rw0_rd_out[140]
    DIRECTION OUTPUT ;
    USE SIGNAL ;
    SHAPE ABUTMENT ;
    PORT
      LAYER M3 ;
      RECT 0 300.755 0.07 300.825 ;
    END
  END rw0_rd_out[140]
  PIN rw0_rd_out[141]
    DIRECTION OUTPUT ;
    USE SIGNAL ;
    SHAPE ABUTMENT ;
    PORT
      LAYER M3 ;
      RECT 0 301.175 0.07 301.245 ;
    END
  END rw0_rd_out[141]
  PIN rw0_rd_out[142]
    DIRECTION OUTPUT ;
    USE SIGNAL ;
    SHAPE ABUTMENT ;
    PORT
      LAYER M3 ;
      RECT 0 301.595 0.07 301.665 ;
    END
  END rw0_rd_out[142]
  PIN rw0_rd_out[143]
    DIRECTION OUTPUT ;
    USE SIGNAL ;
    SHAPE ABUTMENT ;
    PORT
      LAYER M3 ;
      RECT 0 302.015 0.07 302.085 ;
    END
  END rw0_rd_out[143]
  PIN rw0_rd_out[144]
    DIRECTION OUTPUT ;
    USE SIGNAL ;
    SHAPE ABUTMENT ;
    PORT
      LAYER M3 ;
      RECT 0 302.435 0.07 302.505 ;
    END
  END rw0_rd_out[144]
  PIN rw0_rd_out[145]
    DIRECTION OUTPUT ;
    USE SIGNAL ;
    SHAPE ABUTMENT ;
    PORT
      LAYER M3 ;
      RECT 0 302.855 0.07 302.925 ;
    END
  END rw0_rd_out[145]
  PIN rw0_rd_out[146]
    DIRECTION OUTPUT ;
    USE SIGNAL ;
    SHAPE ABUTMENT ;
    PORT
      LAYER M3 ;
      RECT 0 303.275 0.07 303.345 ;
    END
  END rw0_rd_out[146]
  PIN rw0_rd_out[147]
    DIRECTION OUTPUT ;
    USE SIGNAL ;
    SHAPE ABUTMENT ;
    PORT
      LAYER M3 ;
      RECT 0 303.695 0.07 303.765 ;
    END
  END rw0_rd_out[147]
  PIN rw0_rd_out[148]
    DIRECTION OUTPUT ;
    USE SIGNAL ;
    SHAPE ABUTMENT ;
    PORT
      LAYER M3 ;
      RECT 0 304.115 0.07 304.185 ;
    END
  END rw0_rd_out[148]
  PIN rw0_rd_out[149]
    DIRECTION OUTPUT ;
    USE SIGNAL ;
    SHAPE ABUTMENT ;
    PORT
      LAYER M3 ;
      RECT 0 304.535 0.07 304.605 ;
    END
  END rw0_rd_out[149]
  PIN rw0_rd_out[150]
    DIRECTION OUTPUT ;
    USE SIGNAL ;
    SHAPE ABUTMENT ;
    PORT
      LAYER M3 ;
      RECT 0 304.955 0.07 305.025 ;
    END
  END rw0_rd_out[150]
  PIN rw0_rd_out[151]
    DIRECTION OUTPUT ;
    USE SIGNAL ;
    SHAPE ABUTMENT ;
    PORT
      LAYER M3 ;
      RECT 0 305.375 0.07 305.445 ;
    END
  END rw0_rd_out[151]
  PIN rw0_rd_out[152]
    DIRECTION OUTPUT ;
    USE SIGNAL ;
    SHAPE ABUTMENT ;
    PORT
      LAYER M3 ;
      RECT 0 305.795 0.07 305.865 ;
    END
  END rw0_rd_out[152]
  PIN rw0_rd_out[153]
    DIRECTION OUTPUT ;
    USE SIGNAL ;
    SHAPE ABUTMENT ;
    PORT
      LAYER M3 ;
      RECT 0 306.215 0.07 306.285 ;
    END
  END rw0_rd_out[153]
  PIN rw0_rd_out[154]
    DIRECTION OUTPUT ;
    USE SIGNAL ;
    SHAPE ABUTMENT ;
    PORT
      LAYER M3 ;
      RECT 0 306.635 0.07 306.705 ;
    END
  END rw0_rd_out[154]
  PIN rw0_rd_out[155]
    DIRECTION OUTPUT ;
    USE SIGNAL ;
    SHAPE ABUTMENT ;
    PORT
      LAYER M3 ;
      RECT 0 307.055 0.07 307.125 ;
    END
  END rw0_rd_out[155]
  PIN rw0_rd_out[156]
    DIRECTION OUTPUT ;
    USE SIGNAL ;
    SHAPE ABUTMENT ;
    PORT
      LAYER M3 ;
      RECT 0 307.475 0.07 307.545 ;
    END
  END rw0_rd_out[156]
  PIN rw0_rd_out[157]
    DIRECTION OUTPUT ;
    USE SIGNAL ;
    SHAPE ABUTMENT ;
    PORT
      LAYER M3 ;
      RECT 0 307.895 0.07 307.965 ;
    END
  END rw0_rd_out[157]
  PIN rw0_rd_out[158]
    DIRECTION OUTPUT ;
    USE SIGNAL ;
    SHAPE ABUTMENT ;
    PORT
      LAYER M3 ;
      RECT 0 308.315 0.07 308.385 ;
    END
  END rw0_rd_out[158]
  PIN rw0_rd_out[159]
    DIRECTION OUTPUT ;
    USE SIGNAL ;
    SHAPE ABUTMENT ;
    PORT
      LAYER M3 ;
      RECT 0 308.735 0.07 308.805 ;
    END
  END rw0_rd_out[159]
  PIN rw0_rd_out[160]
    DIRECTION OUTPUT ;
    USE SIGNAL ;
    SHAPE ABUTMENT ;
    PORT
      LAYER M3 ;
      RECT 0 309.155 0.07 309.225 ;
    END
  END rw0_rd_out[160]
  PIN rw0_rd_out[161]
    DIRECTION OUTPUT ;
    USE SIGNAL ;
    SHAPE ABUTMENT ;
    PORT
      LAYER M3 ;
      RECT 0 309.575 0.07 309.645 ;
    END
  END rw0_rd_out[161]
  PIN rw0_rd_out[162]
    DIRECTION OUTPUT ;
    USE SIGNAL ;
    SHAPE ABUTMENT ;
    PORT
      LAYER M3 ;
      RECT 0 309.995 0.07 310.065 ;
    END
  END rw0_rd_out[162]
  PIN rw0_rd_out[163]
    DIRECTION OUTPUT ;
    USE SIGNAL ;
    SHAPE ABUTMENT ;
    PORT
      LAYER M3 ;
      RECT 0 310.415 0.07 310.485 ;
    END
  END rw0_rd_out[163]
  PIN rw0_rd_out[164]
    DIRECTION OUTPUT ;
    USE SIGNAL ;
    SHAPE ABUTMENT ;
    PORT
      LAYER M3 ;
      RECT 0 310.835 0.07 310.905 ;
    END
  END rw0_rd_out[164]
  PIN rw0_rd_out[165]
    DIRECTION OUTPUT ;
    USE SIGNAL ;
    SHAPE ABUTMENT ;
    PORT
      LAYER M3 ;
      RECT 0 311.255 0.07 311.325 ;
    END
  END rw0_rd_out[165]
  PIN rw0_rd_out[166]
    DIRECTION OUTPUT ;
    USE SIGNAL ;
    SHAPE ABUTMENT ;
    PORT
      LAYER M3 ;
      RECT 0 311.675 0.07 311.745 ;
    END
  END rw0_rd_out[166]
  PIN rw0_rd_out[167]
    DIRECTION OUTPUT ;
    USE SIGNAL ;
    SHAPE ABUTMENT ;
    PORT
      LAYER M3 ;
      RECT 0 312.095 0.07 312.165 ;
    END
  END rw0_rd_out[167]
  PIN rw0_rd_out[168]
    DIRECTION OUTPUT ;
    USE SIGNAL ;
    SHAPE ABUTMENT ;
    PORT
      LAYER M3 ;
      RECT 0 312.515 0.07 312.585 ;
    END
  END rw0_rd_out[168]
  PIN rw0_rd_out[169]
    DIRECTION OUTPUT ;
    USE SIGNAL ;
    SHAPE ABUTMENT ;
    PORT
      LAYER M3 ;
      RECT 0 312.935 0.07 313.005 ;
    END
  END rw0_rd_out[169]
  PIN rw0_rd_out[170]
    DIRECTION OUTPUT ;
    USE SIGNAL ;
    SHAPE ABUTMENT ;
    PORT
      LAYER M3 ;
      RECT 0 313.355 0.07 313.425 ;
    END
  END rw0_rd_out[170]
  PIN rw0_rd_out[171]
    DIRECTION OUTPUT ;
    USE SIGNAL ;
    SHAPE ABUTMENT ;
    PORT
      LAYER M3 ;
      RECT 0 313.775 0.07 313.845 ;
    END
  END rw0_rd_out[171]
  PIN rw0_rd_out[172]
    DIRECTION OUTPUT ;
    USE SIGNAL ;
    SHAPE ABUTMENT ;
    PORT
      LAYER M3 ;
      RECT 0 314.195 0.07 314.265 ;
    END
  END rw0_rd_out[172]
  PIN rw0_rd_out[173]
    DIRECTION OUTPUT ;
    USE SIGNAL ;
    SHAPE ABUTMENT ;
    PORT
      LAYER M3 ;
      RECT 0 314.615 0.07 314.685 ;
    END
  END rw0_rd_out[173]
  PIN rw0_rd_out[174]
    DIRECTION OUTPUT ;
    USE SIGNAL ;
    SHAPE ABUTMENT ;
    PORT
      LAYER M3 ;
      RECT 0 315.035 0.07 315.105 ;
    END
  END rw0_rd_out[174]
  PIN rw0_rd_out[175]
    DIRECTION OUTPUT ;
    USE SIGNAL ;
    SHAPE ABUTMENT ;
    PORT
      LAYER M3 ;
      RECT 0 315.455 0.07 315.525 ;
    END
  END rw0_rd_out[175]
  PIN rw0_rd_out[176]
    DIRECTION OUTPUT ;
    USE SIGNAL ;
    SHAPE ABUTMENT ;
    PORT
      LAYER M3 ;
      RECT 0 315.875 0.07 315.945 ;
    END
  END rw0_rd_out[176]
  PIN rw0_rd_out[177]
    DIRECTION OUTPUT ;
    USE SIGNAL ;
    SHAPE ABUTMENT ;
    PORT
      LAYER M3 ;
      RECT 0 316.295 0.07 316.365 ;
    END
  END rw0_rd_out[177]
  PIN rw0_rd_out[178]
    DIRECTION OUTPUT ;
    USE SIGNAL ;
    SHAPE ABUTMENT ;
    PORT
      LAYER M3 ;
      RECT 0 316.715 0.07 316.785 ;
    END
  END rw0_rd_out[178]
  PIN rw0_rd_out[179]
    DIRECTION OUTPUT ;
    USE SIGNAL ;
    SHAPE ABUTMENT ;
    PORT
      LAYER M3 ;
      RECT 0 317.135 0.07 317.205 ;
    END
  END rw0_rd_out[179]
  PIN rw0_rd_out[180]
    DIRECTION OUTPUT ;
    USE SIGNAL ;
    SHAPE ABUTMENT ;
    PORT
      LAYER M3 ;
      RECT 0 317.555 0.07 317.625 ;
    END
  END rw0_rd_out[180]
  PIN rw0_rd_out[181]
    DIRECTION OUTPUT ;
    USE SIGNAL ;
    SHAPE ABUTMENT ;
    PORT
      LAYER M3 ;
      RECT 0 317.975 0.07 318.045 ;
    END
  END rw0_rd_out[181]
  PIN rw0_rd_out[182]
    DIRECTION OUTPUT ;
    USE SIGNAL ;
    SHAPE ABUTMENT ;
    PORT
      LAYER M3 ;
      RECT 0 318.395 0.07 318.465 ;
    END
  END rw0_rd_out[182]
  PIN rw0_rd_out[183]
    DIRECTION OUTPUT ;
    USE SIGNAL ;
    SHAPE ABUTMENT ;
    PORT
      LAYER M3 ;
      RECT 0 318.815 0.07 318.885 ;
    END
  END rw0_rd_out[183]
  PIN rw0_rd_out[184]
    DIRECTION OUTPUT ;
    USE SIGNAL ;
    SHAPE ABUTMENT ;
    PORT
      LAYER M3 ;
      RECT 0 319.235 0.07 319.305 ;
    END
  END rw0_rd_out[184]
  PIN rw0_rd_out[185]
    DIRECTION OUTPUT ;
    USE SIGNAL ;
    SHAPE ABUTMENT ;
    PORT
      LAYER M3 ;
      RECT 0 319.655 0.07 319.725 ;
    END
  END rw0_rd_out[185]
  PIN rw0_rd_out[186]
    DIRECTION OUTPUT ;
    USE SIGNAL ;
    SHAPE ABUTMENT ;
    PORT
      LAYER M3 ;
      RECT 0 320.075 0.07 320.145 ;
    END
  END rw0_rd_out[186]
  PIN rw0_rd_out[187]
    DIRECTION OUTPUT ;
    USE SIGNAL ;
    SHAPE ABUTMENT ;
    PORT
      LAYER M3 ;
      RECT 0 320.495 0.07 320.565 ;
    END
  END rw0_rd_out[187]
  PIN rw0_rd_out[188]
    DIRECTION OUTPUT ;
    USE SIGNAL ;
    SHAPE ABUTMENT ;
    PORT
      LAYER M3 ;
      RECT 0 320.915 0.07 320.985 ;
    END
  END rw0_rd_out[188]
  PIN rw0_rd_out[189]
    DIRECTION OUTPUT ;
    USE SIGNAL ;
    SHAPE ABUTMENT ;
    PORT
      LAYER M3 ;
      RECT 0 321.335 0.07 321.405 ;
    END
  END rw0_rd_out[189]
  PIN rw0_rd_out[190]
    DIRECTION OUTPUT ;
    USE SIGNAL ;
    SHAPE ABUTMENT ;
    PORT
      LAYER M3 ;
      RECT 0 321.755 0.07 321.825 ;
    END
  END rw0_rd_out[190]
  PIN rw0_rd_out[191]
    DIRECTION OUTPUT ;
    USE SIGNAL ;
    SHAPE ABUTMENT ;
    PORT
      LAYER M3 ;
      RECT 0 322.175 0.07 322.245 ;
    END
  END rw0_rd_out[191]
  PIN rw0_rd_out[192]
    DIRECTION OUTPUT ;
    USE SIGNAL ;
    SHAPE ABUTMENT ;
    PORT
      LAYER M3 ;
      RECT 0 322.595 0.07 322.665 ;
    END
  END rw0_rd_out[192]
  PIN rw0_rd_out[193]
    DIRECTION OUTPUT ;
    USE SIGNAL ;
    SHAPE ABUTMENT ;
    PORT
      LAYER M3 ;
      RECT 0 323.015 0.07 323.085 ;
    END
  END rw0_rd_out[193]
  PIN rw0_rd_out[194]
    DIRECTION OUTPUT ;
    USE SIGNAL ;
    SHAPE ABUTMENT ;
    PORT
      LAYER M3 ;
      RECT 0 323.435 0.07 323.505 ;
    END
  END rw0_rd_out[194]
  PIN rw0_rd_out[195]
    DIRECTION OUTPUT ;
    USE SIGNAL ;
    SHAPE ABUTMENT ;
    PORT
      LAYER M3 ;
      RECT 0 323.855 0.07 323.925 ;
    END
  END rw0_rd_out[195]
  PIN rw0_rd_out[196]
    DIRECTION OUTPUT ;
    USE SIGNAL ;
    SHAPE ABUTMENT ;
    PORT
      LAYER M3 ;
      RECT 0 324.275 0.07 324.345 ;
    END
  END rw0_rd_out[196]
  PIN rw0_rd_out[197]
    DIRECTION OUTPUT ;
    USE SIGNAL ;
    SHAPE ABUTMENT ;
    PORT
      LAYER M3 ;
      RECT 0 324.695 0.07 324.765 ;
    END
  END rw0_rd_out[197]
  PIN rw0_rd_out[198]
    DIRECTION OUTPUT ;
    USE SIGNAL ;
    SHAPE ABUTMENT ;
    PORT
      LAYER M3 ;
      RECT 0 325.115 0.07 325.185 ;
    END
  END rw0_rd_out[198]
  PIN rw0_rd_out[199]
    DIRECTION OUTPUT ;
    USE SIGNAL ;
    SHAPE ABUTMENT ;
    PORT
      LAYER M3 ;
      RECT 0 325.535 0.07 325.605 ;
    END
  END rw0_rd_out[199]
  PIN rw0_rd_out[200]
    DIRECTION OUTPUT ;
    USE SIGNAL ;
    SHAPE ABUTMENT ;
    PORT
      LAYER M3 ;
      RECT 0 325.955 0.07 326.025 ;
    END
  END rw0_rd_out[200]
  PIN rw0_rd_out[201]
    DIRECTION OUTPUT ;
    USE SIGNAL ;
    SHAPE ABUTMENT ;
    PORT
      LAYER M3 ;
      RECT 0 326.375 0.07 326.445 ;
    END
  END rw0_rd_out[201]
  PIN rw0_rd_out[202]
    DIRECTION OUTPUT ;
    USE SIGNAL ;
    SHAPE ABUTMENT ;
    PORT
      LAYER M3 ;
      RECT 0 326.795 0.07 326.865 ;
    END
  END rw0_rd_out[202]
  PIN rw0_rd_out[203]
    DIRECTION OUTPUT ;
    USE SIGNAL ;
    SHAPE ABUTMENT ;
    PORT
      LAYER M3 ;
      RECT 0 327.215 0.07 327.285 ;
    END
  END rw0_rd_out[203]
  PIN rw0_rd_out[204]
    DIRECTION OUTPUT ;
    USE SIGNAL ;
    SHAPE ABUTMENT ;
    PORT
      LAYER M3 ;
      RECT 0 327.635 0.07 327.705 ;
    END
  END rw0_rd_out[204]
  PIN rw0_rd_out[205]
    DIRECTION OUTPUT ;
    USE SIGNAL ;
    SHAPE ABUTMENT ;
    PORT
      LAYER M3 ;
      RECT 0 328.055 0.07 328.125 ;
    END
  END rw0_rd_out[205]
  PIN rw0_rd_out[206]
    DIRECTION OUTPUT ;
    USE SIGNAL ;
    SHAPE ABUTMENT ;
    PORT
      LAYER M3 ;
      RECT 0 328.475 0.07 328.545 ;
    END
  END rw0_rd_out[206]
  PIN rw0_rd_out[207]
    DIRECTION OUTPUT ;
    USE SIGNAL ;
    SHAPE ABUTMENT ;
    PORT
      LAYER M3 ;
      RECT 0 328.895 0.07 328.965 ;
    END
  END rw0_rd_out[207]
  PIN rw0_rd_out[208]
    DIRECTION OUTPUT ;
    USE SIGNAL ;
    SHAPE ABUTMENT ;
    PORT
      LAYER M3 ;
      RECT 0 329.315 0.07 329.385 ;
    END
  END rw0_rd_out[208]
  PIN rw0_rd_out[209]
    DIRECTION OUTPUT ;
    USE SIGNAL ;
    SHAPE ABUTMENT ;
    PORT
      LAYER M3 ;
      RECT 0 329.735 0.07 329.805 ;
    END
  END rw0_rd_out[209]
  PIN rw0_rd_out[210]
    DIRECTION OUTPUT ;
    USE SIGNAL ;
    SHAPE ABUTMENT ;
    PORT
      LAYER M3 ;
      RECT 0 330.155 0.07 330.225 ;
    END
  END rw0_rd_out[210]
  PIN rw0_rd_out[211]
    DIRECTION OUTPUT ;
    USE SIGNAL ;
    SHAPE ABUTMENT ;
    PORT
      LAYER M3 ;
      RECT 0 330.575 0.07 330.645 ;
    END
  END rw0_rd_out[211]
  PIN rw0_rd_out[212]
    DIRECTION OUTPUT ;
    USE SIGNAL ;
    SHAPE ABUTMENT ;
    PORT
      LAYER M3 ;
      RECT 0 330.995 0.07 331.065 ;
    END
  END rw0_rd_out[212]
  PIN rw0_rd_out[213]
    DIRECTION OUTPUT ;
    USE SIGNAL ;
    SHAPE ABUTMENT ;
    PORT
      LAYER M3 ;
      RECT 0 331.415 0.07 331.485 ;
    END
  END rw0_rd_out[213]
  PIN rw0_rd_out[214]
    DIRECTION OUTPUT ;
    USE SIGNAL ;
    SHAPE ABUTMENT ;
    PORT
      LAYER M3 ;
      RECT 0 331.835 0.07 331.905 ;
    END
  END rw0_rd_out[214]
  PIN rw0_rd_out[215]
    DIRECTION OUTPUT ;
    USE SIGNAL ;
    SHAPE ABUTMENT ;
    PORT
      LAYER M3 ;
      RECT 0 332.255 0.07 332.325 ;
    END
  END rw0_rd_out[215]
  PIN rw0_rd_out[216]
    DIRECTION OUTPUT ;
    USE SIGNAL ;
    SHAPE ABUTMENT ;
    PORT
      LAYER M3 ;
      RECT 0 332.675 0.07 332.745 ;
    END
  END rw0_rd_out[216]
  PIN rw0_rd_out[217]
    DIRECTION OUTPUT ;
    USE SIGNAL ;
    SHAPE ABUTMENT ;
    PORT
      LAYER M3 ;
      RECT 0 333.095 0.07 333.165 ;
    END
  END rw0_rd_out[217]
  PIN rw0_rd_out[218]
    DIRECTION OUTPUT ;
    USE SIGNAL ;
    SHAPE ABUTMENT ;
    PORT
      LAYER M3 ;
      RECT 0 333.515 0.07 333.585 ;
    END
  END rw0_rd_out[218]
  PIN rw0_rd_out[219]
    DIRECTION OUTPUT ;
    USE SIGNAL ;
    SHAPE ABUTMENT ;
    PORT
      LAYER M3 ;
      RECT 0 333.935 0.07 334.005 ;
    END
  END rw0_rd_out[219]
  PIN rw0_rd_out[220]
    DIRECTION OUTPUT ;
    USE SIGNAL ;
    SHAPE ABUTMENT ;
    PORT
      LAYER M3 ;
      RECT 0 334.355 0.07 334.425 ;
    END
  END rw0_rd_out[220]
  PIN rw0_rd_out[221]
    DIRECTION OUTPUT ;
    USE SIGNAL ;
    SHAPE ABUTMENT ;
    PORT
      LAYER M3 ;
      RECT 0 334.775 0.07 334.845 ;
    END
  END rw0_rd_out[221]
  PIN rw0_rd_out[222]
    DIRECTION OUTPUT ;
    USE SIGNAL ;
    SHAPE ABUTMENT ;
    PORT
      LAYER M3 ;
      RECT 0 335.195 0.07 335.265 ;
    END
  END rw0_rd_out[222]
  PIN rw0_rd_out[223]
    DIRECTION OUTPUT ;
    USE SIGNAL ;
    SHAPE ABUTMENT ;
    PORT
      LAYER M3 ;
      RECT 0 335.615 0.07 335.685 ;
    END
  END rw0_rd_out[223]
  PIN rw0_rd_out[224]
    DIRECTION OUTPUT ;
    USE SIGNAL ;
    SHAPE ABUTMENT ;
    PORT
      LAYER M3 ;
      RECT 0 336.035 0.07 336.105 ;
    END
  END rw0_rd_out[224]
  PIN rw0_rd_out[225]
    DIRECTION OUTPUT ;
    USE SIGNAL ;
    SHAPE ABUTMENT ;
    PORT
      LAYER M3 ;
      RECT 0 336.455 0.07 336.525 ;
    END
  END rw0_rd_out[225]
  PIN rw0_rd_out[226]
    DIRECTION OUTPUT ;
    USE SIGNAL ;
    SHAPE ABUTMENT ;
    PORT
      LAYER M3 ;
      RECT 0 336.875 0.07 336.945 ;
    END
  END rw0_rd_out[226]
  PIN rw0_rd_out[227]
    DIRECTION OUTPUT ;
    USE SIGNAL ;
    SHAPE ABUTMENT ;
    PORT
      LAYER M3 ;
      RECT 0 337.295 0.07 337.365 ;
    END
  END rw0_rd_out[227]
  PIN rw0_rd_out[228]
    DIRECTION OUTPUT ;
    USE SIGNAL ;
    SHAPE ABUTMENT ;
    PORT
      LAYER M3 ;
      RECT 0 337.715 0.07 337.785 ;
    END
  END rw0_rd_out[228]
  PIN rw0_rd_out[229]
    DIRECTION OUTPUT ;
    USE SIGNAL ;
    SHAPE ABUTMENT ;
    PORT
      LAYER M3 ;
      RECT 0 338.135 0.07 338.205 ;
    END
  END rw0_rd_out[229]
  PIN rw0_rd_out[230]
    DIRECTION OUTPUT ;
    USE SIGNAL ;
    SHAPE ABUTMENT ;
    PORT
      LAYER M3 ;
      RECT 0 338.555 0.07 338.625 ;
    END
  END rw0_rd_out[230]
  PIN rw0_rd_out[231]
    DIRECTION OUTPUT ;
    USE SIGNAL ;
    SHAPE ABUTMENT ;
    PORT
      LAYER M3 ;
      RECT 0 338.975 0.07 339.045 ;
    END
  END rw0_rd_out[231]
  PIN rw0_rd_out[232]
    DIRECTION OUTPUT ;
    USE SIGNAL ;
    SHAPE ABUTMENT ;
    PORT
      LAYER M3 ;
      RECT 0 339.395 0.07 339.465 ;
    END
  END rw0_rd_out[232]
  PIN rw0_rd_out[233]
    DIRECTION OUTPUT ;
    USE SIGNAL ;
    SHAPE ABUTMENT ;
    PORT
      LAYER M3 ;
      RECT 0 339.815 0.07 339.885 ;
    END
  END rw0_rd_out[233]
  PIN rw0_rd_out[234]
    DIRECTION OUTPUT ;
    USE SIGNAL ;
    SHAPE ABUTMENT ;
    PORT
      LAYER M3 ;
      RECT 0 340.235 0.07 340.305 ;
    END
  END rw0_rd_out[234]
  PIN rw0_rd_out[235]
    DIRECTION OUTPUT ;
    USE SIGNAL ;
    SHAPE ABUTMENT ;
    PORT
      LAYER M3 ;
      RECT 0 340.655 0.07 340.725 ;
    END
  END rw0_rd_out[235]
  PIN rw0_rd_out[236]
    DIRECTION OUTPUT ;
    USE SIGNAL ;
    SHAPE ABUTMENT ;
    PORT
      LAYER M3 ;
      RECT 0 341.075 0.07 341.145 ;
    END
  END rw0_rd_out[236]
  PIN rw0_rd_out[237]
    DIRECTION OUTPUT ;
    USE SIGNAL ;
    SHAPE ABUTMENT ;
    PORT
      LAYER M3 ;
      RECT 0 341.495 0.07 341.565 ;
    END
  END rw0_rd_out[237]
  PIN rw0_rd_out[238]
    DIRECTION OUTPUT ;
    USE SIGNAL ;
    SHAPE ABUTMENT ;
    PORT
      LAYER M3 ;
      RECT 0 341.915 0.07 341.985 ;
    END
  END rw0_rd_out[238]
  PIN rw0_rd_out[239]
    DIRECTION OUTPUT ;
    USE SIGNAL ;
    SHAPE ABUTMENT ;
    PORT
      LAYER M3 ;
      RECT 0 342.335 0.07 342.405 ;
    END
  END rw0_rd_out[239]
  PIN rw0_rd_out[240]
    DIRECTION OUTPUT ;
    USE SIGNAL ;
    SHAPE ABUTMENT ;
    PORT
      LAYER M3 ;
      RECT 0 342.755 0.07 342.825 ;
    END
  END rw0_rd_out[240]
  PIN rw0_rd_out[241]
    DIRECTION OUTPUT ;
    USE SIGNAL ;
    SHAPE ABUTMENT ;
    PORT
      LAYER M3 ;
      RECT 0 343.175 0.07 343.245 ;
    END
  END rw0_rd_out[241]
  PIN rw0_rd_out[242]
    DIRECTION OUTPUT ;
    USE SIGNAL ;
    SHAPE ABUTMENT ;
    PORT
      LAYER M3 ;
      RECT 0 343.595 0.07 343.665 ;
    END
  END rw0_rd_out[242]
  PIN rw0_rd_out[243]
    DIRECTION OUTPUT ;
    USE SIGNAL ;
    SHAPE ABUTMENT ;
    PORT
      LAYER M3 ;
      RECT 0 344.015 0.07 344.085 ;
    END
  END rw0_rd_out[243]
  PIN rw0_rd_out[244]
    DIRECTION OUTPUT ;
    USE SIGNAL ;
    SHAPE ABUTMENT ;
    PORT
      LAYER M3 ;
      RECT 0 344.435 0.07 344.505 ;
    END
  END rw0_rd_out[244]
  PIN rw0_rd_out[245]
    DIRECTION OUTPUT ;
    USE SIGNAL ;
    SHAPE ABUTMENT ;
    PORT
      LAYER M3 ;
      RECT 0 344.855 0.07 344.925 ;
    END
  END rw0_rd_out[245]
  PIN rw0_rd_out[246]
    DIRECTION OUTPUT ;
    USE SIGNAL ;
    SHAPE ABUTMENT ;
    PORT
      LAYER M3 ;
      RECT 0 345.275 0.07 345.345 ;
    END
  END rw0_rd_out[246]
  PIN rw0_rd_out[247]
    DIRECTION OUTPUT ;
    USE SIGNAL ;
    SHAPE ABUTMENT ;
    PORT
      LAYER M3 ;
      RECT 0 345.695 0.07 345.765 ;
    END
  END rw0_rd_out[247]
  PIN rw0_rd_out[248]
    DIRECTION OUTPUT ;
    USE SIGNAL ;
    SHAPE ABUTMENT ;
    PORT
      LAYER M3 ;
      RECT 0 346.115 0.07 346.185 ;
    END
  END rw0_rd_out[248]
  PIN rw0_rd_out[249]
    DIRECTION OUTPUT ;
    USE SIGNAL ;
    SHAPE ABUTMENT ;
    PORT
      LAYER M3 ;
      RECT 0 346.535 0.07 346.605 ;
    END
  END rw0_rd_out[249]
  PIN rw0_rd_out[250]
    DIRECTION OUTPUT ;
    USE SIGNAL ;
    SHAPE ABUTMENT ;
    PORT
      LAYER M3 ;
      RECT 0 346.955 0.07 347.025 ;
    END
  END rw0_rd_out[250]
  PIN rw0_rd_out[251]
    DIRECTION OUTPUT ;
    USE SIGNAL ;
    SHAPE ABUTMENT ;
    PORT
      LAYER M3 ;
      RECT 0 347.375 0.07 347.445 ;
    END
  END rw0_rd_out[251]
  PIN rw0_rd_out[252]
    DIRECTION OUTPUT ;
    USE SIGNAL ;
    SHAPE ABUTMENT ;
    PORT
      LAYER M3 ;
      RECT 0 347.795 0.07 347.865 ;
    END
  END rw0_rd_out[252]
  PIN rw0_rd_out[253]
    DIRECTION OUTPUT ;
    USE SIGNAL ;
    SHAPE ABUTMENT ;
    PORT
      LAYER M3 ;
      RECT 0 348.215 0.07 348.285 ;
    END
  END rw0_rd_out[253]
  PIN rw0_rd_out[254]
    DIRECTION OUTPUT ;
    USE SIGNAL ;
    SHAPE ABUTMENT ;
    PORT
      LAYER M3 ;
      RECT 0 348.635 0.07 348.705 ;
    END
  END rw0_rd_out[254]
  PIN rw0_rd_out[255]
    DIRECTION OUTPUT ;
    USE SIGNAL ;
    SHAPE ABUTMENT ;
    PORT
      LAYER M3 ;
      RECT 0 349.055 0.07 349.125 ;
    END
  END rw0_rd_out[255]
  PIN rw0_rd_out[256]
    DIRECTION OUTPUT ;
    USE SIGNAL ;
    SHAPE ABUTMENT ;
    PORT
      LAYER M3 ;
      RECT 0 349.475 0.07 349.545 ;
    END
  END rw0_rd_out[256]
  PIN rw0_rd_out[257]
    DIRECTION OUTPUT ;
    USE SIGNAL ;
    SHAPE ABUTMENT ;
    PORT
      LAYER M3 ;
      RECT 0 349.895 0.07 349.965 ;
    END
  END rw0_rd_out[257]
  PIN rw0_rd_out[258]
    DIRECTION OUTPUT ;
    USE SIGNAL ;
    SHAPE ABUTMENT ;
    PORT
      LAYER M3 ;
      RECT 0 350.315 0.07 350.385 ;
    END
  END rw0_rd_out[258]
  PIN rw0_rd_out[259]
    DIRECTION OUTPUT ;
    USE SIGNAL ;
    SHAPE ABUTMENT ;
    PORT
      LAYER M3 ;
      RECT 0 350.735 0.07 350.805 ;
    END
  END rw0_rd_out[259]
  PIN rw0_rd_out[260]
    DIRECTION OUTPUT ;
    USE SIGNAL ;
    SHAPE ABUTMENT ;
    PORT
      LAYER M3 ;
      RECT 0 351.155 0.07 351.225 ;
    END
  END rw0_rd_out[260]
  PIN rw0_rd_out[261]
    DIRECTION OUTPUT ;
    USE SIGNAL ;
    SHAPE ABUTMENT ;
    PORT
      LAYER M3 ;
      RECT 0 351.575 0.07 351.645 ;
    END
  END rw0_rd_out[261]
  PIN rw0_rd_out[262]
    DIRECTION OUTPUT ;
    USE SIGNAL ;
    SHAPE ABUTMENT ;
    PORT
      LAYER M3 ;
      RECT 0 351.995 0.07 352.065 ;
    END
  END rw0_rd_out[262]
  PIN rw0_rd_out[263]
    DIRECTION OUTPUT ;
    USE SIGNAL ;
    SHAPE ABUTMENT ;
    PORT
      LAYER M3 ;
      RECT 0 352.415 0.07 352.485 ;
    END
  END rw0_rd_out[263]
  PIN rw0_rd_out[264]
    DIRECTION OUTPUT ;
    USE SIGNAL ;
    SHAPE ABUTMENT ;
    PORT
      LAYER M3 ;
      RECT 0 352.835 0.07 352.905 ;
    END
  END rw0_rd_out[264]
  PIN rw0_rd_out[265]
    DIRECTION OUTPUT ;
    USE SIGNAL ;
    SHAPE ABUTMENT ;
    PORT
      LAYER M3 ;
      RECT 0 353.255 0.07 353.325 ;
    END
  END rw0_rd_out[265]
  PIN rw0_rd_out[266]
    DIRECTION OUTPUT ;
    USE SIGNAL ;
    SHAPE ABUTMENT ;
    PORT
      LAYER M3 ;
      RECT 0 353.675 0.07 353.745 ;
    END
  END rw0_rd_out[266]
  PIN rw0_rd_out[267]
    DIRECTION OUTPUT ;
    USE SIGNAL ;
    SHAPE ABUTMENT ;
    PORT
      LAYER M3 ;
      RECT 0 354.095 0.07 354.165 ;
    END
  END rw0_rd_out[267]
  PIN rw0_rd_out[268]
    DIRECTION OUTPUT ;
    USE SIGNAL ;
    SHAPE ABUTMENT ;
    PORT
      LAYER M3 ;
      RECT 0 354.515 0.07 354.585 ;
    END
  END rw0_rd_out[268]
  PIN rw0_rd_out[269]
    DIRECTION OUTPUT ;
    USE SIGNAL ;
    SHAPE ABUTMENT ;
    PORT
      LAYER M3 ;
      RECT 0 354.935 0.07 355.005 ;
    END
  END rw0_rd_out[269]
  PIN rw0_rd_out[270]
    DIRECTION OUTPUT ;
    USE SIGNAL ;
    SHAPE ABUTMENT ;
    PORT
      LAYER M3 ;
      RECT 0 355.355 0.07 355.425 ;
    END
  END rw0_rd_out[270]
  PIN rw0_rd_out[271]
    DIRECTION OUTPUT ;
    USE SIGNAL ;
    SHAPE ABUTMENT ;
    PORT
      LAYER M3 ;
      RECT 0 355.775 0.07 355.845 ;
    END
  END rw0_rd_out[271]
  PIN rw0_rd_out[272]
    DIRECTION OUTPUT ;
    USE SIGNAL ;
    SHAPE ABUTMENT ;
    PORT
      LAYER M3 ;
      RECT 0 356.195 0.07 356.265 ;
    END
  END rw0_rd_out[272]
  PIN rw0_rd_out[273]
    DIRECTION OUTPUT ;
    USE SIGNAL ;
    SHAPE ABUTMENT ;
    PORT
      LAYER M3 ;
      RECT 0 356.615 0.07 356.685 ;
    END
  END rw0_rd_out[273]
  PIN rw0_rd_out[274]
    DIRECTION OUTPUT ;
    USE SIGNAL ;
    SHAPE ABUTMENT ;
    PORT
      LAYER M3 ;
      RECT 0 357.035 0.07 357.105 ;
    END
  END rw0_rd_out[274]
  PIN rw0_rd_out[275]
    DIRECTION OUTPUT ;
    USE SIGNAL ;
    SHAPE ABUTMENT ;
    PORT
      LAYER M3 ;
      RECT 0 357.455 0.07 357.525 ;
    END
  END rw0_rd_out[275]
  PIN rw0_rd_out[276]
    DIRECTION OUTPUT ;
    USE SIGNAL ;
    SHAPE ABUTMENT ;
    PORT
      LAYER M3 ;
      RECT 0 357.875 0.07 357.945 ;
    END
  END rw0_rd_out[276]
  PIN rw0_rd_out[277]
    DIRECTION OUTPUT ;
    USE SIGNAL ;
    SHAPE ABUTMENT ;
    PORT
      LAYER M3 ;
      RECT 0 358.295 0.07 358.365 ;
    END
  END rw0_rd_out[277]
  PIN rw0_rd_out[278]
    DIRECTION OUTPUT ;
    USE SIGNAL ;
    SHAPE ABUTMENT ;
    PORT
      LAYER M3 ;
      RECT 0 358.715 0.07 358.785 ;
    END
  END rw0_rd_out[278]
  PIN rw0_rd_out[279]
    DIRECTION OUTPUT ;
    USE SIGNAL ;
    SHAPE ABUTMENT ;
    PORT
      LAYER M3 ;
      RECT 0 359.135 0.07 359.205 ;
    END
  END rw0_rd_out[279]
  PIN rw0_rd_out[280]
    DIRECTION OUTPUT ;
    USE SIGNAL ;
    SHAPE ABUTMENT ;
    PORT
      LAYER M3 ;
      RECT 0 359.555 0.07 359.625 ;
    END
  END rw0_rd_out[280]
  PIN rw0_rd_out[281]
    DIRECTION OUTPUT ;
    USE SIGNAL ;
    SHAPE ABUTMENT ;
    PORT
      LAYER M3 ;
      RECT 0 359.975 0.07 360.045 ;
    END
  END rw0_rd_out[281]
  PIN rw0_rd_out[282]
    DIRECTION OUTPUT ;
    USE SIGNAL ;
    SHAPE ABUTMENT ;
    PORT
      LAYER M3 ;
      RECT 0 360.395 0.07 360.465 ;
    END
  END rw0_rd_out[282]
  PIN rw0_rd_out[283]
    DIRECTION OUTPUT ;
    USE SIGNAL ;
    SHAPE ABUTMENT ;
    PORT
      LAYER M3 ;
      RECT 0 360.815 0.07 360.885 ;
    END
  END rw0_rd_out[283]
  PIN rw0_rd_out[284]
    DIRECTION OUTPUT ;
    USE SIGNAL ;
    SHAPE ABUTMENT ;
    PORT
      LAYER M3 ;
      RECT 0 361.235 0.07 361.305 ;
    END
  END rw0_rd_out[284]
  PIN rw0_rd_out[285]
    DIRECTION OUTPUT ;
    USE SIGNAL ;
    SHAPE ABUTMENT ;
    PORT
      LAYER M3 ;
      RECT 0 361.655 0.07 361.725 ;
    END
  END rw0_rd_out[285]
  PIN rw0_rd_out[286]
    DIRECTION OUTPUT ;
    USE SIGNAL ;
    SHAPE ABUTMENT ;
    PORT
      LAYER M3 ;
      RECT 0 362.075 0.07 362.145 ;
    END
  END rw0_rd_out[286]
  PIN rw0_rd_out[287]
    DIRECTION OUTPUT ;
    USE SIGNAL ;
    SHAPE ABUTMENT ;
    PORT
      LAYER M3 ;
      RECT 0 362.495 0.07 362.565 ;
    END
  END rw0_rd_out[287]
  PIN rw0_rd_out[288]
    DIRECTION OUTPUT ;
    USE SIGNAL ;
    SHAPE ABUTMENT ;
    PORT
      LAYER M3 ;
      RECT 0 362.915 0.07 362.985 ;
    END
  END rw0_rd_out[288]
  PIN rw0_rd_out[289]
    DIRECTION OUTPUT ;
    USE SIGNAL ;
    SHAPE ABUTMENT ;
    PORT
      LAYER M3 ;
      RECT 0 363.335 0.07 363.405 ;
    END
  END rw0_rd_out[289]
  PIN rw0_rd_out[290]
    DIRECTION OUTPUT ;
    USE SIGNAL ;
    SHAPE ABUTMENT ;
    PORT
      LAYER M3 ;
      RECT 0 363.755 0.07 363.825 ;
    END
  END rw0_rd_out[290]
  PIN rw0_rd_out[291]
    DIRECTION OUTPUT ;
    USE SIGNAL ;
    SHAPE ABUTMENT ;
    PORT
      LAYER M3 ;
      RECT 0 364.175 0.07 364.245 ;
    END
  END rw0_rd_out[291]
  PIN rw0_rd_out[292]
    DIRECTION OUTPUT ;
    USE SIGNAL ;
    SHAPE ABUTMENT ;
    PORT
      LAYER M3 ;
      RECT 0 364.595 0.07 364.665 ;
    END
  END rw0_rd_out[292]
  PIN rw0_rd_out[293]
    DIRECTION OUTPUT ;
    USE SIGNAL ;
    SHAPE ABUTMENT ;
    PORT
      LAYER M3 ;
      RECT 0 365.015 0.07 365.085 ;
    END
  END rw0_rd_out[293]
  PIN rw0_rd_out[294]
    DIRECTION OUTPUT ;
    USE SIGNAL ;
    SHAPE ABUTMENT ;
    PORT
      LAYER M3 ;
      RECT 0 365.435 0.07 365.505 ;
    END
  END rw0_rd_out[294]
  PIN rw0_rd_out[295]
    DIRECTION OUTPUT ;
    USE SIGNAL ;
    SHAPE ABUTMENT ;
    PORT
      LAYER M3 ;
      RECT 0 365.855 0.07 365.925 ;
    END
  END rw0_rd_out[295]
  PIN rw0_rd_out[296]
    DIRECTION OUTPUT ;
    USE SIGNAL ;
    SHAPE ABUTMENT ;
    PORT
      LAYER M3 ;
      RECT 0 366.275 0.07 366.345 ;
    END
  END rw0_rd_out[296]
  PIN rw0_rd_out[297]
    DIRECTION OUTPUT ;
    USE SIGNAL ;
    SHAPE ABUTMENT ;
    PORT
      LAYER M3 ;
      RECT 0 366.695 0.07 366.765 ;
    END
  END rw0_rd_out[297]
  PIN rw0_rd_out[298]
    DIRECTION OUTPUT ;
    USE SIGNAL ;
    SHAPE ABUTMENT ;
    PORT
      LAYER M3 ;
      RECT 0 367.115 0.07 367.185 ;
    END
  END rw0_rd_out[298]
  PIN rw0_rd_out[299]
    DIRECTION OUTPUT ;
    USE SIGNAL ;
    SHAPE ABUTMENT ;
    PORT
      LAYER M3 ;
      RECT 0 367.535 0.07 367.605 ;
    END
  END rw0_rd_out[299]
  PIN rw0_rd_out[300]
    DIRECTION OUTPUT ;
    USE SIGNAL ;
    SHAPE ABUTMENT ;
    PORT
      LAYER M3 ;
      RECT 0 367.955 0.07 368.025 ;
    END
  END rw0_rd_out[300]
  PIN rw0_rd_out[301]
    DIRECTION OUTPUT ;
    USE SIGNAL ;
    SHAPE ABUTMENT ;
    PORT
      LAYER M3 ;
      RECT 0 368.375 0.07 368.445 ;
    END
  END rw0_rd_out[301]
  PIN rw0_rd_out[302]
    DIRECTION OUTPUT ;
    USE SIGNAL ;
    SHAPE ABUTMENT ;
    PORT
      LAYER M3 ;
      RECT 0 368.795 0.07 368.865 ;
    END
  END rw0_rd_out[302]
  PIN rw0_rd_out[303]
    DIRECTION OUTPUT ;
    USE SIGNAL ;
    SHAPE ABUTMENT ;
    PORT
      LAYER M3 ;
      RECT 0 369.215 0.07 369.285 ;
    END
  END rw0_rd_out[303]
  PIN rw0_rd_out[304]
    DIRECTION OUTPUT ;
    USE SIGNAL ;
    SHAPE ABUTMENT ;
    PORT
      LAYER M3 ;
      RECT 0 369.635 0.07 369.705 ;
    END
  END rw0_rd_out[304]
  PIN rw0_rd_out[305]
    DIRECTION OUTPUT ;
    USE SIGNAL ;
    SHAPE ABUTMENT ;
    PORT
      LAYER M3 ;
      RECT 0 370.055 0.07 370.125 ;
    END
  END rw0_rd_out[305]
  PIN rw0_rd_out[306]
    DIRECTION OUTPUT ;
    USE SIGNAL ;
    SHAPE ABUTMENT ;
    PORT
      LAYER M3 ;
      RECT 0 370.475 0.07 370.545 ;
    END
  END rw0_rd_out[306]
  PIN rw0_rd_out[307]
    DIRECTION OUTPUT ;
    USE SIGNAL ;
    SHAPE ABUTMENT ;
    PORT
      LAYER M3 ;
      RECT 0 370.895 0.07 370.965 ;
    END
  END rw0_rd_out[307]
  PIN rw0_rd_out[308]
    DIRECTION OUTPUT ;
    USE SIGNAL ;
    SHAPE ABUTMENT ;
    PORT
      LAYER M3 ;
      RECT 0 371.315 0.07 371.385 ;
    END
  END rw0_rd_out[308]
  PIN rw0_rd_out[309]
    DIRECTION OUTPUT ;
    USE SIGNAL ;
    SHAPE ABUTMENT ;
    PORT
      LAYER M3 ;
      RECT 0 371.735 0.07 371.805 ;
    END
  END rw0_rd_out[309]
  PIN rw0_rd_out[310]
    DIRECTION OUTPUT ;
    USE SIGNAL ;
    SHAPE ABUTMENT ;
    PORT
      LAYER M3 ;
      RECT 0 372.155 0.07 372.225 ;
    END
  END rw0_rd_out[310]
  PIN rw0_rd_out[311]
    DIRECTION OUTPUT ;
    USE SIGNAL ;
    SHAPE ABUTMENT ;
    PORT
      LAYER M3 ;
      RECT 0 372.575 0.07 372.645 ;
    END
  END rw0_rd_out[311]
  PIN rw0_rd_out[312]
    DIRECTION OUTPUT ;
    USE SIGNAL ;
    SHAPE ABUTMENT ;
    PORT
      LAYER M3 ;
      RECT 0 372.995 0.07 373.065 ;
    END
  END rw0_rd_out[312]
  PIN rw0_rd_out[313]
    DIRECTION OUTPUT ;
    USE SIGNAL ;
    SHAPE ABUTMENT ;
    PORT
      LAYER M3 ;
      RECT 0 373.415 0.07 373.485 ;
    END
  END rw0_rd_out[313]
  PIN rw0_rd_out[314]
    DIRECTION OUTPUT ;
    USE SIGNAL ;
    SHAPE ABUTMENT ;
    PORT
      LAYER M3 ;
      RECT 0 373.835 0.07 373.905 ;
    END
  END rw0_rd_out[314]
  PIN rw0_rd_out[315]
    DIRECTION OUTPUT ;
    USE SIGNAL ;
    SHAPE ABUTMENT ;
    PORT
      LAYER M3 ;
      RECT 0 374.255 0.07 374.325 ;
    END
  END rw0_rd_out[315]
  PIN rw0_rd_out[316]
    DIRECTION OUTPUT ;
    USE SIGNAL ;
    SHAPE ABUTMENT ;
    PORT
      LAYER M3 ;
      RECT 0 374.675 0.07 374.745 ;
    END
  END rw0_rd_out[316]
  PIN rw0_rd_out[317]
    DIRECTION OUTPUT ;
    USE SIGNAL ;
    SHAPE ABUTMENT ;
    PORT
      LAYER M3 ;
      RECT 0 375.095 0.07 375.165 ;
    END
  END rw0_rd_out[317]
  PIN rw0_rd_out[318]
    DIRECTION OUTPUT ;
    USE SIGNAL ;
    SHAPE ABUTMENT ;
    PORT
      LAYER M3 ;
      RECT 0 375.515 0.07 375.585 ;
    END
  END rw0_rd_out[318]
  PIN rw0_rd_out[319]
    DIRECTION OUTPUT ;
    USE SIGNAL ;
    SHAPE ABUTMENT ;
    PORT
      LAYER M3 ;
      RECT 0 375.935 0.07 376.005 ;
    END
  END rw0_rd_out[319]
  PIN rw0_rd_out[320]
    DIRECTION OUTPUT ;
    USE SIGNAL ;
    SHAPE ABUTMENT ;
    PORT
      LAYER M3 ;
      RECT 0 376.355 0.07 376.425 ;
    END
  END rw0_rd_out[320]
  PIN rw0_rd_out[321]
    DIRECTION OUTPUT ;
    USE SIGNAL ;
    SHAPE ABUTMENT ;
    PORT
      LAYER M3 ;
      RECT 0 376.775 0.07 376.845 ;
    END
  END rw0_rd_out[321]
  PIN rw0_rd_out[322]
    DIRECTION OUTPUT ;
    USE SIGNAL ;
    SHAPE ABUTMENT ;
    PORT
      LAYER M3 ;
      RECT 0 377.195 0.07 377.265 ;
    END
  END rw0_rd_out[322]
  PIN rw0_rd_out[323]
    DIRECTION OUTPUT ;
    USE SIGNAL ;
    SHAPE ABUTMENT ;
    PORT
      LAYER M3 ;
      RECT 0 377.615 0.07 377.685 ;
    END
  END rw0_rd_out[323]
  PIN rw0_rd_out[324]
    DIRECTION OUTPUT ;
    USE SIGNAL ;
    SHAPE ABUTMENT ;
    PORT
      LAYER M3 ;
      RECT 0 378.035 0.07 378.105 ;
    END
  END rw0_rd_out[324]
  PIN rw0_rd_out[325]
    DIRECTION OUTPUT ;
    USE SIGNAL ;
    SHAPE ABUTMENT ;
    PORT
      LAYER M3 ;
      RECT 0 378.455 0.07 378.525 ;
    END
  END rw0_rd_out[325]
  PIN rw0_rd_out[326]
    DIRECTION OUTPUT ;
    USE SIGNAL ;
    SHAPE ABUTMENT ;
    PORT
      LAYER M3 ;
      RECT 0 378.875 0.07 378.945 ;
    END
  END rw0_rd_out[326]
  PIN rw0_rd_out[327]
    DIRECTION OUTPUT ;
    USE SIGNAL ;
    SHAPE ABUTMENT ;
    PORT
      LAYER M3 ;
      RECT 0 379.295 0.07 379.365 ;
    END
  END rw0_rd_out[327]
  PIN rw0_rd_out[328]
    DIRECTION OUTPUT ;
    USE SIGNAL ;
    SHAPE ABUTMENT ;
    PORT
      LAYER M3 ;
      RECT 0 379.715 0.07 379.785 ;
    END
  END rw0_rd_out[328]
  PIN rw0_rd_out[329]
    DIRECTION OUTPUT ;
    USE SIGNAL ;
    SHAPE ABUTMENT ;
    PORT
      LAYER M3 ;
      RECT 0 380.135 0.07 380.205 ;
    END
  END rw0_rd_out[329]
  PIN rw0_rd_out[330]
    DIRECTION OUTPUT ;
    USE SIGNAL ;
    SHAPE ABUTMENT ;
    PORT
      LAYER M3 ;
      RECT 0 380.555 0.07 380.625 ;
    END
  END rw0_rd_out[330]
  PIN rw0_rd_out[331]
    DIRECTION OUTPUT ;
    USE SIGNAL ;
    SHAPE ABUTMENT ;
    PORT
      LAYER M3 ;
      RECT 0 380.975 0.07 381.045 ;
    END
  END rw0_rd_out[331]
  PIN rw0_rd_out[332]
    DIRECTION OUTPUT ;
    USE SIGNAL ;
    SHAPE ABUTMENT ;
    PORT
      LAYER M3 ;
      RECT 0 381.395 0.07 381.465 ;
    END
  END rw0_rd_out[332]
  PIN rw0_rd_out[333]
    DIRECTION OUTPUT ;
    USE SIGNAL ;
    SHAPE ABUTMENT ;
    PORT
      LAYER M3 ;
      RECT 0 381.815 0.07 381.885 ;
    END
  END rw0_rd_out[333]
  PIN rw0_rd_out[334]
    DIRECTION OUTPUT ;
    USE SIGNAL ;
    SHAPE ABUTMENT ;
    PORT
      LAYER M3 ;
      RECT 0 382.235 0.07 382.305 ;
    END
  END rw0_rd_out[334]
  PIN rw0_rd_out[335]
    DIRECTION OUTPUT ;
    USE SIGNAL ;
    SHAPE ABUTMENT ;
    PORT
      LAYER M3 ;
      RECT 0 382.655 0.07 382.725 ;
    END
  END rw0_rd_out[335]
  PIN rw0_rd_out[336]
    DIRECTION OUTPUT ;
    USE SIGNAL ;
    SHAPE ABUTMENT ;
    PORT
      LAYER M3 ;
      RECT 0 383.075 0.07 383.145 ;
    END
  END rw0_rd_out[336]
  PIN rw0_rd_out[337]
    DIRECTION OUTPUT ;
    USE SIGNAL ;
    SHAPE ABUTMENT ;
    PORT
      LAYER M3 ;
      RECT 0 383.495 0.07 383.565 ;
    END
  END rw0_rd_out[337]
  PIN rw0_rd_out[338]
    DIRECTION OUTPUT ;
    USE SIGNAL ;
    SHAPE ABUTMENT ;
    PORT
      LAYER M3 ;
      RECT 0 383.915 0.07 383.985 ;
    END
  END rw0_rd_out[338]
  PIN rw0_rd_out[339]
    DIRECTION OUTPUT ;
    USE SIGNAL ;
    SHAPE ABUTMENT ;
    PORT
      LAYER M3 ;
      RECT 0 384.335 0.07 384.405 ;
    END
  END rw0_rd_out[339]
  PIN rw0_rd_out[340]
    DIRECTION OUTPUT ;
    USE SIGNAL ;
    SHAPE ABUTMENT ;
    PORT
      LAYER M3 ;
      RECT 0 384.755 0.07 384.825 ;
    END
  END rw0_rd_out[340]
  PIN rw0_rd_out[341]
    DIRECTION OUTPUT ;
    USE SIGNAL ;
    SHAPE ABUTMENT ;
    PORT
      LAYER M3 ;
      RECT 0 385.175 0.07 385.245 ;
    END
  END rw0_rd_out[341]
  PIN rw0_rd_out[342]
    DIRECTION OUTPUT ;
    USE SIGNAL ;
    SHAPE ABUTMENT ;
    PORT
      LAYER M3 ;
      RECT 0 385.595 0.07 385.665 ;
    END
  END rw0_rd_out[342]
  PIN rw0_rd_out[343]
    DIRECTION OUTPUT ;
    USE SIGNAL ;
    SHAPE ABUTMENT ;
    PORT
      LAYER M3 ;
      RECT 0 386.015 0.07 386.085 ;
    END
  END rw0_rd_out[343]
  PIN rw0_rd_out[344]
    DIRECTION OUTPUT ;
    USE SIGNAL ;
    SHAPE ABUTMENT ;
    PORT
      LAYER M3 ;
      RECT 0 386.435 0.07 386.505 ;
    END
  END rw0_rd_out[344]
  PIN rw0_rd_out[345]
    DIRECTION OUTPUT ;
    USE SIGNAL ;
    SHAPE ABUTMENT ;
    PORT
      LAYER M3 ;
      RECT 0 386.855 0.07 386.925 ;
    END
  END rw0_rd_out[345]
  PIN rw0_rd_out[346]
    DIRECTION OUTPUT ;
    USE SIGNAL ;
    SHAPE ABUTMENT ;
    PORT
      LAYER M3 ;
      RECT 0 387.275 0.07 387.345 ;
    END
  END rw0_rd_out[346]
  PIN rw0_rd_out[347]
    DIRECTION OUTPUT ;
    USE SIGNAL ;
    SHAPE ABUTMENT ;
    PORT
      LAYER M3 ;
      RECT 0 387.695 0.07 387.765 ;
    END
  END rw0_rd_out[347]
  PIN rw0_rd_out[348]
    DIRECTION OUTPUT ;
    USE SIGNAL ;
    SHAPE ABUTMENT ;
    PORT
      LAYER M3 ;
      RECT 0 388.115 0.07 388.185 ;
    END
  END rw0_rd_out[348]
  PIN rw0_rd_out[349]
    DIRECTION OUTPUT ;
    USE SIGNAL ;
    SHAPE ABUTMENT ;
    PORT
      LAYER M3 ;
      RECT 0 388.535 0.07 388.605 ;
    END
  END rw0_rd_out[349]
  PIN rw0_rd_out[350]
    DIRECTION OUTPUT ;
    USE SIGNAL ;
    SHAPE ABUTMENT ;
    PORT
      LAYER M3 ;
      RECT 0 388.955 0.07 389.025 ;
    END
  END rw0_rd_out[350]
  PIN rw0_rd_out[351]
    DIRECTION OUTPUT ;
    USE SIGNAL ;
    SHAPE ABUTMENT ;
    PORT
      LAYER M3 ;
      RECT 0 389.375 0.07 389.445 ;
    END
  END rw0_rd_out[351]
  PIN rw0_rd_out[352]
    DIRECTION OUTPUT ;
    USE SIGNAL ;
    SHAPE ABUTMENT ;
    PORT
      LAYER M3 ;
      RECT 0 389.795 0.07 389.865 ;
    END
  END rw0_rd_out[352]
  PIN rw0_rd_out[353]
    DIRECTION OUTPUT ;
    USE SIGNAL ;
    SHAPE ABUTMENT ;
    PORT
      LAYER M3 ;
      RECT 0 390.215 0.07 390.285 ;
    END
  END rw0_rd_out[353]
  PIN rw0_rd_out[354]
    DIRECTION OUTPUT ;
    USE SIGNAL ;
    SHAPE ABUTMENT ;
    PORT
      LAYER M3 ;
      RECT 0 390.635 0.07 390.705 ;
    END
  END rw0_rd_out[354]
  PIN rw0_rd_out[355]
    DIRECTION OUTPUT ;
    USE SIGNAL ;
    SHAPE ABUTMENT ;
    PORT
      LAYER M3 ;
      RECT 0 391.055 0.07 391.125 ;
    END
  END rw0_rd_out[355]
  PIN rw0_rd_out[356]
    DIRECTION OUTPUT ;
    USE SIGNAL ;
    SHAPE ABUTMENT ;
    PORT
      LAYER M3 ;
      RECT 0 391.475 0.07 391.545 ;
    END
  END rw0_rd_out[356]
  PIN rw0_rd_out[357]
    DIRECTION OUTPUT ;
    USE SIGNAL ;
    SHAPE ABUTMENT ;
    PORT
      LAYER M3 ;
      RECT 0 391.895 0.07 391.965 ;
    END
  END rw0_rd_out[357]
  PIN rw0_rd_out[358]
    DIRECTION OUTPUT ;
    USE SIGNAL ;
    SHAPE ABUTMENT ;
    PORT
      LAYER M3 ;
      RECT 0 392.315 0.07 392.385 ;
    END
  END rw0_rd_out[358]
  PIN rw0_rd_out[359]
    DIRECTION OUTPUT ;
    USE SIGNAL ;
    SHAPE ABUTMENT ;
    PORT
      LAYER M3 ;
      RECT 0 392.735 0.07 392.805 ;
    END
  END rw0_rd_out[359]
  PIN rw0_rd_out[360]
    DIRECTION OUTPUT ;
    USE SIGNAL ;
    SHAPE ABUTMENT ;
    PORT
      LAYER M3 ;
      RECT 0 393.155 0.07 393.225 ;
    END
  END rw0_rd_out[360]
  PIN rw0_rd_out[361]
    DIRECTION OUTPUT ;
    USE SIGNAL ;
    SHAPE ABUTMENT ;
    PORT
      LAYER M3 ;
      RECT 0 393.575 0.07 393.645 ;
    END
  END rw0_rd_out[361]
  PIN rw0_rd_out[362]
    DIRECTION OUTPUT ;
    USE SIGNAL ;
    SHAPE ABUTMENT ;
    PORT
      LAYER M3 ;
      RECT 0 393.995 0.07 394.065 ;
    END
  END rw0_rd_out[362]
  PIN rw0_rd_out[363]
    DIRECTION OUTPUT ;
    USE SIGNAL ;
    SHAPE ABUTMENT ;
    PORT
      LAYER M3 ;
      RECT 0 394.415 0.07 394.485 ;
    END
  END rw0_rd_out[363]
  PIN rw0_rd_out[364]
    DIRECTION OUTPUT ;
    USE SIGNAL ;
    SHAPE ABUTMENT ;
    PORT
      LAYER M3 ;
      RECT 0 394.835 0.07 394.905 ;
    END
  END rw0_rd_out[364]
  PIN rw0_rd_out[365]
    DIRECTION OUTPUT ;
    USE SIGNAL ;
    SHAPE ABUTMENT ;
    PORT
      LAYER M3 ;
      RECT 0 395.255 0.07 395.325 ;
    END
  END rw0_rd_out[365]
  PIN rw0_rd_out[366]
    DIRECTION OUTPUT ;
    USE SIGNAL ;
    SHAPE ABUTMENT ;
    PORT
      LAYER M3 ;
      RECT 0 395.675 0.07 395.745 ;
    END
  END rw0_rd_out[366]
  PIN rw0_rd_out[367]
    DIRECTION OUTPUT ;
    USE SIGNAL ;
    SHAPE ABUTMENT ;
    PORT
      LAYER M3 ;
      RECT 0 396.095 0.07 396.165 ;
    END
  END rw0_rd_out[367]
  PIN rw0_rd_out[368]
    DIRECTION OUTPUT ;
    USE SIGNAL ;
    SHAPE ABUTMENT ;
    PORT
      LAYER M3 ;
      RECT 0 396.515 0.07 396.585 ;
    END
  END rw0_rd_out[368]
  PIN rw0_rd_out[369]
    DIRECTION OUTPUT ;
    USE SIGNAL ;
    SHAPE ABUTMENT ;
    PORT
      LAYER M3 ;
      RECT 0 396.935 0.07 397.005 ;
    END
  END rw0_rd_out[369]
  PIN rw0_rd_out[370]
    DIRECTION OUTPUT ;
    USE SIGNAL ;
    SHAPE ABUTMENT ;
    PORT
      LAYER M3 ;
      RECT 0 397.355 0.07 397.425 ;
    END
  END rw0_rd_out[370]
  PIN rw0_rd_out[371]
    DIRECTION OUTPUT ;
    USE SIGNAL ;
    SHAPE ABUTMENT ;
    PORT
      LAYER M3 ;
      RECT 0 397.775 0.07 397.845 ;
    END
  END rw0_rd_out[371]
  PIN rw0_rd_out[372]
    DIRECTION OUTPUT ;
    USE SIGNAL ;
    SHAPE ABUTMENT ;
    PORT
      LAYER M3 ;
      RECT 0 398.195 0.07 398.265 ;
    END
  END rw0_rd_out[372]
  PIN rw0_rd_out[373]
    DIRECTION OUTPUT ;
    USE SIGNAL ;
    SHAPE ABUTMENT ;
    PORT
      LAYER M3 ;
      RECT 0 398.615 0.07 398.685 ;
    END
  END rw0_rd_out[373]
  PIN rw0_rd_out[374]
    DIRECTION OUTPUT ;
    USE SIGNAL ;
    SHAPE ABUTMENT ;
    PORT
      LAYER M3 ;
      RECT 0 399.035 0.07 399.105 ;
    END
  END rw0_rd_out[374]
  PIN rw0_rd_out[375]
    DIRECTION OUTPUT ;
    USE SIGNAL ;
    SHAPE ABUTMENT ;
    PORT
      LAYER M3 ;
      RECT 0 399.455 0.07 399.525 ;
    END
  END rw0_rd_out[375]
  PIN rw0_rd_out[376]
    DIRECTION OUTPUT ;
    USE SIGNAL ;
    SHAPE ABUTMENT ;
    PORT
      LAYER M3 ;
      RECT 0 399.875 0.07 399.945 ;
    END
  END rw0_rd_out[376]
  PIN rw0_rd_out[377]
    DIRECTION OUTPUT ;
    USE SIGNAL ;
    SHAPE ABUTMENT ;
    PORT
      LAYER M3 ;
      RECT 0 400.295 0.07 400.365 ;
    END
  END rw0_rd_out[377]
  PIN rw0_rd_out[378]
    DIRECTION OUTPUT ;
    USE SIGNAL ;
    SHAPE ABUTMENT ;
    PORT
      LAYER M3 ;
      RECT 0 400.715 0.07 400.785 ;
    END
  END rw0_rd_out[378]
  PIN rw0_rd_out[379]
    DIRECTION OUTPUT ;
    USE SIGNAL ;
    SHAPE ABUTMENT ;
    PORT
      LAYER M3 ;
      RECT 0 401.135 0.07 401.205 ;
    END
  END rw0_rd_out[379]
  PIN rw0_rd_out[380]
    DIRECTION OUTPUT ;
    USE SIGNAL ;
    SHAPE ABUTMENT ;
    PORT
      LAYER M3 ;
      RECT 0 401.555 0.07 401.625 ;
    END
  END rw0_rd_out[380]
  PIN rw0_rd_out[381]
    DIRECTION OUTPUT ;
    USE SIGNAL ;
    SHAPE ABUTMENT ;
    PORT
      LAYER M3 ;
      RECT 0 401.975 0.07 402.045 ;
    END
  END rw0_rd_out[381]
  PIN rw0_rd_out[382]
    DIRECTION OUTPUT ;
    USE SIGNAL ;
    SHAPE ABUTMENT ;
    PORT
      LAYER M3 ;
      RECT 0 402.395 0.07 402.465 ;
    END
  END rw0_rd_out[382]
  PIN rw0_rd_out[383]
    DIRECTION OUTPUT ;
    USE SIGNAL ;
    SHAPE ABUTMENT ;
    PORT
      LAYER M3 ;
      RECT 0 402.815 0.07 402.885 ;
    END
  END rw0_rd_out[383]
  PIN rw0_rd_out[384]
    DIRECTION OUTPUT ;
    USE SIGNAL ;
    SHAPE ABUTMENT ;
    PORT
      LAYER M3 ;
      RECT 0 403.235 0.07 403.305 ;
    END
  END rw0_rd_out[384]
  PIN rw0_rd_out[385]
    DIRECTION OUTPUT ;
    USE SIGNAL ;
    SHAPE ABUTMENT ;
    PORT
      LAYER M3 ;
      RECT 0 403.655 0.07 403.725 ;
    END
  END rw0_rd_out[385]
  PIN rw0_rd_out[386]
    DIRECTION OUTPUT ;
    USE SIGNAL ;
    SHAPE ABUTMENT ;
    PORT
      LAYER M3 ;
      RECT 0 404.075 0.07 404.145 ;
    END
  END rw0_rd_out[386]
  PIN rw0_rd_out[387]
    DIRECTION OUTPUT ;
    USE SIGNAL ;
    SHAPE ABUTMENT ;
    PORT
      LAYER M3 ;
      RECT 0 404.495 0.07 404.565 ;
    END
  END rw0_rd_out[387]
  PIN rw0_rd_out[388]
    DIRECTION OUTPUT ;
    USE SIGNAL ;
    SHAPE ABUTMENT ;
    PORT
      LAYER M3 ;
      RECT 0 404.915 0.07 404.985 ;
    END
  END rw0_rd_out[388]
  PIN rw0_rd_out[389]
    DIRECTION OUTPUT ;
    USE SIGNAL ;
    SHAPE ABUTMENT ;
    PORT
      LAYER M3 ;
      RECT 0 405.335 0.07 405.405 ;
    END
  END rw0_rd_out[389]
  PIN rw0_rd_out[390]
    DIRECTION OUTPUT ;
    USE SIGNAL ;
    SHAPE ABUTMENT ;
    PORT
      LAYER M3 ;
      RECT 0 405.755 0.07 405.825 ;
    END
  END rw0_rd_out[390]
  PIN rw0_rd_out[391]
    DIRECTION OUTPUT ;
    USE SIGNAL ;
    SHAPE ABUTMENT ;
    PORT
      LAYER M3 ;
      RECT 0 406.175 0.07 406.245 ;
    END
  END rw0_rd_out[391]
  PIN rw0_rd_out[392]
    DIRECTION OUTPUT ;
    USE SIGNAL ;
    SHAPE ABUTMENT ;
    PORT
      LAYER M3 ;
      RECT 0 406.595 0.07 406.665 ;
    END
  END rw0_rd_out[392]
  PIN rw0_rd_out[393]
    DIRECTION OUTPUT ;
    USE SIGNAL ;
    SHAPE ABUTMENT ;
    PORT
      LAYER M3 ;
      RECT 0 407.015 0.07 407.085 ;
    END
  END rw0_rd_out[393]
  PIN rw0_rd_out[394]
    DIRECTION OUTPUT ;
    USE SIGNAL ;
    SHAPE ABUTMENT ;
    PORT
      LAYER M3 ;
      RECT 0 407.435 0.07 407.505 ;
    END
  END rw0_rd_out[394]
  PIN rw0_rd_out[395]
    DIRECTION OUTPUT ;
    USE SIGNAL ;
    SHAPE ABUTMENT ;
    PORT
      LAYER M3 ;
      RECT 0 407.855 0.07 407.925 ;
    END
  END rw0_rd_out[395]
  PIN rw0_rd_out[396]
    DIRECTION OUTPUT ;
    USE SIGNAL ;
    SHAPE ABUTMENT ;
    PORT
      LAYER M3 ;
      RECT 0 408.275 0.07 408.345 ;
    END
  END rw0_rd_out[396]
  PIN rw0_rd_out[397]
    DIRECTION OUTPUT ;
    USE SIGNAL ;
    SHAPE ABUTMENT ;
    PORT
      LAYER M3 ;
      RECT 0 408.695 0.07 408.765 ;
    END
  END rw0_rd_out[397]
  PIN rw0_rd_out[398]
    DIRECTION OUTPUT ;
    USE SIGNAL ;
    SHAPE ABUTMENT ;
    PORT
      LAYER M3 ;
      RECT 0 409.115 0.07 409.185 ;
    END
  END rw0_rd_out[398]
  PIN rw0_rd_out[399]
    DIRECTION OUTPUT ;
    USE SIGNAL ;
    SHAPE ABUTMENT ;
    PORT
      LAYER M3 ;
      RECT 0 409.535 0.07 409.605 ;
    END
  END rw0_rd_out[399]
  PIN rw0_rd_out[400]
    DIRECTION OUTPUT ;
    USE SIGNAL ;
    SHAPE ABUTMENT ;
    PORT
      LAYER M3 ;
      RECT 0 409.955 0.07 410.025 ;
    END
  END rw0_rd_out[400]
  PIN rw0_rd_out[401]
    DIRECTION OUTPUT ;
    USE SIGNAL ;
    SHAPE ABUTMENT ;
    PORT
      LAYER M3 ;
      RECT 0 410.375 0.07 410.445 ;
    END
  END rw0_rd_out[401]
  PIN rw0_rd_out[402]
    DIRECTION OUTPUT ;
    USE SIGNAL ;
    SHAPE ABUTMENT ;
    PORT
      LAYER M3 ;
      RECT 0 410.795 0.07 410.865 ;
    END
  END rw0_rd_out[402]
  PIN rw0_rd_out[403]
    DIRECTION OUTPUT ;
    USE SIGNAL ;
    SHAPE ABUTMENT ;
    PORT
      LAYER M3 ;
      RECT 0 411.215 0.07 411.285 ;
    END
  END rw0_rd_out[403]
  PIN rw0_rd_out[404]
    DIRECTION OUTPUT ;
    USE SIGNAL ;
    SHAPE ABUTMENT ;
    PORT
      LAYER M3 ;
      RECT 0 411.635 0.07 411.705 ;
    END
  END rw0_rd_out[404]
  PIN rw0_rd_out[405]
    DIRECTION OUTPUT ;
    USE SIGNAL ;
    SHAPE ABUTMENT ;
    PORT
      LAYER M3 ;
      RECT 0 412.055 0.07 412.125 ;
    END
  END rw0_rd_out[405]
  PIN rw0_rd_out[406]
    DIRECTION OUTPUT ;
    USE SIGNAL ;
    SHAPE ABUTMENT ;
    PORT
      LAYER M3 ;
      RECT 0 412.475 0.07 412.545 ;
    END
  END rw0_rd_out[406]
  PIN rw0_rd_out[407]
    DIRECTION OUTPUT ;
    USE SIGNAL ;
    SHAPE ABUTMENT ;
    PORT
      LAYER M3 ;
      RECT 0 412.895 0.07 412.965 ;
    END
  END rw0_rd_out[407]
  PIN rw0_rd_out[408]
    DIRECTION OUTPUT ;
    USE SIGNAL ;
    SHAPE ABUTMENT ;
    PORT
      LAYER M3 ;
      RECT 0 413.315 0.07 413.385 ;
    END
  END rw0_rd_out[408]
  PIN rw0_rd_out[409]
    DIRECTION OUTPUT ;
    USE SIGNAL ;
    SHAPE ABUTMENT ;
    PORT
      LAYER M3 ;
      RECT 0 413.735 0.07 413.805 ;
    END
  END rw0_rd_out[409]
  PIN rw0_rd_out[410]
    DIRECTION OUTPUT ;
    USE SIGNAL ;
    SHAPE ABUTMENT ;
    PORT
      LAYER M3 ;
      RECT 0 414.155 0.07 414.225 ;
    END
  END rw0_rd_out[410]
  PIN rw0_rd_out[411]
    DIRECTION OUTPUT ;
    USE SIGNAL ;
    SHAPE ABUTMENT ;
    PORT
      LAYER M3 ;
      RECT 0 414.575 0.07 414.645 ;
    END
  END rw0_rd_out[411]
  PIN rw0_rd_out[412]
    DIRECTION OUTPUT ;
    USE SIGNAL ;
    SHAPE ABUTMENT ;
    PORT
      LAYER M3 ;
      RECT 0 414.995 0.07 415.065 ;
    END
  END rw0_rd_out[412]
  PIN rw0_rd_out[413]
    DIRECTION OUTPUT ;
    USE SIGNAL ;
    SHAPE ABUTMENT ;
    PORT
      LAYER M3 ;
      RECT 0 415.415 0.07 415.485 ;
    END
  END rw0_rd_out[413]
  PIN rw0_rd_out[414]
    DIRECTION OUTPUT ;
    USE SIGNAL ;
    SHAPE ABUTMENT ;
    PORT
      LAYER M3 ;
      RECT 0 415.835 0.07 415.905 ;
    END
  END rw0_rd_out[414]
  PIN rw0_rd_out[415]
    DIRECTION OUTPUT ;
    USE SIGNAL ;
    SHAPE ABUTMENT ;
    PORT
      LAYER M3 ;
      RECT 0 416.255 0.07 416.325 ;
    END
  END rw0_rd_out[415]
  PIN rw0_rd_out[416]
    DIRECTION OUTPUT ;
    USE SIGNAL ;
    SHAPE ABUTMENT ;
    PORT
      LAYER M3 ;
      RECT 0 416.675 0.07 416.745 ;
    END
  END rw0_rd_out[416]
  PIN rw0_rd_out[417]
    DIRECTION OUTPUT ;
    USE SIGNAL ;
    SHAPE ABUTMENT ;
    PORT
      LAYER M3 ;
      RECT 0 417.095 0.07 417.165 ;
    END
  END rw0_rd_out[417]
  PIN rw0_rd_out[418]
    DIRECTION OUTPUT ;
    USE SIGNAL ;
    SHAPE ABUTMENT ;
    PORT
      LAYER M3 ;
      RECT 0 417.515 0.07 417.585 ;
    END
  END rw0_rd_out[418]
  PIN rw0_rd_out[419]
    DIRECTION OUTPUT ;
    USE SIGNAL ;
    SHAPE ABUTMENT ;
    PORT
      LAYER M3 ;
      RECT 0 417.935 0.07 418.005 ;
    END
  END rw0_rd_out[419]
  PIN rw0_rd_out[420]
    DIRECTION OUTPUT ;
    USE SIGNAL ;
    SHAPE ABUTMENT ;
    PORT
      LAYER M3 ;
      RECT 0 418.355 0.07 418.425 ;
    END
  END rw0_rd_out[420]
  PIN rw0_rd_out[421]
    DIRECTION OUTPUT ;
    USE SIGNAL ;
    SHAPE ABUTMENT ;
    PORT
      LAYER M3 ;
      RECT 0 418.775 0.07 418.845 ;
    END
  END rw0_rd_out[421]
  PIN rw0_rd_out[422]
    DIRECTION OUTPUT ;
    USE SIGNAL ;
    SHAPE ABUTMENT ;
    PORT
      LAYER M3 ;
      RECT 0 419.195 0.07 419.265 ;
    END
  END rw0_rd_out[422]
  PIN rw0_rd_out[423]
    DIRECTION OUTPUT ;
    USE SIGNAL ;
    SHAPE ABUTMENT ;
    PORT
      LAYER M3 ;
      RECT 0 419.615 0.07 419.685 ;
    END
  END rw0_rd_out[423]
  PIN rw0_rd_out[424]
    DIRECTION OUTPUT ;
    USE SIGNAL ;
    SHAPE ABUTMENT ;
    PORT
      LAYER M3 ;
      RECT 0 420.035 0.07 420.105 ;
    END
  END rw0_rd_out[424]
  PIN rw0_rd_out[425]
    DIRECTION OUTPUT ;
    USE SIGNAL ;
    SHAPE ABUTMENT ;
    PORT
      LAYER M3 ;
      RECT 0 420.455 0.07 420.525 ;
    END
  END rw0_rd_out[425]
  PIN rw0_rd_out[426]
    DIRECTION OUTPUT ;
    USE SIGNAL ;
    SHAPE ABUTMENT ;
    PORT
      LAYER M3 ;
      RECT 0 420.875 0.07 420.945 ;
    END
  END rw0_rd_out[426]
  PIN rw0_rd_out[427]
    DIRECTION OUTPUT ;
    USE SIGNAL ;
    SHAPE ABUTMENT ;
    PORT
      LAYER M3 ;
      RECT 0 421.295 0.07 421.365 ;
    END
  END rw0_rd_out[427]
  PIN rw0_rd_out[428]
    DIRECTION OUTPUT ;
    USE SIGNAL ;
    SHAPE ABUTMENT ;
    PORT
      LAYER M3 ;
      RECT 0 421.715 0.07 421.785 ;
    END
  END rw0_rd_out[428]
  PIN rw0_rd_out[429]
    DIRECTION OUTPUT ;
    USE SIGNAL ;
    SHAPE ABUTMENT ;
    PORT
      LAYER M3 ;
      RECT 0 422.135 0.07 422.205 ;
    END
  END rw0_rd_out[429]
  PIN rw0_rd_out[430]
    DIRECTION OUTPUT ;
    USE SIGNAL ;
    SHAPE ABUTMENT ;
    PORT
      LAYER M3 ;
      RECT 0 422.555 0.07 422.625 ;
    END
  END rw0_rd_out[430]
  PIN rw0_rd_out[431]
    DIRECTION OUTPUT ;
    USE SIGNAL ;
    SHAPE ABUTMENT ;
    PORT
      LAYER M3 ;
      RECT 0 422.975 0.07 423.045 ;
    END
  END rw0_rd_out[431]
  PIN rw0_rd_out[432]
    DIRECTION OUTPUT ;
    USE SIGNAL ;
    SHAPE ABUTMENT ;
    PORT
      LAYER M3 ;
      RECT 0 423.395 0.07 423.465 ;
    END
  END rw0_rd_out[432]
  PIN rw0_rd_out[433]
    DIRECTION OUTPUT ;
    USE SIGNAL ;
    SHAPE ABUTMENT ;
    PORT
      LAYER M3 ;
      RECT 0 423.815 0.07 423.885 ;
    END
  END rw0_rd_out[433]
  PIN rw0_rd_out[434]
    DIRECTION OUTPUT ;
    USE SIGNAL ;
    SHAPE ABUTMENT ;
    PORT
      LAYER M3 ;
      RECT 0 424.235 0.07 424.305 ;
    END
  END rw0_rd_out[434]
  PIN rw0_rd_out[435]
    DIRECTION OUTPUT ;
    USE SIGNAL ;
    SHAPE ABUTMENT ;
    PORT
      LAYER M3 ;
      RECT 0 424.655 0.07 424.725 ;
    END
  END rw0_rd_out[435]
  PIN rw0_rd_out[436]
    DIRECTION OUTPUT ;
    USE SIGNAL ;
    SHAPE ABUTMENT ;
    PORT
      LAYER M3 ;
      RECT 0 425.075 0.07 425.145 ;
    END
  END rw0_rd_out[436]
  PIN rw0_rd_out[437]
    DIRECTION OUTPUT ;
    USE SIGNAL ;
    SHAPE ABUTMENT ;
    PORT
      LAYER M3 ;
      RECT 0 425.495 0.07 425.565 ;
    END
  END rw0_rd_out[437]
  PIN rw0_rd_out[438]
    DIRECTION OUTPUT ;
    USE SIGNAL ;
    SHAPE ABUTMENT ;
    PORT
      LAYER M3 ;
      RECT 0 425.915 0.07 425.985 ;
    END
  END rw0_rd_out[438]
  PIN rw0_rd_out[439]
    DIRECTION OUTPUT ;
    USE SIGNAL ;
    SHAPE ABUTMENT ;
    PORT
      LAYER M3 ;
      RECT 0 426.335 0.07 426.405 ;
    END
  END rw0_rd_out[439]
  PIN rw0_rd_out[440]
    DIRECTION OUTPUT ;
    USE SIGNAL ;
    SHAPE ABUTMENT ;
    PORT
      LAYER M3 ;
      RECT 0 426.755 0.07 426.825 ;
    END
  END rw0_rd_out[440]
  PIN rw0_rd_out[441]
    DIRECTION OUTPUT ;
    USE SIGNAL ;
    SHAPE ABUTMENT ;
    PORT
      LAYER M3 ;
      RECT 0 427.175 0.07 427.245 ;
    END
  END rw0_rd_out[441]
  PIN rw0_rd_out[442]
    DIRECTION OUTPUT ;
    USE SIGNAL ;
    SHAPE ABUTMENT ;
    PORT
      LAYER M3 ;
      RECT 0 427.595 0.07 427.665 ;
    END
  END rw0_rd_out[442]
  PIN rw0_rd_out[443]
    DIRECTION OUTPUT ;
    USE SIGNAL ;
    SHAPE ABUTMENT ;
    PORT
      LAYER M3 ;
      RECT 0 428.015 0.07 428.085 ;
    END
  END rw0_rd_out[443]
  PIN rw0_rd_out[444]
    DIRECTION OUTPUT ;
    USE SIGNAL ;
    SHAPE ABUTMENT ;
    PORT
      LAYER M3 ;
      RECT 0 428.435 0.07 428.505 ;
    END
  END rw0_rd_out[444]
  PIN rw0_rd_out[445]
    DIRECTION OUTPUT ;
    USE SIGNAL ;
    SHAPE ABUTMENT ;
    PORT
      LAYER M3 ;
      RECT 0 428.855 0.07 428.925 ;
    END
  END rw0_rd_out[445]
  PIN rw0_rd_out[446]
    DIRECTION OUTPUT ;
    USE SIGNAL ;
    SHAPE ABUTMENT ;
    PORT
      LAYER M3 ;
      RECT 0 429.275 0.07 429.345 ;
    END
  END rw0_rd_out[446]
  PIN rw0_rd_out[447]
    DIRECTION OUTPUT ;
    USE SIGNAL ;
    SHAPE ABUTMENT ;
    PORT
      LAYER M3 ;
      RECT 0 429.695 0.07 429.765 ;
    END
  END rw0_rd_out[447]
  PIN rw0_rd_out[448]
    DIRECTION OUTPUT ;
    USE SIGNAL ;
    SHAPE ABUTMENT ;
    PORT
      LAYER M3 ;
      RECT 0 430.115 0.07 430.185 ;
    END
  END rw0_rd_out[448]
  PIN rw0_rd_out[449]
    DIRECTION OUTPUT ;
    USE SIGNAL ;
    SHAPE ABUTMENT ;
    PORT
      LAYER M3 ;
      RECT 0 430.535 0.07 430.605 ;
    END
  END rw0_rd_out[449]
  PIN rw0_rd_out[450]
    DIRECTION OUTPUT ;
    USE SIGNAL ;
    SHAPE ABUTMENT ;
    PORT
      LAYER M3 ;
      RECT 0 430.955 0.07 431.025 ;
    END
  END rw0_rd_out[450]
  PIN rw0_rd_out[451]
    DIRECTION OUTPUT ;
    USE SIGNAL ;
    SHAPE ABUTMENT ;
    PORT
      LAYER M3 ;
      RECT 0 431.375 0.07 431.445 ;
    END
  END rw0_rd_out[451]
  PIN rw0_rd_out[452]
    DIRECTION OUTPUT ;
    USE SIGNAL ;
    SHAPE ABUTMENT ;
    PORT
      LAYER M3 ;
      RECT 0 431.795 0.07 431.865 ;
    END
  END rw0_rd_out[452]
  PIN rw0_rd_out[453]
    DIRECTION OUTPUT ;
    USE SIGNAL ;
    SHAPE ABUTMENT ;
    PORT
      LAYER M3 ;
      RECT 0 432.215 0.07 432.285 ;
    END
  END rw0_rd_out[453]
  PIN rw0_rd_out[454]
    DIRECTION OUTPUT ;
    USE SIGNAL ;
    SHAPE ABUTMENT ;
    PORT
      LAYER M3 ;
      RECT 0 432.635 0.07 432.705 ;
    END
  END rw0_rd_out[454]
  PIN rw0_rd_out[455]
    DIRECTION OUTPUT ;
    USE SIGNAL ;
    SHAPE ABUTMENT ;
    PORT
      LAYER M3 ;
      RECT 0 433.055 0.07 433.125 ;
    END
  END rw0_rd_out[455]
  PIN rw0_rd_out[456]
    DIRECTION OUTPUT ;
    USE SIGNAL ;
    SHAPE ABUTMENT ;
    PORT
      LAYER M3 ;
      RECT 0 433.475 0.07 433.545 ;
    END
  END rw0_rd_out[456]
  PIN rw0_rd_out[457]
    DIRECTION OUTPUT ;
    USE SIGNAL ;
    SHAPE ABUTMENT ;
    PORT
      LAYER M3 ;
      RECT 0 433.895 0.07 433.965 ;
    END
  END rw0_rd_out[457]
  PIN rw0_rd_out[458]
    DIRECTION OUTPUT ;
    USE SIGNAL ;
    SHAPE ABUTMENT ;
    PORT
      LAYER M3 ;
      RECT 0 434.315 0.07 434.385 ;
    END
  END rw0_rd_out[458]
  PIN rw0_rd_out[459]
    DIRECTION OUTPUT ;
    USE SIGNAL ;
    SHAPE ABUTMENT ;
    PORT
      LAYER M3 ;
      RECT 0 434.735 0.07 434.805 ;
    END
  END rw0_rd_out[459]
  PIN rw0_rd_out[460]
    DIRECTION OUTPUT ;
    USE SIGNAL ;
    SHAPE ABUTMENT ;
    PORT
      LAYER M3 ;
      RECT 0 435.155 0.07 435.225 ;
    END
  END rw0_rd_out[460]
  PIN rw0_rd_out[461]
    DIRECTION OUTPUT ;
    USE SIGNAL ;
    SHAPE ABUTMENT ;
    PORT
      LAYER M3 ;
      RECT 0 435.575 0.07 435.645 ;
    END
  END rw0_rd_out[461]
  PIN rw0_rd_out[462]
    DIRECTION OUTPUT ;
    USE SIGNAL ;
    SHAPE ABUTMENT ;
    PORT
      LAYER M3 ;
      RECT 0 435.995 0.07 436.065 ;
    END
  END rw0_rd_out[462]
  PIN rw0_rd_out[463]
    DIRECTION OUTPUT ;
    USE SIGNAL ;
    SHAPE ABUTMENT ;
    PORT
      LAYER M3 ;
      RECT 0 436.415 0.07 436.485 ;
    END
  END rw0_rd_out[463]
  PIN rw0_rd_out[464]
    DIRECTION OUTPUT ;
    USE SIGNAL ;
    SHAPE ABUTMENT ;
    PORT
      LAYER M3 ;
      RECT 0 436.835 0.07 436.905 ;
    END
  END rw0_rd_out[464]
  PIN rw0_rd_out[465]
    DIRECTION OUTPUT ;
    USE SIGNAL ;
    SHAPE ABUTMENT ;
    PORT
      LAYER M3 ;
      RECT 0 437.255 0.07 437.325 ;
    END
  END rw0_rd_out[465]
  PIN rw0_rd_out[466]
    DIRECTION OUTPUT ;
    USE SIGNAL ;
    SHAPE ABUTMENT ;
    PORT
      LAYER M3 ;
      RECT 0 437.675 0.07 437.745 ;
    END
  END rw0_rd_out[466]
  PIN rw0_rd_out[467]
    DIRECTION OUTPUT ;
    USE SIGNAL ;
    SHAPE ABUTMENT ;
    PORT
      LAYER M3 ;
      RECT 0 438.095 0.07 438.165 ;
    END
  END rw0_rd_out[467]
  PIN rw0_rd_out[468]
    DIRECTION OUTPUT ;
    USE SIGNAL ;
    SHAPE ABUTMENT ;
    PORT
      LAYER M3 ;
      RECT 0 438.515 0.07 438.585 ;
    END
  END rw0_rd_out[468]
  PIN rw0_rd_out[469]
    DIRECTION OUTPUT ;
    USE SIGNAL ;
    SHAPE ABUTMENT ;
    PORT
      LAYER M3 ;
      RECT 0 438.935 0.07 439.005 ;
    END
  END rw0_rd_out[469]
  PIN rw0_rd_out[470]
    DIRECTION OUTPUT ;
    USE SIGNAL ;
    SHAPE ABUTMENT ;
    PORT
      LAYER M3 ;
      RECT 0 439.355 0.07 439.425 ;
    END
  END rw0_rd_out[470]
  PIN rw0_rd_out[471]
    DIRECTION OUTPUT ;
    USE SIGNAL ;
    SHAPE ABUTMENT ;
    PORT
      LAYER M3 ;
      RECT 0 439.775 0.07 439.845 ;
    END
  END rw0_rd_out[471]
  PIN rw0_rd_out[472]
    DIRECTION OUTPUT ;
    USE SIGNAL ;
    SHAPE ABUTMENT ;
    PORT
      LAYER M3 ;
      RECT 0 440.195 0.07 440.265 ;
    END
  END rw0_rd_out[472]
  PIN rw0_rd_out[473]
    DIRECTION OUTPUT ;
    USE SIGNAL ;
    SHAPE ABUTMENT ;
    PORT
      LAYER M3 ;
      RECT 0 440.615 0.07 440.685 ;
    END
  END rw0_rd_out[473]
  PIN rw0_rd_out[474]
    DIRECTION OUTPUT ;
    USE SIGNAL ;
    SHAPE ABUTMENT ;
    PORT
      LAYER M3 ;
      RECT 0 441.035 0.07 441.105 ;
    END
  END rw0_rd_out[474]
  PIN rw0_rd_out[475]
    DIRECTION OUTPUT ;
    USE SIGNAL ;
    SHAPE ABUTMENT ;
    PORT
      LAYER M3 ;
      RECT 0 441.455 0.07 441.525 ;
    END
  END rw0_rd_out[475]
  PIN rw0_rd_out[476]
    DIRECTION OUTPUT ;
    USE SIGNAL ;
    SHAPE ABUTMENT ;
    PORT
      LAYER M3 ;
      RECT 0 441.875 0.07 441.945 ;
    END
  END rw0_rd_out[476]
  PIN rw0_rd_out[477]
    DIRECTION OUTPUT ;
    USE SIGNAL ;
    SHAPE ABUTMENT ;
    PORT
      LAYER M3 ;
      RECT 0 442.295 0.07 442.365 ;
    END
  END rw0_rd_out[477]
  PIN rw0_rd_out[478]
    DIRECTION OUTPUT ;
    USE SIGNAL ;
    SHAPE ABUTMENT ;
    PORT
      LAYER M3 ;
      RECT 0 442.715 0.07 442.785 ;
    END
  END rw0_rd_out[478]
  PIN rw0_rd_out[479]
    DIRECTION OUTPUT ;
    USE SIGNAL ;
    SHAPE ABUTMENT ;
    PORT
      LAYER M3 ;
      RECT 0 443.135 0.07 443.205 ;
    END
  END rw0_rd_out[479]
  PIN rw0_rd_out[480]
    DIRECTION OUTPUT ;
    USE SIGNAL ;
    SHAPE ABUTMENT ;
    PORT
      LAYER M3 ;
      RECT 0 443.555 0.07 443.625 ;
    END
  END rw0_rd_out[480]
  PIN rw0_rd_out[481]
    DIRECTION OUTPUT ;
    USE SIGNAL ;
    SHAPE ABUTMENT ;
    PORT
      LAYER M3 ;
      RECT 0 443.975 0.07 444.045 ;
    END
  END rw0_rd_out[481]
  PIN rw0_rd_out[482]
    DIRECTION OUTPUT ;
    USE SIGNAL ;
    SHAPE ABUTMENT ;
    PORT
      LAYER M3 ;
      RECT 0 444.395 0.07 444.465 ;
    END
  END rw0_rd_out[482]
  PIN rw0_rd_out[483]
    DIRECTION OUTPUT ;
    USE SIGNAL ;
    SHAPE ABUTMENT ;
    PORT
      LAYER M3 ;
      RECT 0 444.815 0.07 444.885 ;
    END
  END rw0_rd_out[483]
  PIN rw0_rd_out[484]
    DIRECTION OUTPUT ;
    USE SIGNAL ;
    SHAPE ABUTMENT ;
    PORT
      LAYER M3 ;
      RECT 0 445.235 0.07 445.305 ;
    END
  END rw0_rd_out[484]
  PIN rw0_rd_out[485]
    DIRECTION OUTPUT ;
    USE SIGNAL ;
    SHAPE ABUTMENT ;
    PORT
      LAYER M3 ;
      RECT 0 445.655 0.07 445.725 ;
    END
  END rw0_rd_out[485]
  PIN rw0_rd_out[486]
    DIRECTION OUTPUT ;
    USE SIGNAL ;
    SHAPE ABUTMENT ;
    PORT
      LAYER M3 ;
      RECT 0 446.075 0.07 446.145 ;
    END
  END rw0_rd_out[486]
  PIN rw0_rd_out[487]
    DIRECTION OUTPUT ;
    USE SIGNAL ;
    SHAPE ABUTMENT ;
    PORT
      LAYER M3 ;
      RECT 0 446.495 0.07 446.565 ;
    END
  END rw0_rd_out[487]
  PIN rw0_rd_out[488]
    DIRECTION OUTPUT ;
    USE SIGNAL ;
    SHAPE ABUTMENT ;
    PORT
      LAYER M3 ;
      RECT 0 446.915 0.07 446.985 ;
    END
  END rw0_rd_out[488]
  PIN rw0_rd_out[489]
    DIRECTION OUTPUT ;
    USE SIGNAL ;
    SHAPE ABUTMENT ;
    PORT
      LAYER M3 ;
      RECT 0 447.335 0.07 447.405 ;
    END
  END rw0_rd_out[489]
  PIN rw0_rd_out[490]
    DIRECTION OUTPUT ;
    USE SIGNAL ;
    SHAPE ABUTMENT ;
    PORT
      LAYER M3 ;
      RECT 0 447.755 0.07 447.825 ;
    END
  END rw0_rd_out[490]
  PIN rw0_rd_out[491]
    DIRECTION OUTPUT ;
    USE SIGNAL ;
    SHAPE ABUTMENT ;
    PORT
      LAYER M3 ;
      RECT 0 448.175 0.07 448.245 ;
    END
  END rw0_rd_out[491]
  PIN rw0_rd_out[492]
    DIRECTION OUTPUT ;
    USE SIGNAL ;
    SHAPE ABUTMENT ;
    PORT
      LAYER M3 ;
      RECT 0 448.595 0.07 448.665 ;
    END
  END rw0_rd_out[492]
  PIN rw0_rd_out[493]
    DIRECTION OUTPUT ;
    USE SIGNAL ;
    SHAPE ABUTMENT ;
    PORT
      LAYER M3 ;
      RECT 0 449.015 0.07 449.085 ;
    END
  END rw0_rd_out[493]
  PIN rw0_rd_out[494]
    DIRECTION OUTPUT ;
    USE SIGNAL ;
    SHAPE ABUTMENT ;
    PORT
      LAYER M3 ;
      RECT 0 449.435 0.07 449.505 ;
    END
  END rw0_rd_out[494]
  PIN rw0_rd_out[495]
    DIRECTION OUTPUT ;
    USE SIGNAL ;
    SHAPE ABUTMENT ;
    PORT
      LAYER M3 ;
      RECT 0 449.855 0.07 449.925 ;
    END
  END rw0_rd_out[495]
  PIN rw0_rd_out[496]
    DIRECTION OUTPUT ;
    USE SIGNAL ;
    SHAPE ABUTMENT ;
    PORT
      LAYER M3 ;
      RECT 0 450.275 0.07 450.345 ;
    END
  END rw0_rd_out[496]
  PIN rw0_rd_out[497]
    DIRECTION OUTPUT ;
    USE SIGNAL ;
    SHAPE ABUTMENT ;
    PORT
      LAYER M3 ;
      RECT 0 450.695 0.07 450.765 ;
    END
  END rw0_rd_out[497]
  PIN rw0_rd_out[498]
    DIRECTION OUTPUT ;
    USE SIGNAL ;
    SHAPE ABUTMENT ;
    PORT
      LAYER M3 ;
      RECT 0 451.115 0.07 451.185 ;
    END
  END rw0_rd_out[498]
  PIN rw0_rd_out[499]
    DIRECTION OUTPUT ;
    USE SIGNAL ;
    SHAPE ABUTMENT ;
    PORT
      LAYER M3 ;
      RECT 0 451.535 0.07 451.605 ;
    END
  END rw0_rd_out[499]
  PIN rw0_rd_out[500]
    DIRECTION OUTPUT ;
    USE SIGNAL ;
    SHAPE ABUTMENT ;
    PORT
      LAYER M3 ;
      RECT 0 451.955 0.07 452.025 ;
    END
  END rw0_rd_out[500]
  PIN rw0_rd_out[501]
    DIRECTION OUTPUT ;
    USE SIGNAL ;
    SHAPE ABUTMENT ;
    PORT
      LAYER M3 ;
      RECT 0 452.375 0.07 452.445 ;
    END
  END rw0_rd_out[501]
  PIN rw0_rd_out[502]
    DIRECTION OUTPUT ;
    USE SIGNAL ;
    SHAPE ABUTMENT ;
    PORT
      LAYER M3 ;
      RECT 0 452.795 0.07 452.865 ;
    END
  END rw0_rd_out[502]
  PIN rw0_rd_out[503]
    DIRECTION OUTPUT ;
    USE SIGNAL ;
    SHAPE ABUTMENT ;
    PORT
      LAYER M3 ;
      RECT 0 453.215 0.07 453.285 ;
    END
  END rw0_rd_out[503]
  PIN rw0_rd_out[504]
    DIRECTION OUTPUT ;
    USE SIGNAL ;
    SHAPE ABUTMENT ;
    PORT
      LAYER M3 ;
      RECT 0 453.635 0.07 453.705 ;
    END
  END rw0_rd_out[504]
  PIN rw0_rd_out[505]
    DIRECTION OUTPUT ;
    USE SIGNAL ;
    SHAPE ABUTMENT ;
    PORT
      LAYER M3 ;
      RECT 0 454.055 0.07 454.125 ;
    END
  END rw0_rd_out[505]
  PIN rw0_rd_out[506]
    DIRECTION OUTPUT ;
    USE SIGNAL ;
    SHAPE ABUTMENT ;
    PORT
      LAYER M3 ;
      RECT 0 454.475 0.07 454.545 ;
    END
  END rw0_rd_out[506]
  PIN rw0_rd_out[507]
    DIRECTION OUTPUT ;
    USE SIGNAL ;
    SHAPE ABUTMENT ;
    PORT
      LAYER M3 ;
      RECT 0 454.895 0.07 454.965 ;
    END
  END rw0_rd_out[507]
  PIN rw0_rd_out[508]
    DIRECTION OUTPUT ;
    USE SIGNAL ;
    SHAPE ABUTMENT ;
    PORT
      LAYER M3 ;
      RECT 0 455.315 0.07 455.385 ;
    END
  END rw0_rd_out[508]
  PIN rw0_rd_out[509]
    DIRECTION OUTPUT ;
    USE SIGNAL ;
    SHAPE ABUTMENT ;
    PORT
      LAYER M3 ;
      RECT 0 455.735 0.07 455.805 ;
    END
  END rw0_rd_out[509]
  PIN rw0_rd_out[510]
    DIRECTION OUTPUT ;
    USE SIGNAL ;
    SHAPE ABUTMENT ;
    PORT
      LAYER M3 ;
      RECT 0 456.155 0.07 456.225 ;
    END
  END rw0_rd_out[510]
  PIN rw0_rd_out[511]
    DIRECTION OUTPUT ;
    USE SIGNAL ;
    SHAPE ABUTMENT ;
    PORT
      LAYER M3 ;
      RECT 0 456.575 0.07 456.645 ;
    END
  END rw0_rd_out[511]
  PIN rw0_addr_in[0]
    DIRECTION INPUT ;
    USE SIGNAL ;
    SHAPE ABUTMENT ;
    PORT
      LAYER M3 ;
      RECT 0 456.995 0.07 457.065 ;
    END
  END rw0_addr_in[0]
  PIN rw0_addr_in[1]
    DIRECTION INPUT ;
    USE SIGNAL ;
    SHAPE ABUTMENT ;
    PORT
      LAYER M3 ;
      RECT 0 457.415 0.07 457.485 ;
    END
  END rw0_addr_in[1]
  PIN rw0_addr_in[2]
    DIRECTION INPUT ;
    USE SIGNAL ;
    SHAPE ABUTMENT ;
    PORT
      LAYER M3 ;
      RECT 0 457.835 0.07 457.905 ;
    END
  END rw0_addr_in[2]
  PIN rw0_addr_in[3]
    DIRECTION INPUT ;
    USE SIGNAL ;
    SHAPE ABUTMENT ;
    PORT
      LAYER M3 ;
      RECT 0 458.255 0.07 458.325 ;
    END
  END rw0_addr_in[3]
  PIN rw0_addr_in[4]
    DIRECTION INPUT ;
    USE SIGNAL ;
    SHAPE ABUTMENT ;
    PORT
      LAYER M3 ;
      RECT 0 458.675 0.07 458.745 ;
    END
  END rw0_addr_in[4]
  PIN rw0_addr_in[5]
    DIRECTION INPUT ;
    USE SIGNAL ;
    SHAPE ABUTMENT ;
    PORT
      LAYER M3 ;
      RECT 0 459.095 0.07 459.165 ;
    END
  END rw0_addr_in[5]
  PIN rw0_addr_in[6]
    DIRECTION INPUT ;
    USE SIGNAL ;
    SHAPE ABUTMENT ;
    PORT
      LAYER M3 ;
      RECT 0 459.515 0.07 459.585 ;
    END
  END rw0_addr_in[6]
  PIN rw0_addr_in[7]
    DIRECTION INPUT ;
    USE SIGNAL ;
    SHAPE ABUTMENT ;
    PORT
      LAYER M3 ;
      RECT 0 459.935 0.07 460.005 ;
    END
  END rw0_addr_in[7]
  PIN rw0_we_in
    DIRECTION INPUT ;
    USE SIGNAL ;
    SHAPE ABUTMENT ;
    PORT
      LAYER M3 ;
      RECT 0 460.355 0.07 460.425 ;
    END
  END rw0_we_in
  PIN rw0_ce_in
    DIRECTION INPUT ;
    USE SIGNAL ;
    SHAPE ABUTMENT ;
    PORT
      LAYER M3 ;
      RECT 0 460.775 0.07 460.845 ;
    END
  END rw0_ce_in
  PIN rw0_clk
    DIRECTION INPUT ;
    USE SIGNAL ;
    SHAPE ABUTMENT ;
    PORT
      LAYER M3 ;
      RECT 0 461.195 0.07 461.265 ;
    END
  END rw0_clk
  PIN VSS
    DIRECTION INOUT ;
    USE GROUND ;
    PORT
      LAYER M4 ;
      RECT 1 0.84 1.28 582.96 ;
      RECT 3.24 0.84 3.52 582.96 ;
      RECT 5.48 0.84 5.76 582.96 ;
      RECT 7.72 0.84 8 582.96 ;
      RECT 9.96 0.84 10.24 582.96 ;
      RECT 12.2 0.84 12.48 582.96 ;
      RECT 14.44 0.84 14.72 582.96 ;
      RECT 16.68 0.84 16.96 582.96 ;
      RECT 18.92 0.84 19.2 582.96 ;
      RECT 21.16 0.84 21.44 582.96 ;
      RECT 23.4 0.84 23.68 582.96 ;
      RECT 25.64 0.84 25.92 582.96 ;
      RECT 27.88 0.84 28.16 582.96 ;
      RECT 30.12 0.84 30.4 582.96 ;
      RECT 32.36 0.84 32.64 582.96 ;
      RECT 34.6 0.84 34.88 582.96 ;
      RECT 36.84 0.84 37.12 582.96 ;
      RECT 39.08 0.84 39.36 582.96 ;
      RECT 41.32 0.84 41.6 582.96 ;
      RECT 43.56 0.84 43.84 582.96 ;
      RECT 45.8 0.84 46.08 582.96 ;
      RECT 48.04 0.84 48.32 582.96 ;
      RECT 50.28 0.84 50.56 582.96 ;
      RECT 52.52 0.84 52.8 582.96 ;
      RECT 54.76 0.84 55.04 582.96 ;
      RECT 57 0.84 57.28 582.96 ;
      RECT 59.24 0.84 59.52 582.96 ;
      RECT 61.48 0.84 61.76 582.96 ;
      RECT 63.72 0.84 64 582.96 ;
      RECT 65.96 0.84 66.24 582.96 ;
      RECT 68.2 0.84 68.48 582.96 ;
      RECT 70.44 0.84 70.72 582.96 ;
      RECT 72.68 0.84 72.96 582.96 ;
      RECT 74.92 0.84 75.2 582.96 ;
      RECT 77.16 0.84 77.44 582.96 ;
      RECT 79.4 0.84 79.68 582.96 ;
      RECT 81.64 0.84 81.92 582.96 ;
      RECT 83.88 0.84 84.16 582.96 ;
      RECT 86.12 0.84 86.4 582.96 ;
      RECT 88.36 0.84 88.64 582.96 ;
      RECT 90.6 0.84 90.88 582.96 ;
      RECT 92.84 0.84 93.12 582.96 ;
      RECT 95.08 0.84 95.36 582.96 ;
      RECT 97.32 0.84 97.6 582.96 ;
      RECT 99.56 0.84 99.84 582.96 ;
      RECT 101.8 0.84 102.08 582.96 ;
      RECT 104.04 0.84 104.32 582.96 ;
      RECT 106.28 0.84 106.56 582.96 ;
      RECT 108.52 0.84 108.8 582.96 ;
      RECT 110.76 0.84 111.04 582.96 ;
      RECT 113 0.84 113.28 582.96 ;
      RECT 115.24 0.84 115.52 582.96 ;
      RECT 117.48 0.84 117.76 582.96 ;
      RECT 119.72 0.84 120 582.96 ;
      RECT 121.96 0.84 122.24 582.96 ;
      RECT 124.2 0.84 124.48 582.96 ;
      RECT 126.44 0.84 126.72 582.96 ;
      RECT 128.68 0.84 128.96 582.96 ;
      RECT 130.92 0.84 131.2 582.96 ;
      RECT 133.16 0.84 133.44 582.96 ;
      RECT 135.4 0.84 135.68 582.96 ;
      RECT 137.64 0.84 137.92 582.96 ;
      RECT 139.88 0.84 140.16 582.96 ;
      RECT 142.12 0.84 142.4 582.96 ;
      RECT 144.36 0.84 144.64 582.96 ;
      RECT 146.6 0.84 146.88 582.96 ;
      RECT 148.84 0.84 149.12 582.96 ;
      RECT 151.08 0.84 151.36 582.96 ;
      RECT 153.32 0.84 153.6 582.96 ;
      RECT 155.56 0.84 155.84 582.96 ;
      RECT 157.8 0.84 158.08 582.96 ;
      RECT 160.04 0.84 160.32 582.96 ;
      RECT 162.28 0.84 162.56 582.96 ;
      RECT 164.52 0.84 164.8 582.96 ;
      RECT 166.76 0.84 167.04 582.96 ;
      RECT 169 0.84 169.28 582.96 ;
      RECT 171.24 0.84 171.52 582.96 ;
      RECT 173.48 0.84 173.76 582.96 ;
      RECT 175.72 0.84 176 582.96 ;
      RECT 177.96 0.84 178.24 582.96 ;
      RECT 180.2 0.84 180.48 582.96 ;
      RECT 182.44 0.84 182.72 582.96 ;
      RECT 184.68 0.84 184.96 582.96 ;
      RECT 186.92 0.84 187.2 582.96 ;
      RECT 189.16 0.84 189.44 582.96 ;
      RECT 191.4 0.84 191.68 582.96 ;
      RECT 193.64 0.84 193.92 582.96 ;
      RECT 195.88 0.84 196.16 582.96 ;
      RECT 198.12 0.84 198.4 582.96 ;
      RECT 200.36 0.84 200.64 582.96 ;
      RECT 202.6 0.84 202.88 582.96 ;
      RECT 204.84 0.84 205.12 582.96 ;
      RECT 207.08 0.84 207.36 582.96 ;
      RECT 209.32 0.84 209.6 582.96 ;
      RECT 211.56 0.84 211.84 582.96 ;
      RECT 213.8 0.84 214.08 582.96 ;
      RECT 216.04 0.84 216.32 582.96 ;
      RECT 218.28 0.84 218.56 582.96 ;
      RECT 220.52 0.84 220.8 582.96 ;
      RECT 222.76 0.84 223.04 582.96 ;
      RECT 225 0.84 225.28 582.96 ;
      RECT 227.24 0.84 227.52 582.96 ;
      RECT 229.48 0.84 229.76 582.96 ;
      RECT 231.72 0.84 232 582.96 ;
      RECT 233.96 0.84 234.24 582.96 ;
      RECT 236.2 0.84 236.48 582.96 ;
      RECT 238.44 0.84 238.72 582.96 ;
      RECT 240.68 0.84 240.96 582.96 ;
      RECT 242.92 0.84 243.2 582.96 ;
      RECT 245.16 0.84 245.44 582.96 ;
      RECT 247.4 0.84 247.68 582.96 ;
      RECT 249.64 0.84 249.92 582.96 ;
      RECT 251.88 0.84 252.16 582.96 ;
      RECT 254.12 0.84 254.4 582.96 ;
      RECT 256.36 0.84 256.64 582.96 ;
      RECT 258.6 0.84 258.88 582.96 ;
      RECT 260.84 0.84 261.12 582.96 ;
      RECT 263.08 0.84 263.36 582.96 ;
      RECT 265.32 0.84 265.6 582.96 ;
      RECT 267.56 0.84 267.84 582.96 ;
      RECT 269.8 0.84 270.08 582.96 ;
      RECT 272.04 0.84 272.32 582.96 ;
      RECT 274.28 0.84 274.56 582.96 ;
      RECT 276.52 0.84 276.8 582.96 ;
      RECT 278.76 0.84 279.04 582.96 ;
      RECT 281 0.84 281.28 582.96 ;
      RECT 283.24 0.84 283.52 582.96 ;
      RECT 285.48 0.84 285.76 582.96 ;
      RECT 287.72 0.84 288 582.96 ;
      RECT 289.96 0.84 290.24 582.96 ;
      RECT 292.2 0.84 292.48 582.96 ;
      RECT 294.44 0.84 294.72 582.96 ;
      RECT 296.68 0.84 296.96 582.96 ;
      RECT 298.92 0.84 299.2 582.96 ;
      RECT 301.16 0.84 301.44 582.96 ;
      RECT 303.4 0.84 303.68 582.96 ;
      RECT 305.64 0.84 305.92 582.96 ;
      RECT 307.88 0.84 308.16 582.96 ;
      RECT 310.12 0.84 310.4 582.96 ;
      RECT 312.36 0.84 312.64 582.96 ;
      RECT 314.6 0.84 314.88 582.96 ;
      RECT 316.84 0.84 317.12 582.96 ;
      RECT 319.08 0.84 319.36 582.96 ;
      RECT 321.32 0.84 321.6 582.96 ;
      RECT 323.56 0.84 323.84 582.96 ;
      RECT 325.8 0.84 326.08 582.96 ;
      RECT 328.04 0.84 328.32 582.96 ;
      RECT 330.28 0.84 330.56 582.96 ;
      RECT 332.52 0.84 332.8 582.96 ;
      RECT 334.76 0.84 335.04 582.96 ;
      RECT 337 0.84 337.28 582.96 ;
      RECT 339.24 0.84 339.52 582.96 ;
      RECT 341.48 0.84 341.76 582.96 ;
      RECT 343.72 0.84 344 582.96 ;
      RECT 345.96 0.84 346.24 582.96 ;
      RECT 348.2 0.84 348.48 582.96 ;
      RECT 350.44 0.84 350.72 582.96 ;
      RECT 352.68 0.84 352.96 582.96 ;
      RECT 354.92 0.84 355.2 582.96 ;
      RECT 357.16 0.84 357.44 582.96 ;
      RECT 359.4 0.84 359.68 582.96 ;
      RECT 361.64 0.84 361.92 582.96 ;
      RECT 363.88 0.84 364.16 582.96 ;
      RECT 366.12 0.84 366.4 582.96 ;
      RECT 368.36 0.84 368.64 582.96 ;
      RECT 370.6 0.84 370.88 582.96 ;
      RECT 372.84 0.84 373.12 582.96 ;
      RECT 375.08 0.84 375.36 582.96 ;
      RECT 377.32 0.84 377.6 582.96 ;
      RECT 379.56 0.84 379.84 582.96 ;
      RECT 381.8 0.84 382.08 582.96 ;
      RECT 384.04 0.84 384.32 582.96 ;
      RECT 386.28 0.84 386.56 582.96 ;
      RECT 388.52 0.84 388.8 582.96 ;
      RECT 390.76 0.84 391.04 582.96 ;
      RECT 393 0.84 393.28 582.96 ;
      RECT 395.24 0.84 395.52 582.96 ;
      RECT 397.48 0.84 397.76 582.96 ;
      RECT 399.72 0.84 400 582.96 ;
      RECT 401.96 0.84 402.24 582.96 ;
      RECT 404.2 0.84 404.48 582.96 ;
      RECT 406.44 0.84 406.72 582.96 ;
      RECT 408.68 0.84 408.96 582.96 ;
      RECT 410.92 0.84 411.2 582.96 ;
      RECT 413.16 0.84 413.44 582.96 ;
      RECT 415.4 0.84 415.68 582.96 ;
    END
  END VSS
  PIN VDD
    DIRECTION INOUT ;
    USE POWER ;
    PORT
      LAYER M4 ;
      RECT 2.12 0.84 2.4 582.96 ;
      RECT 4.36 0.84 4.64 582.96 ;
      RECT 6.6 0.84 6.88 582.96 ;
      RECT 8.84 0.84 9.12 582.96 ;
      RECT 11.08 0.84 11.36 582.96 ;
      RECT 13.32 0.84 13.6 582.96 ;
      RECT 15.56 0.84 15.84 582.96 ;
      RECT 17.8 0.84 18.08 582.96 ;
      RECT 20.04 0.84 20.32 582.96 ;
      RECT 22.28 0.84 22.56 582.96 ;
      RECT 24.52 0.84 24.8 582.96 ;
      RECT 26.76 0.84 27.04 582.96 ;
      RECT 29 0.84 29.28 582.96 ;
      RECT 31.24 0.84 31.52 582.96 ;
      RECT 33.48 0.84 33.76 582.96 ;
      RECT 35.72 0.84 36 582.96 ;
      RECT 37.96 0.84 38.24 582.96 ;
      RECT 40.2 0.84 40.48 582.96 ;
      RECT 42.44 0.84 42.72 582.96 ;
      RECT 44.68 0.84 44.96 582.96 ;
      RECT 46.92 0.84 47.2 582.96 ;
      RECT 49.16 0.84 49.44 582.96 ;
      RECT 51.4 0.84 51.68 582.96 ;
      RECT 53.64 0.84 53.92 582.96 ;
      RECT 55.88 0.84 56.16 582.96 ;
      RECT 58.12 0.84 58.4 582.96 ;
      RECT 60.36 0.84 60.64 582.96 ;
      RECT 62.6 0.84 62.88 582.96 ;
      RECT 64.84 0.84 65.12 582.96 ;
      RECT 67.08 0.84 67.36 582.96 ;
      RECT 69.32 0.84 69.6 582.96 ;
      RECT 71.56 0.84 71.84 582.96 ;
      RECT 73.8 0.84 74.08 582.96 ;
      RECT 76.04 0.84 76.32 582.96 ;
      RECT 78.28 0.84 78.56 582.96 ;
      RECT 80.52 0.84 80.8 582.96 ;
      RECT 82.76 0.84 83.04 582.96 ;
      RECT 85 0.84 85.28 582.96 ;
      RECT 87.24 0.84 87.52 582.96 ;
      RECT 89.48 0.84 89.76 582.96 ;
      RECT 91.72 0.84 92 582.96 ;
      RECT 93.96 0.84 94.24 582.96 ;
      RECT 96.2 0.84 96.48 582.96 ;
      RECT 98.44 0.84 98.72 582.96 ;
      RECT 100.68 0.84 100.96 582.96 ;
      RECT 102.92 0.84 103.2 582.96 ;
      RECT 105.16 0.84 105.44 582.96 ;
      RECT 107.4 0.84 107.68 582.96 ;
      RECT 109.64 0.84 109.92 582.96 ;
      RECT 111.88 0.84 112.16 582.96 ;
      RECT 114.12 0.84 114.4 582.96 ;
      RECT 116.36 0.84 116.64 582.96 ;
      RECT 118.6 0.84 118.88 582.96 ;
      RECT 120.84 0.84 121.12 582.96 ;
      RECT 123.08 0.84 123.36 582.96 ;
      RECT 125.32 0.84 125.6 582.96 ;
      RECT 127.56 0.84 127.84 582.96 ;
      RECT 129.8 0.84 130.08 582.96 ;
      RECT 132.04 0.84 132.32 582.96 ;
      RECT 134.28 0.84 134.56 582.96 ;
      RECT 136.52 0.84 136.8 582.96 ;
      RECT 138.76 0.84 139.04 582.96 ;
      RECT 141 0.84 141.28 582.96 ;
      RECT 143.24 0.84 143.52 582.96 ;
      RECT 145.48 0.84 145.76 582.96 ;
      RECT 147.72 0.84 148 582.96 ;
      RECT 149.96 0.84 150.24 582.96 ;
      RECT 152.2 0.84 152.48 582.96 ;
      RECT 154.44 0.84 154.72 582.96 ;
      RECT 156.68 0.84 156.96 582.96 ;
      RECT 158.92 0.84 159.2 582.96 ;
      RECT 161.16 0.84 161.44 582.96 ;
      RECT 163.4 0.84 163.68 582.96 ;
      RECT 165.64 0.84 165.92 582.96 ;
      RECT 167.88 0.84 168.16 582.96 ;
      RECT 170.12 0.84 170.4 582.96 ;
      RECT 172.36 0.84 172.64 582.96 ;
      RECT 174.6 0.84 174.88 582.96 ;
      RECT 176.84 0.84 177.12 582.96 ;
      RECT 179.08 0.84 179.36 582.96 ;
      RECT 181.32 0.84 181.6 582.96 ;
      RECT 183.56 0.84 183.84 582.96 ;
      RECT 185.8 0.84 186.08 582.96 ;
      RECT 188.04 0.84 188.32 582.96 ;
      RECT 190.28 0.84 190.56 582.96 ;
      RECT 192.52 0.84 192.8 582.96 ;
      RECT 194.76 0.84 195.04 582.96 ;
      RECT 197 0.84 197.28 582.96 ;
      RECT 199.24 0.84 199.52 582.96 ;
      RECT 201.48 0.84 201.76 582.96 ;
      RECT 203.72 0.84 204 582.96 ;
      RECT 205.96 0.84 206.24 582.96 ;
      RECT 208.2 0.84 208.48 582.96 ;
      RECT 210.44 0.84 210.72 582.96 ;
      RECT 212.68 0.84 212.96 582.96 ;
      RECT 214.92 0.84 215.2 582.96 ;
      RECT 217.16 0.84 217.44 582.96 ;
      RECT 219.4 0.84 219.68 582.96 ;
      RECT 221.64 0.84 221.92 582.96 ;
      RECT 223.88 0.84 224.16 582.96 ;
      RECT 226.12 0.84 226.4 582.96 ;
      RECT 228.36 0.84 228.64 582.96 ;
      RECT 230.6 0.84 230.88 582.96 ;
      RECT 232.84 0.84 233.12 582.96 ;
      RECT 235.08 0.84 235.36 582.96 ;
      RECT 237.32 0.84 237.6 582.96 ;
      RECT 239.56 0.84 239.84 582.96 ;
      RECT 241.8 0.84 242.08 582.96 ;
      RECT 244.04 0.84 244.32 582.96 ;
      RECT 246.28 0.84 246.56 582.96 ;
      RECT 248.52 0.84 248.8 582.96 ;
      RECT 250.76 0.84 251.04 582.96 ;
      RECT 253 0.84 253.28 582.96 ;
      RECT 255.24 0.84 255.52 582.96 ;
      RECT 257.48 0.84 257.76 582.96 ;
      RECT 259.72 0.84 260 582.96 ;
      RECT 261.96 0.84 262.24 582.96 ;
      RECT 264.2 0.84 264.48 582.96 ;
      RECT 266.44 0.84 266.72 582.96 ;
      RECT 268.68 0.84 268.96 582.96 ;
      RECT 270.92 0.84 271.2 582.96 ;
      RECT 273.16 0.84 273.44 582.96 ;
      RECT 275.4 0.84 275.68 582.96 ;
      RECT 277.64 0.84 277.92 582.96 ;
      RECT 279.88 0.84 280.16 582.96 ;
      RECT 282.12 0.84 282.4 582.96 ;
      RECT 284.36 0.84 284.64 582.96 ;
      RECT 286.6 0.84 286.88 582.96 ;
      RECT 288.84 0.84 289.12 582.96 ;
      RECT 291.08 0.84 291.36 582.96 ;
      RECT 293.32 0.84 293.6 582.96 ;
      RECT 295.56 0.84 295.84 582.96 ;
      RECT 297.8 0.84 298.08 582.96 ;
      RECT 300.04 0.84 300.32 582.96 ;
      RECT 302.28 0.84 302.56 582.96 ;
      RECT 304.52 0.84 304.8 582.96 ;
      RECT 306.76 0.84 307.04 582.96 ;
      RECT 309 0.84 309.28 582.96 ;
      RECT 311.24 0.84 311.52 582.96 ;
      RECT 313.48 0.84 313.76 582.96 ;
      RECT 315.72 0.84 316 582.96 ;
      RECT 317.96 0.84 318.24 582.96 ;
      RECT 320.2 0.84 320.48 582.96 ;
      RECT 322.44 0.84 322.72 582.96 ;
      RECT 324.68 0.84 324.96 582.96 ;
      RECT 326.92 0.84 327.2 582.96 ;
      RECT 329.16 0.84 329.44 582.96 ;
      RECT 331.4 0.84 331.68 582.96 ;
      RECT 333.64 0.84 333.92 582.96 ;
      RECT 335.88 0.84 336.16 582.96 ;
      RECT 338.12 0.84 338.4 582.96 ;
      RECT 340.36 0.84 340.64 582.96 ;
      RECT 342.6 0.84 342.88 582.96 ;
      RECT 344.84 0.84 345.12 582.96 ;
      RECT 347.08 0.84 347.36 582.96 ;
      RECT 349.32 0.84 349.6 582.96 ;
      RECT 351.56 0.84 351.84 582.96 ;
      RECT 353.8 0.84 354.08 582.96 ;
      RECT 356.04 0.84 356.32 582.96 ;
      RECT 358.28 0.84 358.56 582.96 ;
      RECT 360.52 0.84 360.8 582.96 ;
      RECT 362.76 0.84 363.04 582.96 ;
      RECT 365 0.84 365.28 582.96 ;
      RECT 367.24 0.84 367.52 582.96 ;
      RECT 369.48 0.84 369.76 582.96 ;
      RECT 371.72 0.84 372 582.96 ;
      RECT 373.96 0.84 374.24 582.96 ;
      RECT 376.2 0.84 376.48 582.96 ;
      RECT 378.44 0.84 378.72 582.96 ;
      RECT 380.68 0.84 380.96 582.96 ;
      RECT 382.92 0.84 383.2 582.96 ;
      RECT 385.16 0.84 385.44 582.96 ;
      RECT 387.4 0.84 387.68 582.96 ;
      RECT 389.64 0.84 389.92 582.96 ;
      RECT 391.88 0.84 392.16 582.96 ;
      RECT 394.12 0.84 394.4 582.96 ;
      RECT 396.36 0.84 396.64 582.96 ;
      RECT 398.6 0.84 398.88 582.96 ;
      RECT 400.84 0.84 401.12 582.96 ;
      RECT 403.08 0.84 403.36 582.96 ;
      RECT 405.32 0.84 405.6 582.96 ;
      RECT 407.56 0.84 407.84 582.96 ;
      RECT 409.8 0.84 410.08 582.96 ;
      RECT 412.04 0.84 412.32 582.96 ;
      RECT 414.28 0.84 414.56 582.96 ;
      RECT 416.52 0.84 416.8 582.96 ;
    END
  END VDD
  OBS
    LAYER M1 ;
    RECT 0 0 417.43 583.8 ;
    LAYER M2 ;
    RECT 0 0 417.43 583.8 ;
  END
END ht45_rocketgemmini_rockettile_dcache_data_arrays_0_ext_bottom

END LIBRARY
